# Placeholder macro written by tools/chip_assembly/macros.py
# kind: link; UCIe-A shoreline (die assembly 1.043 x 6.61 mm) at 1/4, one 512-bit flit port each way
VERSION 5.7 ;
BUSBITCHARS "[]" ;
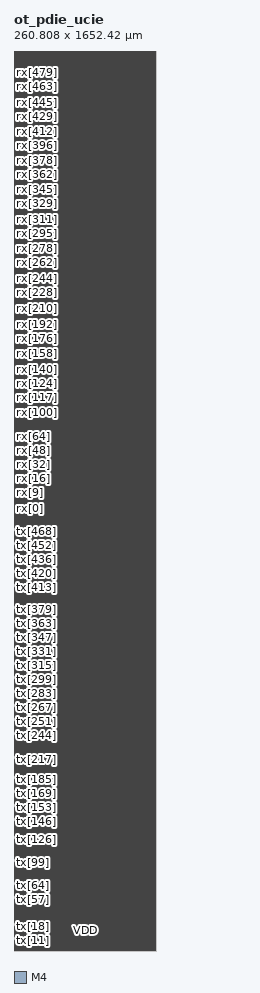
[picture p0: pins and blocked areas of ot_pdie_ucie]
MACRO ot_pdie_ucie
  FOREIGN ot_pdie_ucie 0 0 ;
  SYMMETRY X Y ;
  SIZE 260.808 BY 1652.424 ;
  CLASS BLOCK ;
  PIN clk
    DIRECTION INPUT ;
    USE SIGNAL ;
    SHAPE ABUTMENT ;
    PORT
      LAYER M4 ;
      RECT 0.000 0.528 0.192 0.552 ;
    END
  END clk
  PIN tx[0]
    DIRECTION INPUT ;
    USE SIGNAL ;
    SHAPE ABUTMENT ;
    PORT
      LAYER M4 ;
      RECT 0.000 2.112 0.192 2.136 ;
    END
  END tx[0]
  PIN tx[1]
    DIRECTION INPUT ;
    USE SIGNAL ;
    SHAPE ABUTMENT ;
    PORT
      LAYER M4 ;
      RECT 0.000 3.744 0.192 3.768 ;
    END
  END tx[1]
  PIN tx[2]
    DIRECTION INPUT ;
    USE SIGNAL ;
    SHAPE ABUTMENT ;
    PORT
      LAYER M4 ;
      RECT 0.000 5.328 0.192 5.352 ;
    END
  END tx[2]
  PIN tx[3]
    DIRECTION INPUT ;
    USE SIGNAL ;
    SHAPE ABUTMENT ;
    PORT
      LAYER M4 ;
      RECT 0.000 6.960 0.192 6.984 ;
    END
  END tx[3]
  PIN tx[4]
    DIRECTION INPUT ;
    USE SIGNAL ;
    SHAPE ABUTMENT ;
    PORT
      LAYER M4 ;
      RECT 0.000 8.544 0.192 8.568 ;
    END
  END tx[4]
  PIN tx[5]
    DIRECTION INPUT ;
    USE SIGNAL ;
    SHAPE ABUTMENT ;
    PORT
      LAYER M4 ;
      RECT 0.000 10.176 0.192 10.200 ;
    END
  END tx[5]
  PIN tx[6]
    DIRECTION INPUT ;
    USE SIGNAL ;
    SHAPE ABUTMENT ;
    PORT
      LAYER M4 ;
      RECT 0.000 11.760 0.192 11.784 ;
    END
  END tx[6]
  PIN tx[7]
    DIRECTION INPUT ;
    USE SIGNAL ;
    SHAPE ABUTMENT ;
    PORT
      LAYER M4 ;
      RECT 0.000 13.392 0.192 13.416 ;
    END
  END tx[7]
  PIN tx[8]
    DIRECTION INPUT ;
    USE SIGNAL ;
    SHAPE ABUTMENT ;
    PORT
      LAYER M4 ;
      RECT 0.000 15.024 0.192 15.048 ;
    END
  END tx[8]
  PIN tx[9]
    DIRECTION INPUT ;
    USE SIGNAL ;
    SHAPE ABUTMENT ;
    PORT
      LAYER M4 ;
      RECT 0.000 16.608 0.192 16.632 ;
    END
  END tx[9]
  PIN tx[10]
    DIRECTION INPUT ;
    USE SIGNAL ;
    SHAPE ABUTMENT ;
    PORT
      LAYER M4 ;
      RECT 0.000 18.240 0.192 18.264 ;
    END
  END tx[10]
  PIN tx[11]
    DIRECTION INPUT ;
    USE SIGNAL ;
    SHAPE ABUTMENT ;
    PORT
      LAYER M4 ;
      RECT 0.000 19.824 0.192 19.848 ;
    END
  END tx[11]
  PIN tx[12]
    DIRECTION INPUT ;
    USE SIGNAL ;
    SHAPE ABUTMENT ;
    PORT
      LAYER M4 ;
      RECT 0.000 21.456 0.192 21.480 ;
    END
  END tx[12]
  PIN tx[13]
    DIRECTION INPUT ;
    USE SIGNAL ;
    SHAPE ABUTMENT ;
    PORT
      LAYER M4 ;
      RECT 0.000 23.040 0.192 23.064 ;
    END
  END tx[13]
  PIN tx[14]
    DIRECTION INPUT ;
    USE SIGNAL ;
    SHAPE ABUTMENT ;
    PORT
      LAYER M4 ;
      RECT 0.000 24.672 0.192 24.696 ;
    END
  END tx[14]
  PIN tx[15]
    DIRECTION INPUT ;
    USE SIGNAL ;
    SHAPE ABUTMENT ;
    PORT
      LAYER M4 ;
      RECT 0.000 26.304 0.192 26.328 ;
    END
  END tx[15]
  PIN tx[16]
    DIRECTION INPUT ;
    USE SIGNAL ;
    SHAPE ABUTMENT ;
    PORT
      LAYER M4 ;
      RECT 0.000 27.888 0.192 27.912 ;
    END
  END tx[16]
  PIN tx[17]
    DIRECTION INPUT ;
    USE SIGNAL ;
    SHAPE ABUTMENT ;
    PORT
      LAYER M4 ;
      RECT 0.000 29.520 0.192 29.544 ;
    END
  END tx[17]
  PIN tx[18]
    DIRECTION INPUT ;
    USE SIGNAL ;
    SHAPE ABUTMENT ;
    PORT
      LAYER M4 ;
      RECT 0.000 31.104 0.192 31.128 ;
    END
  END tx[18]
  PIN tx[19]
    DIRECTION INPUT ;
    USE SIGNAL ;
    SHAPE ABUTMENT ;
    PORT
      LAYER M4 ;
      RECT 0.000 32.736 0.192 32.760 ;
    END
  END tx[19]
  PIN tx[20]
    DIRECTION INPUT ;
    USE SIGNAL ;
    SHAPE ABUTMENT ;
    PORT
      LAYER M4 ;
      RECT 0.000 34.320 0.192 34.344 ;
    END
  END tx[20]
  PIN tx[21]
    DIRECTION INPUT ;
    USE SIGNAL ;
    SHAPE ABUTMENT ;
    PORT
      LAYER M4 ;
      RECT 0.000 35.952 0.192 35.976 ;
    END
  END tx[21]
  PIN tx[22]
    DIRECTION INPUT ;
    USE SIGNAL ;
    SHAPE ABUTMENT ;
    PORT
      LAYER M4 ;
      RECT 0.000 37.536 0.192 37.560 ;
    END
  END tx[22]
  PIN tx[23]
    DIRECTION INPUT ;
    USE SIGNAL ;
    SHAPE ABUTMENT ;
    PORT
      LAYER M4 ;
      RECT 0.000 39.168 0.192 39.192 ;
    END
  END tx[23]
  PIN tx[24]
    DIRECTION INPUT ;
    USE SIGNAL ;
    SHAPE ABUTMENT ;
    PORT
      LAYER M4 ;
      RECT 0.000 40.800 0.192 40.824 ;
    END
  END tx[24]
  PIN tx[25]
    DIRECTION INPUT ;
    USE SIGNAL ;
    SHAPE ABUTMENT ;
    PORT
      LAYER M4 ;
      RECT 0.000 42.384 0.192 42.408 ;
    END
  END tx[25]
  PIN tx[26]
    DIRECTION INPUT ;
    USE SIGNAL ;
    SHAPE ABUTMENT ;
    PORT
      LAYER M4 ;
      RECT 0.000 44.016 0.192 44.040 ;
    END
  END tx[26]
  PIN tx[27]
    DIRECTION INPUT ;
    USE SIGNAL ;
    SHAPE ABUTMENT ;
    PORT
      LAYER M4 ;
      RECT 0.000 45.600 0.192 45.624 ;
    END
  END tx[27]
  PIN tx[28]
    DIRECTION INPUT ;
    USE SIGNAL ;
    SHAPE ABUTMENT ;
    PORT
      LAYER M4 ;
      RECT 0.000 47.232 0.192 47.256 ;
    END
  END tx[28]
  PIN tx[29]
    DIRECTION INPUT ;
    USE SIGNAL ;
    SHAPE ABUTMENT ;
    PORT
      LAYER M4 ;
      RECT 0.000 48.816 0.192 48.840 ;
    END
  END tx[29]
  PIN tx[30]
    DIRECTION INPUT ;
    USE SIGNAL ;
    SHAPE ABUTMENT ;
    PORT
      LAYER M4 ;
      RECT 0.000 50.448 0.192 50.472 ;
    END
  END tx[30]
  PIN tx[31]
    DIRECTION INPUT ;
    USE SIGNAL ;
    SHAPE ABUTMENT ;
    PORT
      LAYER M4 ;
      RECT 0.000 52.080 0.192 52.104 ;
    END
  END tx[31]
  PIN tx[32]
    DIRECTION INPUT ;
    USE SIGNAL ;
    SHAPE ABUTMENT ;
    PORT
      LAYER M4 ;
      RECT 0.000 53.664 0.192 53.688 ;
    END
  END tx[32]
  PIN tx[33]
    DIRECTION INPUT ;
    USE SIGNAL ;
    SHAPE ABUTMENT ;
    PORT
      LAYER M4 ;
      RECT 0.000 55.296 0.192 55.320 ;
    END
  END tx[33]
  PIN tx[34]
    DIRECTION INPUT ;
    USE SIGNAL ;
    SHAPE ABUTMENT ;
    PORT
      LAYER M4 ;
      RECT 0.000 56.880 0.192 56.904 ;
    END
  END tx[34]
  PIN tx[35]
    DIRECTION INPUT ;
    USE SIGNAL ;
    SHAPE ABUTMENT ;
    PORT
      LAYER M4 ;
      RECT 0.000 58.512 0.192 58.536 ;
    END
  END tx[35]
  PIN tx[36]
    DIRECTION INPUT ;
    USE SIGNAL ;
    SHAPE ABUTMENT ;
    PORT
      LAYER M4 ;
      RECT 0.000 60.096 0.192 60.120 ;
    END
  END tx[36]
  PIN tx[37]
    DIRECTION INPUT ;
    USE SIGNAL ;
    SHAPE ABUTMENT ;
    PORT
      LAYER M4 ;
      RECT 0.000 61.728 0.192 61.752 ;
    END
  END tx[37]
  PIN tx[38]
    DIRECTION INPUT ;
    USE SIGNAL ;
    SHAPE ABUTMENT ;
    PORT
      LAYER M4 ;
      RECT 0.000 63.360 0.192 63.384 ;
    END
  END tx[38]
  PIN tx[39]
    DIRECTION INPUT ;
    USE SIGNAL ;
    SHAPE ABUTMENT ;
    PORT
      LAYER M4 ;
      RECT 0.000 64.944 0.192 64.968 ;
    END
  END tx[39]
  PIN tx[40]
    DIRECTION INPUT ;
    USE SIGNAL ;
    SHAPE ABUTMENT ;
    PORT
      LAYER M4 ;
      RECT 0.000 66.576 0.192 66.600 ;
    END
  END tx[40]
  PIN tx[41]
    DIRECTION INPUT ;
    USE SIGNAL ;
    SHAPE ABUTMENT ;
    PORT
      LAYER M4 ;
      RECT 0.000 68.160 0.192 68.184 ;
    END
  END tx[41]
  PIN tx[42]
    DIRECTION INPUT ;
    USE SIGNAL ;
    SHAPE ABUTMENT ;
    PORT
      LAYER M4 ;
      RECT 0.000 69.792 0.192 69.816 ;
    END
  END tx[42]
  PIN tx[43]
    DIRECTION INPUT ;
    USE SIGNAL ;
    SHAPE ABUTMENT ;
    PORT
      LAYER M4 ;
      RECT 0.000 71.376 0.192 71.400 ;
    END
  END tx[43]
  PIN tx[44]
    DIRECTION INPUT ;
    USE SIGNAL ;
    SHAPE ABUTMENT ;
    PORT
      LAYER M4 ;
      RECT 0.000 73.008 0.192 73.032 ;
    END
  END tx[44]
  PIN tx[45]
    DIRECTION INPUT ;
    USE SIGNAL ;
    SHAPE ABUTMENT ;
    PORT
      LAYER M4 ;
      RECT 0.000 74.592 0.192 74.616 ;
    END
  END tx[45]
  PIN tx[46]
    DIRECTION INPUT ;
    USE SIGNAL ;
    SHAPE ABUTMENT ;
    PORT
      LAYER M4 ;
      RECT 0.000 76.224 0.192 76.248 ;
    END
  END tx[46]
  PIN tx[47]
    DIRECTION INPUT ;
    USE SIGNAL ;
    SHAPE ABUTMENT ;
    PORT
      LAYER M4 ;
      RECT 0.000 77.856 0.192 77.880 ;
    END
  END tx[47]
  PIN tx[48]
    DIRECTION INPUT ;
    USE SIGNAL ;
    SHAPE ABUTMENT ;
    PORT
      LAYER M4 ;
      RECT 0.000 79.440 0.192 79.464 ;
    END
  END tx[48]
  PIN tx[49]
    DIRECTION INPUT ;
    USE SIGNAL ;
    SHAPE ABUTMENT ;
    PORT
      LAYER M4 ;
      RECT 0.000 81.072 0.192 81.096 ;
    END
  END tx[49]
  PIN tx[50]
    DIRECTION INPUT ;
    USE SIGNAL ;
    SHAPE ABUTMENT ;
    PORT
      LAYER M4 ;
      RECT 0.000 82.656 0.192 82.680 ;
    END
  END tx[50]
  PIN tx[51]
    DIRECTION INPUT ;
    USE SIGNAL ;
    SHAPE ABUTMENT ;
    PORT
      LAYER M4 ;
      RECT 0.000 84.288 0.192 84.312 ;
    END
  END tx[51]
  PIN tx[52]
    DIRECTION INPUT ;
    USE SIGNAL ;
    SHAPE ABUTMENT ;
    PORT
      LAYER M4 ;
      RECT 0.000 85.872 0.192 85.896 ;
    END
  END tx[52]
  PIN tx[53]
    DIRECTION INPUT ;
    USE SIGNAL ;
    SHAPE ABUTMENT ;
    PORT
      LAYER M4 ;
      RECT 0.000 87.504 0.192 87.528 ;
    END
  END tx[53]
  PIN tx[54]
    DIRECTION INPUT ;
    USE SIGNAL ;
    SHAPE ABUTMENT ;
    PORT
      LAYER M4 ;
      RECT 0.000 89.136 0.192 89.160 ;
    END
  END tx[54]
  PIN tx[55]
    DIRECTION INPUT ;
    USE SIGNAL ;
    SHAPE ABUTMENT ;
    PORT
      LAYER M4 ;
      RECT 0.000 90.720 0.192 90.744 ;
    END
  END tx[55]
  PIN tx[56]
    DIRECTION INPUT ;
    USE SIGNAL ;
    SHAPE ABUTMENT ;
    PORT
      LAYER M4 ;
      RECT 0.000 92.352 0.192 92.376 ;
    END
  END tx[56]
  PIN tx[57]
    DIRECTION INPUT ;
    USE SIGNAL ;
    SHAPE ABUTMENT ;
    PORT
      LAYER M4 ;
      RECT 0.000 93.936 0.192 93.960 ;
    END
  END tx[57]
  PIN tx[58]
    DIRECTION INPUT ;
    USE SIGNAL ;
    SHAPE ABUTMENT ;
    PORT
      LAYER M4 ;
      RECT 0.000 95.568 0.192 95.592 ;
    END
  END tx[58]
  PIN tx[59]
    DIRECTION INPUT ;
    USE SIGNAL ;
    SHAPE ABUTMENT ;
    PORT
      LAYER M4 ;
      RECT 0.000 97.152 0.192 97.176 ;
    END
  END tx[59]
  PIN tx[60]
    DIRECTION INPUT ;
    USE SIGNAL ;
    SHAPE ABUTMENT ;
    PORT
      LAYER M4 ;
      RECT 0.000 98.784 0.192 98.808 ;
    END
  END tx[60]
  PIN tx[61]
    DIRECTION INPUT ;
    USE SIGNAL ;
    SHAPE ABUTMENT ;
    PORT
      LAYER M4 ;
      RECT 0.000 100.416 0.192 100.440 ;
    END
  END tx[61]
  PIN tx[62]
    DIRECTION INPUT ;
    USE SIGNAL ;
    SHAPE ABUTMENT ;
    PORT
      LAYER M4 ;
      RECT 0.000 102.000 0.192 102.024 ;
    END
  END tx[62]
  PIN tx[63]
    DIRECTION INPUT ;
    USE SIGNAL ;
    SHAPE ABUTMENT ;
    PORT
      LAYER M4 ;
      RECT 0.000 103.632 0.192 103.656 ;
    END
  END tx[63]
  PIN tx[64]
    DIRECTION INPUT ;
    USE SIGNAL ;
    SHAPE ABUTMENT ;
    PORT
      LAYER M4 ;
      RECT 0.000 105.216 0.192 105.240 ;
    END
  END tx[64]
  PIN tx[65]
    DIRECTION INPUT ;
    USE SIGNAL ;
    SHAPE ABUTMENT ;
    PORT
      LAYER M4 ;
      RECT 0.000 106.848 0.192 106.872 ;
    END
  END tx[65]
  PIN tx[66]
    DIRECTION INPUT ;
    USE SIGNAL ;
    SHAPE ABUTMENT ;
    PORT
      LAYER M4 ;
      RECT 0.000 108.432 0.192 108.456 ;
    END
  END tx[66]
  PIN tx[67]
    DIRECTION INPUT ;
    USE SIGNAL ;
    SHAPE ABUTMENT ;
    PORT
      LAYER M4 ;
      RECT 0.000 110.064 0.192 110.088 ;
    END
  END tx[67]
  PIN tx[68]
    DIRECTION INPUT ;
    USE SIGNAL ;
    SHAPE ABUTMENT ;
    PORT
      LAYER M4 ;
      RECT 0.000 111.648 0.192 111.672 ;
    END
  END tx[68]
  PIN tx[69]
    DIRECTION INPUT ;
    USE SIGNAL ;
    SHAPE ABUTMENT ;
    PORT
      LAYER M4 ;
      RECT 0.000 113.280 0.192 113.304 ;
    END
  END tx[69]
  PIN tx[70]
    DIRECTION INPUT ;
    USE SIGNAL ;
    SHAPE ABUTMENT ;
    PORT
      LAYER M4 ;
      RECT 0.000 114.912 0.192 114.936 ;
    END
  END tx[70]
  PIN tx[71]
    DIRECTION INPUT ;
    USE SIGNAL ;
    SHAPE ABUTMENT ;
    PORT
      LAYER M4 ;
      RECT 0.000 116.496 0.192 116.520 ;
    END
  END tx[71]
  PIN tx[72]
    DIRECTION INPUT ;
    USE SIGNAL ;
    SHAPE ABUTMENT ;
    PORT
      LAYER M4 ;
      RECT 0.000 118.128 0.192 118.152 ;
    END
  END tx[72]
  PIN tx[73]
    DIRECTION INPUT ;
    USE SIGNAL ;
    SHAPE ABUTMENT ;
    PORT
      LAYER M4 ;
      RECT 0.000 119.712 0.192 119.736 ;
    END
  END tx[73]
  PIN tx[74]
    DIRECTION INPUT ;
    USE SIGNAL ;
    SHAPE ABUTMENT ;
    PORT
      LAYER M4 ;
      RECT 0.000 121.344 0.192 121.368 ;
    END
  END tx[74]
  PIN tx[75]
    DIRECTION INPUT ;
    USE SIGNAL ;
    SHAPE ABUTMENT ;
    PORT
      LAYER M4 ;
      RECT 0.000 122.928 0.192 122.952 ;
    END
  END tx[75]
  PIN tx[76]
    DIRECTION INPUT ;
    USE SIGNAL ;
    SHAPE ABUTMENT ;
    PORT
      LAYER M4 ;
      RECT 0.000 124.560 0.192 124.584 ;
    END
  END tx[76]
  PIN tx[77]
    DIRECTION INPUT ;
    USE SIGNAL ;
    SHAPE ABUTMENT ;
    PORT
      LAYER M4 ;
      RECT 0.000 126.192 0.192 126.216 ;
    END
  END tx[77]
  PIN tx[78]
    DIRECTION INPUT ;
    USE SIGNAL ;
    SHAPE ABUTMENT ;
    PORT
      LAYER M4 ;
      RECT 0.000 127.776 0.192 127.800 ;
    END
  END tx[78]
  PIN tx[79]
    DIRECTION INPUT ;
    USE SIGNAL ;
    SHAPE ABUTMENT ;
    PORT
      LAYER M4 ;
      RECT 0.000 129.408 0.192 129.432 ;
    END
  END tx[79]
  PIN tx[80]
    DIRECTION INPUT ;
    USE SIGNAL ;
    SHAPE ABUTMENT ;
    PORT
      LAYER M4 ;
      RECT 0.000 130.992 0.192 131.016 ;
    END
  END tx[80]
  PIN tx[81]
    DIRECTION INPUT ;
    USE SIGNAL ;
    SHAPE ABUTMENT ;
    PORT
      LAYER M4 ;
      RECT 0.000 132.624 0.192 132.648 ;
    END
  END tx[81]
  PIN tx[82]
    DIRECTION INPUT ;
    USE SIGNAL ;
    SHAPE ABUTMENT ;
    PORT
      LAYER M4 ;
      RECT 0.000 134.208 0.192 134.232 ;
    END
  END tx[82]
  PIN tx[83]
    DIRECTION INPUT ;
    USE SIGNAL ;
    SHAPE ABUTMENT ;
    PORT
      LAYER M4 ;
      RECT 0.000 135.840 0.192 135.864 ;
    END
  END tx[83]
  PIN tx[84]
    DIRECTION INPUT ;
    USE SIGNAL ;
    SHAPE ABUTMENT ;
    PORT
      LAYER M4 ;
      RECT 0.000 137.472 0.192 137.496 ;
    END
  END tx[84]
  PIN tx[85]
    DIRECTION INPUT ;
    USE SIGNAL ;
    SHAPE ABUTMENT ;
    PORT
      LAYER M4 ;
      RECT 0.000 139.056 0.192 139.080 ;
    END
  END tx[85]
  PIN tx[86]
    DIRECTION INPUT ;
    USE SIGNAL ;
    SHAPE ABUTMENT ;
    PORT
      LAYER M4 ;
      RECT 0.000 140.688 0.192 140.712 ;
    END
  END tx[86]
  PIN tx[87]
    DIRECTION INPUT ;
    USE SIGNAL ;
    SHAPE ABUTMENT ;
    PORT
      LAYER M4 ;
      RECT 0.000 142.272 0.192 142.296 ;
    END
  END tx[87]
  PIN tx[88]
    DIRECTION INPUT ;
    USE SIGNAL ;
    SHAPE ABUTMENT ;
    PORT
      LAYER M4 ;
      RECT 0.000 143.904 0.192 143.928 ;
    END
  END tx[88]
  PIN tx[89]
    DIRECTION INPUT ;
    USE SIGNAL ;
    SHAPE ABUTMENT ;
    PORT
      LAYER M4 ;
      RECT 0.000 145.488 0.192 145.512 ;
    END
  END tx[89]
  PIN tx[90]
    DIRECTION INPUT ;
    USE SIGNAL ;
    SHAPE ABUTMENT ;
    PORT
      LAYER M4 ;
      RECT 0.000 147.120 0.192 147.144 ;
    END
  END tx[90]
  PIN tx[91]
    DIRECTION INPUT ;
    USE SIGNAL ;
    SHAPE ABUTMENT ;
    PORT
      LAYER M4 ;
      RECT 0.000 148.704 0.192 148.728 ;
    END
  END tx[91]
  PIN tx[92]
    DIRECTION INPUT ;
    USE SIGNAL ;
    SHAPE ABUTMENT ;
    PORT
      LAYER M4 ;
      RECT 0.000 150.336 0.192 150.360 ;
    END
  END tx[92]
  PIN tx[93]
    DIRECTION INPUT ;
    USE SIGNAL ;
    SHAPE ABUTMENT ;
    PORT
      LAYER M4 ;
      RECT 0.000 151.968 0.192 151.992 ;
    END
  END tx[93]
  PIN tx[94]
    DIRECTION INPUT ;
    USE SIGNAL ;
    SHAPE ABUTMENT ;
    PORT
      LAYER M4 ;
      RECT 0.000 153.552 0.192 153.576 ;
    END
  END tx[94]
  PIN tx[95]
    DIRECTION INPUT ;
    USE SIGNAL ;
    SHAPE ABUTMENT ;
    PORT
      LAYER M4 ;
      RECT 0.000 155.184 0.192 155.208 ;
    END
  END tx[95]
  PIN tx[96]
    DIRECTION INPUT ;
    USE SIGNAL ;
    SHAPE ABUTMENT ;
    PORT
      LAYER M4 ;
      RECT 0.000 156.768 0.192 156.792 ;
    END
  END tx[96]
  PIN tx[97]
    DIRECTION INPUT ;
    USE SIGNAL ;
    SHAPE ABUTMENT ;
    PORT
      LAYER M4 ;
      RECT 0.000 158.400 0.192 158.424 ;
    END
  END tx[97]
  PIN tx[98]
    DIRECTION INPUT ;
    USE SIGNAL ;
    SHAPE ABUTMENT ;
    PORT
      LAYER M4 ;
      RECT 0.000 159.984 0.192 160.008 ;
    END
  END tx[98]
  PIN tx[99]
    DIRECTION INPUT ;
    USE SIGNAL ;
    SHAPE ABUTMENT ;
    PORT
      LAYER M4 ;
      RECT 0.000 161.616 0.192 161.640 ;
    END
  END tx[99]
  PIN tx[100]
    DIRECTION INPUT ;
    USE SIGNAL ;
    SHAPE ABUTMENT ;
    PORT
      LAYER M4 ;
      RECT 0.000 163.248 0.192 163.272 ;
    END
  END tx[100]
  PIN tx[101]
    DIRECTION INPUT ;
    USE SIGNAL ;
    SHAPE ABUTMENT ;
    PORT
      LAYER M4 ;
      RECT 0.000 164.832 0.192 164.856 ;
    END
  END tx[101]
  PIN tx[102]
    DIRECTION INPUT ;
    USE SIGNAL ;
    SHAPE ABUTMENT ;
    PORT
      LAYER M4 ;
      RECT 0.000 166.464 0.192 166.488 ;
    END
  END tx[102]
  PIN tx[103]
    DIRECTION INPUT ;
    USE SIGNAL ;
    SHAPE ABUTMENT ;
    PORT
      LAYER M4 ;
      RECT 0.000 168.048 0.192 168.072 ;
    END
  END tx[103]
  PIN tx[104]
    DIRECTION INPUT ;
    USE SIGNAL ;
    SHAPE ABUTMENT ;
    PORT
      LAYER M4 ;
      RECT 0.000 169.680 0.192 169.704 ;
    END
  END tx[104]
  PIN tx[105]
    DIRECTION INPUT ;
    USE SIGNAL ;
    SHAPE ABUTMENT ;
    PORT
      LAYER M4 ;
      RECT 0.000 171.264 0.192 171.288 ;
    END
  END tx[105]
  PIN tx[106]
    DIRECTION INPUT ;
    USE SIGNAL ;
    SHAPE ABUTMENT ;
    PORT
      LAYER M4 ;
      RECT 0.000 172.896 0.192 172.920 ;
    END
  END tx[106]
  PIN tx[107]
    DIRECTION INPUT ;
    USE SIGNAL ;
    SHAPE ABUTMENT ;
    PORT
      LAYER M4 ;
      RECT 0.000 174.528 0.192 174.552 ;
    END
  END tx[107]
  PIN tx[108]
    DIRECTION INPUT ;
    USE SIGNAL ;
    SHAPE ABUTMENT ;
    PORT
      LAYER M4 ;
      RECT 0.000 176.112 0.192 176.136 ;
    END
  END tx[108]
  PIN tx[109]
    DIRECTION INPUT ;
    USE SIGNAL ;
    SHAPE ABUTMENT ;
    PORT
      LAYER M4 ;
      RECT 0.000 177.744 0.192 177.768 ;
    END
  END tx[109]
  PIN tx[110]
    DIRECTION INPUT ;
    USE SIGNAL ;
    SHAPE ABUTMENT ;
    PORT
      LAYER M4 ;
      RECT 0.000 179.328 0.192 179.352 ;
    END
  END tx[110]
  PIN tx[111]
    DIRECTION INPUT ;
    USE SIGNAL ;
    SHAPE ABUTMENT ;
    PORT
      LAYER M4 ;
      RECT 0.000 180.960 0.192 180.984 ;
    END
  END tx[111]
  PIN tx[112]
    DIRECTION INPUT ;
    USE SIGNAL ;
    SHAPE ABUTMENT ;
    PORT
      LAYER M4 ;
      RECT 0.000 182.544 0.192 182.568 ;
    END
  END tx[112]
  PIN tx[113]
    DIRECTION INPUT ;
    USE SIGNAL ;
    SHAPE ABUTMENT ;
    PORT
      LAYER M4 ;
      RECT 0.000 184.176 0.192 184.200 ;
    END
  END tx[113]
  PIN tx[114]
    DIRECTION INPUT ;
    USE SIGNAL ;
    SHAPE ABUTMENT ;
    PORT
      LAYER M4 ;
      RECT 0.000 185.760 0.192 185.784 ;
    END
  END tx[114]
  PIN tx[115]
    DIRECTION INPUT ;
    USE SIGNAL ;
    SHAPE ABUTMENT ;
    PORT
      LAYER M4 ;
      RECT 0.000 187.392 0.192 187.416 ;
    END
  END tx[115]
  PIN tx[116]
    DIRECTION INPUT ;
    USE SIGNAL ;
    SHAPE ABUTMENT ;
    PORT
      LAYER M4 ;
      RECT 0.000 189.024 0.192 189.048 ;
    END
  END tx[116]
  PIN tx[117]
    DIRECTION INPUT ;
    USE SIGNAL ;
    SHAPE ABUTMENT ;
    PORT
      LAYER M4 ;
      RECT 0.000 190.608 0.192 190.632 ;
    END
  END tx[117]
  PIN tx[118]
    DIRECTION INPUT ;
    USE SIGNAL ;
    SHAPE ABUTMENT ;
    PORT
      LAYER M4 ;
      RECT 0.000 192.240 0.192 192.264 ;
    END
  END tx[118]
  PIN tx[119]
    DIRECTION INPUT ;
    USE SIGNAL ;
    SHAPE ABUTMENT ;
    PORT
      LAYER M4 ;
      RECT 0.000 193.824 0.192 193.848 ;
    END
  END tx[119]
  PIN tx[120]
    DIRECTION INPUT ;
    USE SIGNAL ;
    SHAPE ABUTMENT ;
    PORT
      LAYER M4 ;
      RECT 0.000 195.456 0.192 195.480 ;
    END
  END tx[120]
  PIN tx[121]
    DIRECTION INPUT ;
    USE SIGNAL ;
    SHAPE ABUTMENT ;
    PORT
      LAYER M4 ;
      RECT 0.000 197.040 0.192 197.064 ;
    END
  END tx[121]
  PIN tx[122]
    DIRECTION INPUT ;
    USE SIGNAL ;
    SHAPE ABUTMENT ;
    PORT
      LAYER M4 ;
      RECT 0.000 198.672 0.192 198.696 ;
    END
  END tx[122]
  PIN tx[123]
    DIRECTION INPUT ;
    USE SIGNAL ;
    SHAPE ABUTMENT ;
    PORT
      LAYER M4 ;
      RECT 0.000 200.304 0.192 200.328 ;
    END
  END tx[123]
  PIN tx[124]
    DIRECTION INPUT ;
    USE SIGNAL ;
    SHAPE ABUTMENT ;
    PORT
      LAYER M4 ;
      RECT 0.000 201.888 0.192 201.912 ;
    END
  END tx[124]
  PIN tx[125]
    DIRECTION INPUT ;
    USE SIGNAL ;
    SHAPE ABUTMENT ;
    PORT
      LAYER M4 ;
      RECT 0.000 203.520 0.192 203.544 ;
    END
  END tx[125]
  PIN tx[126]
    DIRECTION INPUT ;
    USE SIGNAL ;
    SHAPE ABUTMENT ;
    PORT
      LAYER M4 ;
      RECT 0.000 205.104 0.192 205.128 ;
    END
  END tx[126]
  PIN tx[127]
    DIRECTION INPUT ;
    USE SIGNAL ;
    SHAPE ABUTMENT ;
    PORT
      LAYER M4 ;
      RECT 0.000 206.736 0.192 206.760 ;
    END
  END tx[127]
  PIN tx[128]
    DIRECTION INPUT ;
    USE SIGNAL ;
    SHAPE ABUTMENT ;
    PORT
      LAYER M4 ;
      RECT 0.000 208.320 0.192 208.344 ;
    END
  END tx[128]
  PIN tx[129]
    DIRECTION INPUT ;
    USE SIGNAL ;
    SHAPE ABUTMENT ;
    PORT
      LAYER M4 ;
      RECT 0.000 209.952 0.192 209.976 ;
    END
  END tx[129]
  PIN tx[130]
    DIRECTION INPUT ;
    USE SIGNAL ;
    SHAPE ABUTMENT ;
    PORT
      LAYER M4 ;
      RECT 0.000 211.536 0.192 211.560 ;
    END
  END tx[130]
  PIN tx[131]
    DIRECTION INPUT ;
    USE SIGNAL ;
    SHAPE ABUTMENT ;
    PORT
      LAYER M4 ;
      RECT 0.000 213.168 0.192 213.192 ;
    END
  END tx[131]
  PIN tx[132]
    DIRECTION INPUT ;
    USE SIGNAL ;
    SHAPE ABUTMENT ;
    PORT
      LAYER M4 ;
      RECT 0.000 214.800 0.192 214.824 ;
    END
  END tx[132]
  PIN tx[133]
    DIRECTION INPUT ;
    USE SIGNAL ;
    SHAPE ABUTMENT ;
    PORT
      LAYER M4 ;
      RECT 0.000 216.384 0.192 216.408 ;
    END
  END tx[133]
  PIN tx[134]
    DIRECTION INPUT ;
    USE SIGNAL ;
    SHAPE ABUTMENT ;
    PORT
      LAYER M4 ;
      RECT 0.000 218.016 0.192 218.040 ;
    END
  END tx[134]
  PIN tx[135]
    DIRECTION INPUT ;
    USE SIGNAL ;
    SHAPE ABUTMENT ;
    PORT
      LAYER M4 ;
      RECT 0.000 219.600 0.192 219.624 ;
    END
  END tx[135]
  PIN tx[136]
    DIRECTION INPUT ;
    USE SIGNAL ;
    SHAPE ABUTMENT ;
    PORT
      LAYER M4 ;
      RECT 0.000 221.232 0.192 221.256 ;
    END
  END tx[136]
  PIN tx[137]
    DIRECTION INPUT ;
    USE SIGNAL ;
    SHAPE ABUTMENT ;
    PORT
      LAYER M4 ;
      RECT 0.000 222.816 0.192 222.840 ;
    END
  END tx[137]
  PIN tx[138]
    DIRECTION INPUT ;
    USE SIGNAL ;
    SHAPE ABUTMENT ;
    PORT
      LAYER M4 ;
      RECT 0.000 224.448 0.192 224.472 ;
    END
  END tx[138]
  PIN tx[139]
    DIRECTION INPUT ;
    USE SIGNAL ;
    SHAPE ABUTMENT ;
    PORT
      LAYER M4 ;
      RECT 0.000 226.080 0.192 226.104 ;
    END
  END tx[139]
  PIN tx[140]
    DIRECTION INPUT ;
    USE SIGNAL ;
    SHAPE ABUTMENT ;
    PORT
      LAYER M4 ;
      RECT 0.000 227.664 0.192 227.688 ;
    END
  END tx[140]
  PIN tx[141]
    DIRECTION INPUT ;
    USE SIGNAL ;
    SHAPE ABUTMENT ;
    PORT
      LAYER M4 ;
      RECT 0.000 229.296 0.192 229.320 ;
    END
  END tx[141]
  PIN tx[142]
    DIRECTION INPUT ;
    USE SIGNAL ;
    SHAPE ABUTMENT ;
    PORT
      LAYER M4 ;
      RECT 0.000 230.880 0.192 230.904 ;
    END
  END tx[142]
  PIN tx[143]
    DIRECTION INPUT ;
    USE SIGNAL ;
    SHAPE ABUTMENT ;
    PORT
      LAYER M4 ;
      RECT 0.000 232.512 0.192 232.536 ;
    END
  END tx[143]
  PIN tx[144]
    DIRECTION INPUT ;
    USE SIGNAL ;
    SHAPE ABUTMENT ;
    PORT
      LAYER M4 ;
      RECT 0.000 234.096 0.192 234.120 ;
    END
  END tx[144]
  PIN tx[145]
    DIRECTION INPUT ;
    USE SIGNAL ;
    SHAPE ABUTMENT ;
    PORT
      LAYER M4 ;
      RECT 0.000 235.728 0.192 235.752 ;
    END
  END tx[145]
  PIN tx[146]
    DIRECTION INPUT ;
    USE SIGNAL ;
    SHAPE ABUTMENT ;
    PORT
      LAYER M4 ;
      RECT 0.000 237.360 0.192 237.384 ;
    END
  END tx[146]
  PIN tx[147]
    DIRECTION INPUT ;
    USE SIGNAL ;
    SHAPE ABUTMENT ;
    PORT
      LAYER M4 ;
      RECT 0.000 238.944 0.192 238.968 ;
    END
  END tx[147]
  PIN tx[148]
    DIRECTION INPUT ;
    USE SIGNAL ;
    SHAPE ABUTMENT ;
    PORT
      LAYER M4 ;
      RECT 0.000 240.576 0.192 240.600 ;
    END
  END tx[148]
  PIN tx[149]
    DIRECTION INPUT ;
    USE SIGNAL ;
    SHAPE ABUTMENT ;
    PORT
      LAYER M4 ;
      RECT 0.000 242.160 0.192 242.184 ;
    END
  END tx[149]
  PIN tx[150]
    DIRECTION INPUT ;
    USE SIGNAL ;
    SHAPE ABUTMENT ;
    PORT
      LAYER M4 ;
      RECT 0.000 243.792 0.192 243.816 ;
    END
  END tx[150]
  PIN tx[151]
    DIRECTION INPUT ;
    USE SIGNAL ;
    SHAPE ABUTMENT ;
    PORT
      LAYER M4 ;
      RECT 0.000 245.376 0.192 245.400 ;
    END
  END tx[151]
  PIN tx[152]
    DIRECTION INPUT ;
    USE SIGNAL ;
    SHAPE ABUTMENT ;
    PORT
      LAYER M4 ;
      RECT 0.000 247.008 0.192 247.032 ;
    END
  END tx[152]
  PIN tx[153]
    DIRECTION INPUT ;
    USE SIGNAL ;
    SHAPE ABUTMENT ;
    PORT
      LAYER M4 ;
      RECT 0.000 248.592 0.192 248.616 ;
    END
  END tx[153]
  PIN tx[154]
    DIRECTION INPUT ;
    USE SIGNAL ;
    SHAPE ABUTMENT ;
    PORT
      LAYER M4 ;
      RECT 0.000 250.224 0.192 250.248 ;
    END
  END tx[154]
  PIN tx[155]
    DIRECTION INPUT ;
    USE SIGNAL ;
    SHAPE ABUTMENT ;
    PORT
      LAYER M4 ;
      RECT 0.000 251.856 0.192 251.880 ;
    END
  END tx[155]
  PIN tx[156]
    DIRECTION INPUT ;
    USE SIGNAL ;
    SHAPE ABUTMENT ;
    PORT
      LAYER M4 ;
      RECT 0.000 253.440 0.192 253.464 ;
    END
  END tx[156]
  PIN tx[157]
    DIRECTION INPUT ;
    USE SIGNAL ;
    SHAPE ABUTMENT ;
    PORT
      LAYER M4 ;
      RECT 0.000 255.072 0.192 255.096 ;
    END
  END tx[157]
  PIN tx[158]
    DIRECTION INPUT ;
    USE SIGNAL ;
    SHAPE ABUTMENT ;
    PORT
      LAYER M4 ;
      RECT 0.000 256.656 0.192 256.680 ;
    END
  END tx[158]
  PIN tx[159]
    DIRECTION INPUT ;
    USE SIGNAL ;
    SHAPE ABUTMENT ;
    PORT
      LAYER M4 ;
      RECT 0.000 258.288 0.192 258.312 ;
    END
  END tx[159]
  PIN tx[160]
    DIRECTION INPUT ;
    USE SIGNAL ;
    SHAPE ABUTMENT ;
    PORT
      LAYER M4 ;
      RECT 0.000 259.872 0.192 259.896 ;
    END
  END tx[160]
  PIN tx[161]
    DIRECTION INPUT ;
    USE SIGNAL ;
    SHAPE ABUTMENT ;
    PORT
      LAYER M4 ;
      RECT 0.000 261.504 0.192 261.528 ;
    END
  END tx[161]
  PIN tx[162]
    DIRECTION INPUT ;
    USE SIGNAL ;
    SHAPE ABUTMENT ;
    PORT
      LAYER M4 ;
      RECT 0.000 263.136 0.192 263.160 ;
    END
  END tx[162]
  PIN tx[163]
    DIRECTION INPUT ;
    USE SIGNAL ;
    SHAPE ABUTMENT ;
    PORT
      LAYER M4 ;
      RECT 0.000 264.720 0.192 264.744 ;
    END
  END tx[163]
  PIN tx[164]
    DIRECTION INPUT ;
    USE SIGNAL ;
    SHAPE ABUTMENT ;
    PORT
      LAYER M4 ;
      RECT 0.000 266.352 0.192 266.376 ;
    END
  END tx[164]
  PIN tx[165]
    DIRECTION INPUT ;
    USE SIGNAL ;
    SHAPE ABUTMENT ;
    PORT
      LAYER M4 ;
      RECT 0.000 267.936 0.192 267.960 ;
    END
  END tx[165]
  PIN tx[166]
    DIRECTION INPUT ;
    USE SIGNAL ;
    SHAPE ABUTMENT ;
    PORT
      LAYER M4 ;
      RECT 0.000 269.568 0.192 269.592 ;
    END
  END tx[166]
  PIN tx[167]
    DIRECTION INPUT ;
    USE SIGNAL ;
    SHAPE ABUTMENT ;
    PORT
      LAYER M4 ;
      RECT 0.000 271.152 0.192 271.176 ;
    END
  END tx[167]
  PIN tx[168]
    DIRECTION INPUT ;
    USE SIGNAL ;
    SHAPE ABUTMENT ;
    PORT
      LAYER M4 ;
      RECT 0.000 272.784 0.192 272.808 ;
    END
  END tx[168]
  PIN tx[169]
    DIRECTION INPUT ;
    USE SIGNAL ;
    SHAPE ABUTMENT ;
    PORT
      LAYER M4 ;
      RECT 0.000 274.416 0.192 274.440 ;
    END
  END tx[169]
  PIN tx[170]
    DIRECTION INPUT ;
    USE SIGNAL ;
    SHAPE ABUTMENT ;
    PORT
      LAYER M4 ;
      RECT 0.000 276.000 0.192 276.024 ;
    END
  END tx[170]
  PIN tx[171]
    DIRECTION INPUT ;
    USE SIGNAL ;
    SHAPE ABUTMENT ;
    PORT
      LAYER M4 ;
      RECT 0.000 277.632 0.192 277.656 ;
    END
  END tx[171]
  PIN tx[172]
    DIRECTION INPUT ;
    USE SIGNAL ;
    SHAPE ABUTMENT ;
    PORT
      LAYER M4 ;
      RECT 0.000 279.216 0.192 279.240 ;
    END
  END tx[172]
  PIN tx[173]
    DIRECTION INPUT ;
    USE SIGNAL ;
    SHAPE ABUTMENT ;
    PORT
      LAYER M4 ;
      RECT 0.000 280.848 0.192 280.872 ;
    END
  END tx[173]
  PIN tx[174]
    DIRECTION INPUT ;
    USE SIGNAL ;
    SHAPE ABUTMENT ;
    PORT
      LAYER M4 ;
      RECT 0.000 282.432 0.192 282.456 ;
    END
  END tx[174]
  PIN tx[175]
    DIRECTION INPUT ;
    USE SIGNAL ;
    SHAPE ABUTMENT ;
    PORT
      LAYER M4 ;
      RECT 0.000 284.064 0.192 284.088 ;
    END
  END tx[175]
  PIN tx[176]
    DIRECTION INPUT ;
    USE SIGNAL ;
    SHAPE ABUTMENT ;
    PORT
      LAYER M4 ;
      RECT 0.000 285.648 0.192 285.672 ;
    END
  END tx[176]
  PIN tx[177]
    DIRECTION INPUT ;
    USE SIGNAL ;
    SHAPE ABUTMENT ;
    PORT
      LAYER M4 ;
      RECT 0.000 287.280 0.192 287.304 ;
    END
  END tx[177]
  PIN tx[178]
    DIRECTION INPUT ;
    USE SIGNAL ;
    SHAPE ABUTMENT ;
    PORT
      LAYER M4 ;
      RECT 0.000 288.912 0.192 288.936 ;
    END
  END tx[178]
  PIN tx[179]
    DIRECTION INPUT ;
    USE SIGNAL ;
    SHAPE ABUTMENT ;
    PORT
      LAYER M4 ;
      RECT 0.000 290.496 0.192 290.520 ;
    END
  END tx[179]
  PIN tx[180]
    DIRECTION INPUT ;
    USE SIGNAL ;
    SHAPE ABUTMENT ;
    PORT
      LAYER M4 ;
      RECT 0.000 292.128 0.192 292.152 ;
    END
  END tx[180]
  PIN tx[181]
    DIRECTION INPUT ;
    USE SIGNAL ;
    SHAPE ABUTMENT ;
    PORT
      LAYER M4 ;
      RECT 0.000 293.712 0.192 293.736 ;
    END
  END tx[181]
  PIN tx[182]
    DIRECTION INPUT ;
    USE SIGNAL ;
    SHAPE ABUTMENT ;
    PORT
      LAYER M4 ;
      RECT 0.000 295.344 0.192 295.368 ;
    END
  END tx[182]
  PIN tx[183]
    DIRECTION INPUT ;
    USE SIGNAL ;
    SHAPE ABUTMENT ;
    PORT
      LAYER M4 ;
      RECT 0.000 296.928 0.192 296.952 ;
    END
  END tx[183]
  PIN tx[184]
    DIRECTION INPUT ;
    USE SIGNAL ;
    SHAPE ABUTMENT ;
    PORT
      LAYER M4 ;
      RECT 0.000 298.560 0.192 298.584 ;
    END
  END tx[184]
  PIN tx[185]
    DIRECTION INPUT ;
    USE SIGNAL ;
    SHAPE ABUTMENT ;
    PORT
      LAYER M4 ;
      RECT 0.000 300.192 0.192 300.216 ;
    END
  END tx[185]
  PIN tx[186]
    DIRECTION INPUT ;
    USE SIGNAL ;
    SHAPE ABUTMENT ;
    PORT
      LAYER M4 ;
      RECT 0.000 301.776 0.192 301.800 ;
    END
  END tx[186]
  PIN tx[187]
    DIRECTION INPUT ;
    USE SIGNAL ;
    SHAPE ABUTMENT ;
    PORT
      LAYER M4 ;
      RECT 0.000 303.408 0.192 303.432 ;
    END
  END tx[187]
  PIN tx[188]
    DIRECTION INPUT ;
    USE SIGNAL ;
    SHAPE ABUTMENT ;
    PORT
      LAYER M4 ;
      RECT 0.000 304.992 0.192 305.016 ;
    END
  END tx[188]
  PIN tx[189]
    DIRECTION INPUT ;
    USE SIGNAL ;
    SHAPE ABUTMENT ;
    PORT
      LAYER M4 ;
      RECT 0.000 306.624 0.192 306.648 ;
    END
  END tx[189]
  PIN tx[190]
    DIRECTION INPUT ;
    USE SIGNAL ;
    SHAPE ABUTMENT ;
    PORT
      LAYER M4 ;
      RECT 0.000 308.208 0.192 308.232 ;
    END
  END tx[190]
  PIN tx[191]
    DIRECTION INPUT ;
    USE SIGNAL ;
    SHAPE ABUTMENT ;
    PORT
      LAYER M4 ;
      RECT 0.000 309.840 0.192 309.864 ;
    END
  END tx[191]
  PIN tx[192]
    DIRECTION INPUT ;
    USE SIGNAL ;
    SHAPE ABUTMENT ;
    PORT
      LAYER M4 ;
      RECT 0.000 311.472 0.192 311.496 ;
    END
  END tx[192]
  PIN tx[193]
    DIRECTION INPUT ;
    USE SIGNAL ;
    SHAPE ABUTMENT ;
    PORT
      LAYER M4 ;
      RECT 0.000 313.056 0.192 313.080 ;
    END
  END tx[193]
  PIN tx[194]
    DIRECTION INPUT ;
    USE SIGNAL ;
    SHAPE ABUTMENT ;
    PORT
      LAYER M4 ;
      RECT 0.000 314.688 0.192 314.712 ;
    END
  END tx[194]
  PIN tx[195]
    DIRECTION INPUT ;
    USE SIGNAL ;
    SHAPE ABUTMENT ;
    PORT
      LAYER M4 ;
      RECT 0.000 316.272 0.192 316.296 ;
    END
  END tx[195]
  PIN tx[196]
    DIRECTION INPUT ;
    USE SIGNAL ;
    SHAPE ABUTMENT ;
    PORT
      LAYER M4 ;
      RECT 0.000 317.904 0.192 317.928 ;
    END
  END tx[196]
  PIN tx[197]
    DIRECTION INPUT ;
    USE SIGNAL ;
    SHAPE ABUTMENT ;
    PORT
      LAYER M4 ;
      RECT 0.000 319.488 0.192 319.512 ;
    END
  END tx[197]
  PIN tx[198]
    DIRECTION INPUT ;
    USE SIGNAL ;
    SHAPE ABUTMENT ;
    PORT
      LAYER M4 ;
      RECT 0.000 321.120 0.192 321.144 ;
    END
  END tx[198]
  PIN tx[199]
    DIRECTION INPUT ;
    USE SIGNAL ;
    SHAPE ABUTMENT ;
    PORT
      LAYER M4 ;
      RECT 0.000 322.704 0.192 322.728 ;
    END
  END tx[199]
  PIN tx[200]
    DIRECTION INPUT ;
    USE SIGNAL ;
    SHAPE ABUTMENT ;
    PORT
      LAYER M4 ;
      RECT 0.000 324.336 0.192 324.360 ;
    END
  END tx[200]
  PIN tx[201]
    DIRECTION INPUT ;
    USE SIGNAL ;
    SHAPE ABUTMENT ;
    PORT
      LAYER M4 ;
      RECT 0.000 325.968 0.192 325.992 ;
    END
  END tx[201]
  PIN tx[202]
    DIRECTION INPUT ;
    USE SIGNAL ;
    SHAPE ABUTMENT ;
    PORT
      LAYER M4 ;
      RECT 0.000 327.552 0.192 327.576 ;
    END
  END tx[202]
  PIN tx[203]
    DIRECTION INPUT ;
    USE SIGNAL ;
    SHAPE ABUTMENT ;
    PORT
      LAYER M4 ;
      RECT 0.000 329.184 0.192 329.208 ;
    END
  END tx[203]
  PIN tx[204]
    DIRECTION INPUT ;
    USE SIGNAL ;
    SHAPE ABUTMENT ;
    PORT
      LAYER M4 ;
      RECT 0.000 330.768 0.192 330.792 ;
    END
  END tx[204]
  PIN tx[205]
    DIRECTION INPUT ;
    USE SIGNAL ;
    SHAPE ABUTMENT ;
    PORT
      LAYER M4 ;
      RECT 0.000 332.400 0.192 332.424 ;
    END
  END tx[205]
  PIN tx[206]
    DIRECTION INPUT ;
    USE SIGNAL ;
    SHAPE ABUTMENT ;
    PORT
      LAYER M4 ;
      RECT 0.000 333.984 0.192 334.008 ;
    END
  END tx[206]
  PIN tx[207]
    DIRECTION INPUT ;
    USE SIGNAL ;
    SHAPE ABUTMENT ;
    PORT
      LAYER M4 ;
      RECT 0.000 335.616 0.192 335.640 ;
    END
  END tx[207]
  PIN tx[208]
    DIRECTION INPUT ;
    USE SIGNAL ;
    SHAPE ABUTMENT ;
    PORT
      LAYER M4 ;
      RECT 0.000 337.248 0.192 337.272 ;
    END
  END tx[208]
  PIN tx[209]
    DIRECTION INPUT ;
    USE SIGNAL ;
    SHAPE ABUTMENT ;
    PORT
      LAYER M4 ;
      RECT 0.000 338.832 0.192 338.856 ;
    END
  END tx[209]
  PIN tx[210]
    DIRECTION INPUT ;
    USE SIGNAL ;
    SHAPE ABUTMENT ;
    PORT
      LAYER M4 ;
      RECT 0.000 340.464 0.192 340.488 ;
    END
  END tx[210]
  PIN tx[211]
    DIRECTION INPUT ;
    USE SIGNAL ;
    SHAPE ABUTMENT ;
    PORT
      LAYER M4 ;
      RECT 0.000 342.048 0.192 342.072 ;
    END
  END tx[211]
  PIN tx[212]
    DIRECTION INPUT ;
    USE SIGNAL ;
    SHAPE ABUTMENT ;
    PORT
      LAYER M4 ;
      RECT 0.000 343.680 0.192 343.704 ;
    END
  END tx[212]
  PIN tx[213]
    DIRECTION INPUT ;
    USE SIGNAL ;
    SHAPE ABUTMENT ;
    PORT
      LAYER M4 ;
      RECT 0.000 345.264 0.192 345.288 ;
    END
  END tx[213]
  PIN tx[214]
    DIRECTION INPUT ;
    USE SIGNAL ;
    SHAPE ABUTMENT ;
    PORT
      LAYER M4 ;
      RECT 0.000 346.896 0.192 346.920 ;
    END
  END tx[214]
  PIN tx[215]
    DIRECTION INPUT ;
    USE SIGNAL ;
    SHAPE ABUTMENT ;
    PORT
      LAYER M4 ;
      RECT 0.000 348.528 0.192 348.552 ;
    END
  END tx[215]
  PIN tx[216]
    DIRECTION INPUT ;
    USE SIGNAL ;
    SHAPE ABUTMENT ;
    PORT
      LAYER M4 ;
      RECT 0.000 350.112 0.192 350.136 ;
    END
  END tx[216]
  PIN tx[217]
    DIRECTION INPUT ;
    USE SIGNAL ;
    SHAPE ABUTMENT ;
    PORT
      LAYER M4 ;
      RECT 0.000 351.744 0.192 351.768 ;
    END
  END tx[217]
  PIN tx[218]
    DIRECTION INPUT ;
    USE SIGNAL ;
    SHAPE ABUTMENT ;
    PORT
      LAYER M4 ;
      RECT 0.000 353.328 0.192 353.352 ;
    END
  END tx[218]
  PIN tx[219]
    DIRECTION INPUT ;
    USE SIGNAL ;
    SHAPE ABUTMENT ;
    PORT
      LAYER M4 ;
      RECT 0.000 354.960 0.192 354.984 ;
    END
  END tx[219]
  PIN tx[220]
    DIRECTION INPUT ;
    USE SIGNAL ;
    SHAPE ABUTMENT ;
    PORT
      LAYER M4 ;
      RECT 0.000 356.544 0.192 356.568 ;
    END
  END tx[220]
  PIN tx[221]
    DIRECTION INPUT ;
    USE SIGNAL ;
    SHAPE ABUTMENT ;
    PORT
      LAYER M4 ;
      RECT 0.000 358.176 0.192 358.200 ;
    END
  END tx[221]
  PIN tx[222]
    DIRECTION INPUT ;
    USE SIGNAL ;
    SHAPE ABUTMENT ;
    PORT
      LAYER M4 ;
      RECT 0.000 359.760 0.192 359.784 ;
    END
  END tx[222]
  PIN tx[223]
    DIRECTION INPUT ;
    USE SIGNAL ;
    SHAPE ABUTMENT ;
    PORT
      LAYER M4 ;
      RECT 0.000 361.392 0.192 361.416 ;
    END
  END tx[223]
  PIN tx[224]
    DIRECTION INPUT ;
    USE SIGNAL ;
    SHAPE ABUTMENT ;
    PORT
      LAYER M4 ;
      RECT 0.000 363.024 0.192 363.048 ;
    END
  END tx[224]
  PIN tx[225]
    DIRECTION INPUT ;
    USE SIGNAL ;
    SHAPE ABUTMENT ;
    PORT
      LAYER M4 ;
      RECT 0.000 364.608 0.192 364.632 ;
    END
  END tx[225]
  PIN tx[226]
    DIRECTION INPUT ;
    USE SIGNAL ;
    SHAPE ABUTMENT ;
    PORT
      LAYER M4 ;
      RECT 0.000 366.240 0.192 366.264 ;
    END
  END tx[226]
  PIN tx[227]
    DIRECTION INPUT ;
    USE SIGNAL ;
    SHAPE ABUTMENT ;
    PORT
      LAYER M4 ;
      RECT 0.000 367.824 0.192 367.848 ;
    END
  END tx[227]
  PIN tx[228]
    DIRECTION INPUT ;
    USE SIGNAL ;
    SHAPE ABUTMENT ;
    PORT
      LAYER M4 ;
      RECT 0.000 369.456 0.192 369.480 ;
    END
  END tx[228]
  PIN tx[229]
    DIRECTION INPUT ;
    USE SIGNAL ;
    SHAPE ABUTMENT ;
    PORT
      LAYER M4 ;
      RECT 0.000 371.040 0.192 371.064 ;
    END
  END tx[229]
  PIN tx[230]
    DIRECTION INPUT ;
    USE SIGNAL ;
    SHAPE ABUTMENT ;
    PORT
      LAYER M4 ;
      RECT 0.000 372.672 0.192 372.696 ;
    END
  END tx[230]
  PIN tx[231]
    DIRECTION INPUT ;
    USE SIGNAL ;
    SHAPE ABUTMENT ;
    PORT
      LAYER M4 ;
      RECT 0.000 374.304 0.192 374.328 ;
    END
  END tx[231]
  PIN tx[232]
    DIRECTION INPUT ;
    USE SIGNAL ;
    SHAPE ABUTMENT ;
    PORT
      LAYER M4 ;
      RECT 0.000 375.888 0.192 375.912 ;
    END
  END tx[232]
  PIN tx[233]
    DIRECTION INPUT ;
    USE SIGNAL ;
    SHAPE ABUTMENT ;
    PORT
      LAYER M4 ;
      RECT 0.000 377.520 0.192 377.544 ;
    END
  END tx[233]
  PIN tx[234]
    DIRECTION INPUT ;
    USE SIGNAL ;
    SHAPE ABUTMENT ;
    PORT
      LAYER M4 ;
      RECT 0.000 379.104 0.192 379.128 ;
    END
  END tx[234]
  PIN tx[235]
    DIRECTION INPUT ;
    USE SIGNAL ;
    SHAPE ABUTMENT ;
    PORT
      LAYER M4 ;
      RECT 0.000 380.736 0.192 380.760 ;
    END
  END tx[235]
  PIN tx[236]
    DIRECTION INPUT ;
    USE SIGNAL ;
    SHAPE ABUTMENT ;
    PORT
      LAYER M4 ;
      RECT 0.000 382.320 0.192 382.344 ;
    END
  END tx[236]
  PIN tx[237]
    DIRECTION INPUT ;
    USE SIGNAL ;
    SHAPE ABUTMENT ;
    PORT
      LAYER M4 ;
      RECT 0.000 383.952 0.192 383.976 ;
    END
  END tx[237]
  PIN tx[238]
    DIRECTION INPUT ;
    USE SIGNAL ;
    SHAPE ABUTMENT ;
    PORT
      LAYER M4 ;
      RECT 0.000 385.584 0.192 385.608 ;
    END
  END tx[238]
  PIN tx[239]
    DIRECTION INPUT ;
    USE SIGNAL ;
    SHAPE ABUTMENT ;
    PORT
      LAYER M4 ;
      RECT 0.000 387.168 0.192 387.192 ;
    END
  END tx[239]
  PIN tx[240]
    DIRECTION INPUT ;
    USE SIGNAL ;
    SHAPE ABUTMENT ;
    PORT
      LAYER M4 ;
      RECT 0.000 388.800 0.192 388.824 ;
    END
  END tx[240]
  PIN tx[241]
    DIRECTION INPUT ;
    USE SIGNAL ;
    SHAPE ABUTMENT ;
    PORT
      LAYER M4 ;
      RECT 0.000 390.384 0.192 390.408 ;
    END
  END tx[241]
  PIN tx[242]
    DIRECTION INPUT ;
    USE SIGNAL ;
    SHAPE ABUTMENT ;
    PORT
      LAYER M4 ;
      RECT 0.000 392.016 0.192 392.040 ;
    END
  END tx[242]
  PIN tx[243]
    DIRECTION INPUT ;
    USE SIGNAL ;
    SHAPE ABUTMENT ;
    PORT
      LAYER M4 ;
      RECT 0.000 393.600 0.192 393.624 ;
    END
  END tx[243]
  PIN tx[244]
    DIRECTION INPUT ;
    USE SIGNAL ;
    SHAPE ABUTMENT ;
    PORT
      LAYER M4 ;
      RECT 0.000 395.232 0.192 395.256 ;
    END
  END tx[244]
  PIN tx[245]
    DIRECTION INPUT ;
    USE SIGNAL ;
    SHAPE ABUTMENT ;
    PORT
      LAYER M4 ;
      RECT 0.000 396.816 0.192 396.840 ;
    END
  END tx[245]
  PIN tx[246]
    DIRECTION INPUT ;
    USE SIGNAL ;
    SHAPE ABUTMENT ;
    PORT
      LAYER M4 ;
      RECT 0.000 398.448 0.192 398.472 ;
    END
  END tx[246]
  PIN tx[247]
    DIRECTION INPUT ;
    USE SIGNAL ;
    SHAPE ABUTMENT ;
    PORT
      LAYER M4 ;
      RECT 0.000 400.080 0.192 400.104 ;
    END
  END tx[247]
  PIN tx[248]
    DIRECTION INPUT ;
    USE SIGNAL ;
    SHAPE ABUTMENT ;
    PORT
      LAYER M4 ;
      RECT 0.000 401.664 0.192 401.688 ;
    END
  END tx[248]
  PIN tx[249]
    DIRECTION INPUT ;
    USE SIGNAL ;
    SHAPE ABUTMENT ;
    PORT
      LAYER M4 ;
      RECT 0.000 403.296 0.192 403.320 ;
    END
  END tx[249]
  PIN tx[250]
    DIRECTION INPUT ;
    USE SIGNAL ;
    SHAPE ABUTMENT ;
    PORT
      LAYER M4 ;
      RECT 0.000 404.880 0.192 404.904 ;
    END
  END tx[250]
  PIN tx[251]
    DIRECTION INPUT ;
    USE SIGNAL ;
    SHAPE ABUTMENT ;
    PORT
      LAYER M4 ;
      RECT 0.000 406.512 0.192 406.536 ;
    END
  END tx[251]
  PIN tx[252]
    DIRECTION INPUT ;
    USE SIGNAL ;
    SHAPE ABUTMENT ;
    PORT
      LAYER M4 ;
      RECT 0.000 408.096 0.192 408.120 ;
    END
  END tx[252]
  PIN tx[253]
    DIRECTION INPUT ;
    USE SIGNAL ;
    SHAPE ABUTMENT ;
    PORT
      LAYER M4 ;
      RECT 0.000 409.728 0.192 409.752 ;
    END
  END tx[253]
  PIN tx[254]
    DIRECTION INPUT ;
    USE SIGNAL ;
    SHAPE ABUTMENT ;
    PORT
      LAYER M4 ;
      RECT 0.000 411.360 0.192 411.384 ;
    END
  END tx[254]
  PIN tx[255]
    DIRECTION INPUT ;
    USE SIGNAL ;
    SHAPE ABUTMENT ;
    PORT
      LAYER M4 ;
      RECT 0.000 412.944 0.192 412.968 ;
    END
  END tx[255]
  PIN tx[256]
    DIRECTION INPUT ;
    USE SIGNAL ;
    SHAPE ABUTMENT ;
    PORT
      LAYER M4 ;
      RECT 0.000 414.576 0.192 414.600 ;
    END
  END tx[256]
  PIN tx[257]
    DIRECTION INPUT ;
    USE SIGNAL ;
    SHAPE ABUTMENT ;
    PORT
      LAYER M4 ;
      RECT 0.000 416.160 0.192 416.184 ;
    END
  END tx[257]
  PIN tx[258]
    DIRECTION INPUT ;
    USE SIGNAL ;
    SHAPE ABUTMENT ;
    PORT
      LAYER M4 ;
      RECT 0.000 417.792 0.192 417.816 ;
    END
  END tx[258]
  PIN tx[259]
    DIRECTION INPUT ;
    USE SIGNAL ;
    SHAPE ABUTMENT ;
    PORT
      LAYER M4 ;
      RECT 0.000 419.376 0.192 419.400 ;
    END
  END tx[259]
  PIN tx[260]
    DIRECTION INPUT ;
    USE SIGNAL ;
    SHAPE ABUTMENT ;
    PORT
      LAYER M4 ;
      RECT 0.000 421.008 0.192 421.032 ;
    END
  END tx[260]
  PIN tx[261]
    DIRECTION INPUT ;
    USE SIGNAL ;
    SHAPE ABUTMENT ;
    PORT
      LAYER M4 ;
      RECT 0.000 422.592 0.192 422.616 ;
    END
  END tx[261]
  PIN tx[262]
    DIRECTION INPUT ;
    USE SIGNAL ;
    SHAPE ABUTMENT ;
    PORT
      LAYER M4 ;
      RECT 0.000 424.224 0.192 424.248 ;
    END
  END tx[262]
  PIN tx[263]
    DIRECTION INPUT ;
    USE SIGNAL ;
    SHAPE ABUTMENT ;
    PORT
      LAYER M4 ;
      RECT 0.000 425.856 0.192 425.880 ;
    END
  END tx[263]
  PIN tx[264]
    DIRECTION INPUT ;
    USE SIGNAL ;
    SHAPE ABUTMENT ;
    PORT
      LAYER M4 ;
      RECT 0.000 427.440 0.192 427.464 ;
    END
  END tx[264]
  PIN tx[265]
    DIRECTION INPUT ;
    USE SIGNAL ;
    SHAPE ABUTMENT ;
    PORT
      LAYER M4 ;
      RECT 0.000 429.072 0.192 429.096 ;
    END
  END tx[265]
  PIN tx[266]
    DIRECTION INPUT ;
    USE SIGNAL ;
    SHAPE ABUTMENT ;
    PORT
      LAYER M4 ;
      RECT 0.000 430.656 0.192 430.680 ;
    END
  END tx[266]
  PIN tx[267]
    DIRECTION INPUT ;
    USE SIGNAL ;
    SHAPE ABUTMENT ;
    PORT
      LAYER M4 ;
      RECT 0.000 432.288 0.192 432.312 ;
    END
  END tx[267]
  PIN tx[268]
    DIRECTION INPUT ;
    USE SIGNAL ;
    SHAPE ABUTMENT ;
    PORT
      LAYER M4 ;
      RECT 0.000 433.872 0.192 433.896 ;
    END
  END tx[268]
  PIN tx[269]
    DIRECTION INPUT ;
    USE SIGNAL ;
    SHAPE ABUTMENT ;
    PORT
      LAYER M4 ;
      RECT 0.000 435.504 0.192 435.528 ;
    END
  END tx[269]
  PIN tx[270]
    DIRECTION INPUT ;
    USE SIGNAL ;
    SHAPE ABUTMENT ;
    PORT
      LAYER M4 ;
      RECT 0.000 437.136 0.192 437.160 ;
    END
  END tx[270]
  PIN tx[271]
    DIRECTION INPUT ;
    USE SIGNAL ;
    SHAPE ABUTMENT ;
    PORT
      LAYER M4 ;
      RECT 0.000 438.720 0.192 438.744 ;
    END
  END tx[271]
  PIN tx[272]
    DIRECTION INPUT ;
    USE SIGNAL ;
    SHAPE ABUTMENT ;
    PORT
      LAYER M4 ;
      RECT 0.000 440.352 0.192 440.376 ;
    END
  END tx[272]
  PIN tx[273]
    DIRECTION INPUT ;
    USE SIGNAL ;
    SHAPE ABUTMENT ;
    PORT
      LAYER M4 ;
      RECT 0.000 441.936 0.192 441.960 ;
    END
  END tx[273]
  PIN tx[274]
    DIRECTION INPUT ;
    USE SIGNAL ;
    SHAPE ABUTMENT ;
    PORT
      LAYER M4 ;
      RECT 0.000 443.568 0.192 443.592 ;
    END
  END tx[274]
  PIN tx[275]
    DIRECTION INPUT ;
    USE SIGNAL ;
    SHAPE ABUTMENT ;
    PORT
      LAYER M4 ;
      RECT 0.000 445.152 0.192 445.176 ;
    END
  END tx[275]
  PIN tx[276]
    DIRECTION INPUT ;
    USE SIGNAL ;
    SHAPE ABUTMENT ;
    PORT
      LAYER M4 ;
      RECT 0.000 446.784 0.192 446.808 ;
    END
  END tx[276]
  PIN tx[277]
    DIRECTION INPUT ;
    USE SIGNAL ;
    SHAPE ABUTMENT ;
    PORT
      LAYER M4 ;
      RECT 0.000 448.416 0.192 448.440 ;
    END
  END tx[277]
  PIN tx[278]
    DIRECTION INPUT ;
    USE SIGNAL ;
    SHAPE ABUTMENT ;
    PORT
      LAYER M4 ;
      RECT 0.000 450.000 0.192 450.024 ;
    END
  END tx[278]
  PIN tx[279]
    DIRECTION INPUT ;
    USE SIGNAL ;
    SHAPE ABUTMENT ;
    PORT
      LAYER M4 ;
      RECT 0.000 451.632 0.192 451.656 ;
    END
  END tx[279]
  PIN tx[280]
    DIRECTION INPUT ;
    USE SIGNAL ;
    SHAPE ABUTMENT ;
    PORT
      LAYER M4 ;
      RECT 0.000 453.216 0.192 453.240 ;
    END
  END tx[280]
  PIN tx[281]
    DIRECTION INPUT ;
    USE SIGNAL ;
    SHAPE ABUTMENT ;
    PORT
      LAYER M4 ;
      RECT 0.000 454.848 0.192 454.872 ;
    END
  END tx[281]
  PIN tx[282]
    DIRECTION INPUT ;
    USE SIGNAL ;
    SHAPE ABUTMENT ;
    PORT
      LAYER M4 ;
      RECT 0.000 456.432 0.192 456.456 ;
    END
  END tx[282]
  PIN tx[283]
    DIRECTION INPUT ;
    USE SIGNAL ;
    SHAPE ABUTMENT ;
    PORT
      LAYER M4 ;
      RECT 0.000 458.064 0.192 458.088 ;
    END
  END tx[283]
  PIN tx[284]
    DIRECTION INPUT ;
    USE SIGNAL ;
    SHAPE ABUTMENT ;
    PORT
      LAYER M4 ;
      RECT 0.000 459.648 0.192 459.672 ;
    END
  END tx[284]
  PIN tx[285]
    DIRECTION INPUT ;
    USE SIGNAL ;
    SHAPE ABUTMENT ;
    PORT
      LAYER M4 ;
      RECT 0.000 461.280 0.192 461.304 ;
    END
  END tx[285]
  PIN tx[286]
    DIRECTION INPUT ;
    USE SIGNAL ;
    SHAPE ABUTMENT ;
    PORT
      LAYER M4 ;
      RECT 0.000 462.912 0.192 462.936 ;
    END
  END tx[286]
  PIN tx[287]
    DIRECTION INPUT ;
    USE SIGNAL ;
    SHAPE ABUTMENT ;
    PORT
      LAYER M4 ;
      RECT 0.000 464.496 0.192 464.520 ;
    END
  END tx[287]
  PIN tx[288]
    DIRECTION INPUT ;
    USE SIGNAL ;
    SHAPE ABUTMENT ;
    PORT
      LAYER M4 ;
      RECT 0.000 466.128 0.192 466.152 ;
    END
  END tx[288]
  PIN tx[289]
    DIRECTION INPUT ;
    USE SIGNAL ;
    SHAPE ABUTMENT ;
    PORT
      LAYER M4 ;
      RECT 0.000 467.712 0.192 467.736 ;
    END
  END tx[289]
  PIN tx[290]
    DIRECTION INPUT ;
    USE SIGNAL ;
    SHAPE ABUTMENT ;
    PORT
      LAYER M4 ;
      RECT 0.000 469.344 0.192 469.368 ;
    END
  END tx[290]
  PIN tx[291]
    DIRECTION INPUT ;
    USE SIGNAL ;
    SHAPE ABUTMENT ;
    PORT
      LAYER M4 ;
      RECT 0.000 470.928 0.192 470.952 ;
    END
  END tx[291]
  PIN tx[292]
    DIRECTION INPUT ;
    USE SIGNAL ;
    SHAPE ABUTMENT ;
    PORT
      LAYER M4 ;
      RECT 0.000 472.560 0.192 472.584 ;
    END
  END tx[292]
  PIN tx[293]
    DIRECTION INPUT ;
    USE SIGNAL ;
    SHAPE ABUTMENT ;
    PORT
      LAYER M4 ;
      RECT 0.000 474.192 0.192 474.216 ;
    END
  END tx[293]
  PIN tx[294]
    DIRECTION INPUT ;
    USE SIGNAL ;
    SHAPE ABUTMENT ;
    PORT
      LAYER M4 ;
      RECT 0.000 475.776 0.192 475.800 ;
    END
  END tx[294]
  PIN tx[295]
    DIRECTION INPUT ;
    USE SIGNAL ;
    SHAPE ABUTMENT ;
    PORT
      LAYER M4 ;
      RECT 0.000 477.408 0.192 477.432 ;
    END
  END tx[295]
  PIN tx[296]
    DIRECTION INPUT ;
    USE SIGNAL ;
    SHAPE ABUTMENT ;
    PORT
      LAYER M4 ;
      RECT 0.000 478.992 0.192 479.016 ;
    END
  END tx[296]
  PIN tx[297]
    DIRECTION INPUT ;
    USE SIGNAL ;
    SHAPE ABUTMENT ;
    PORT
      LAYER M4 ;
      RECT 0.000 480.624 0.192 480.648 ;
    END
  END tx[297]
  PIN tx[298]
    DIRECTION INPUT ;
    USE SIGNAL ;
    SHAPE ABUTMENT ;
    PORT
      LAYER M4 ;
      RECT 0.000 482.208 0.192 482.232 ;
    END
  END tx[298]
  PIN tx[299]
    DIRECTION INPUT ;
    USE SIGNAL ;
    SHAPE ABUTMENT ;
    PORT
      LAYER M4 ;
      RECT 0.000 483.840 0.192 483.864 ;
    END
  END tx[299]
  PIN tx[300]
    DIRECTION INPUT ;
    USE SIGNAL ;
    SHAPE ABUTMENT ;
    PORT
      LAYER M4 ;
      RECT 0.000 485.472 0.192 485.496 ;
    END
  END tx[300]
  PIN tx[301]
    DIRECTION INPUT ;
    USE SIGNAL ;
    SHAPE ABUTMENT ;
    PORT
      LAYER M4 ;
      RECT 0.000 487.056 0.192 487.080 ;
    END
  END tx[301]
  PIN tx[302]
    DIRECTION INPUT ;
    USE SIGNAL ;
    SHAPE ABUTMENT ;
    PORT
      LAYER M4 ;
      RECT 0.000 488.688 0.192 488.712 ;
    END
  END tx[302]
  PIN tx[303]
    DIRECTION INPUT ;
    USE SIGNAL ;
    SHAPE ABUTMENT ;
    PORT
      LAYER M4 ;
      RECT 0.000 490.272 0.192 490.296 ;
    END
  END tx[303]
  PIN tx[304]
    DIRECTION INPUT ;
    USE SIGNAL ;
    SHAPE ABUTMENT ;
    PORT
      LAYER M4 ;
      RECT 0.000 491.904 0.192 491.928 ;
    END
  END tx[304]
  PIN tx[305]
    DIRECTION INPUT ;
    USE SIGNAL ;
    SHAPE ABUTMENT ;
    PORT
      LAYER M4 ;
      RECT 0.000 493.488 0.192 493.512 ;
    END
  END tx[305]
  PIN tx[306]
    DIRECTION INPUT ;
    USE SIGNAL ;
    SHAPE ABUTMENT ;
    PORT
      LAYER M4 ;
      RECT 0.000 495.120 0.192 495.144 ;
    END
  END tx[306]
  PIN tx[307]
    DIRECTION INPUT ;
    USE SIGNAL ;
    SHAPE ABUTMENT ;
    PORT
      LAYER M4 ;
      RECT 0.000 496.704 0.192 496.728 ;
    END
  END tx[307]
  PIN tx[308]
    DIRECTION INPUT ;
    USE SIGNAL ;
    SHAPE ABUTMENT ;
    PORT
      LAYER M4 ;
      RECT 0.000 498.336 0.192 498.360 ;
    END
  END tx[308]
  PIN tx[309]
    DIRECTION INPUT ;
    USE SIGNAL ;
    SHAPE ABUTMENT ;
    PORT
      LAYER M4 ;
      RECT 0.000 499.968 0.192 499.992 ;
    END
  END tx[309]
  PIN tx[310]
    DIRECTION INPUT ;
    USE SIGNAL ;
    SHAPE ABUTMENT ;
    PORT
      LAYER M4 ;
      RECT 0.000 501.552 0.192 501.576 ;
    END
  END tx[310]
  PIN tx[311]
    DIRECTION INPUT ;
    USE SIGNAL ;
    SHAPE ABUTMENT ;
    PORT
      LAYER M4 ;
      RECT 0.000 503.184 0.192 503.208 ;
    END
  END tx[311]
  PIN tx[312]
    DIRECTION INPUT ;
    USE SIGNAL ;
    SHAPE ABUTMENT ;
    PORT
      LAYER M4 ;
      RECT 0.000 504.768 0.192 504.792 ;
    END
  END tx[312]
  PIN tx[313]
    DIRECTION INPUT ;
    USE SIGNAL ;
    SHAPE ABUTMENT ;
    PORT
      LAYER M4 ;
      RECT 0.000 506.400 0.192 506.424 ;
    END
  END tx[313]
  PIN tx[314]
    DIRECTION INPUT ;
    USE SIGNAL ;
    SHAPE ABUTMENT ;
    PORT
      LAYER M4 ;
      RECT 0.000 507.984 0.192 508.008 ;
    END
  END tx[314]
  PIN tx[315]
    DIRECTION INPUT ;
    USE SIGNAL ;
    SHAPE ABUTMENT ;
    PORT
      LAYER M4 ;
      RECT 0.000 509.616 0.192 509.640 ;
    END
  END tx[315]
  PIN tx[316]
    DIRECTION INPUT ;
    USE SIGNAL ;
    SHAPE ABUTMENT ;
    PORT
      LAYER M4 ;
      RECT 0.000 511.248 0.192 511.272 ;
    END
  END tx[316]
  PIN tx[317]
    DIRECTION INPUT ;
    USE SIGNAL ;
    SHAPE ABUTMENT ;
    PORT
      LAYER M4 ;
      RECT 0.000 512.832 0.192 512.856 ;
    END
  END tx[317]
  PIN tx[318]
    DIRECTION INPUT ;
    USE SIGNAL ;
    SHAPE ABUTMENT ;
    PORT
      LAYER M4 ;
      RECT 0.000 514.464 0.192 514.488 ;
    END
  END tx[318]
  PIN tx[319]
    DIRECTION INPUT ;
    USE SIGNAL ;
    SHAPE ABUTMENT ;
    PORT
      LAYER M4 ;
      RECT 0.000 516.048 0.192 516.072 ;
    END
  END tx[319]
  PIN tx[320]
    DIRECTION INPUT ;
    USE SIGNAL ;
    SHAPE ABUTMENT ;
    PORT
      LAYER M4 ;
      RECT 0.000 517.680 0.192 517.704 ;
    END
  END tx[320]
  PIN tx[321]
    DIRECTION INPUT ;
    USE SIGNAL ;
    SHAPE ABUTMENT ;
    PORT
      LAYER M4 ;
      RECT 0.000 519.264 0.192 519.288 ;
    END
  END tx[321]
  PIN tx[322]
    DIRECTION INPUT ;
    USE SIGNAL ;
    SHAPE ABUTMENT ;
    PORT
      LAYER M4 ;
      RECT 0.000 520.896 0.192 520.920 ;
    END
  END tx[322]
  PIN tx[323]
    DIRECTION INPUT ;
    USE SIGNAL ;
    SHAPE ABUTMENT ;
    PORT
      LAYER M4 ;
      RECT 0.000 522.528 0.192 522.552 ;
    END
  END tx[323]
  PIN tx[324]
    DIRECTION INPUT ;
    USE SIGNAL ;
    SHAPE ABUTMENT ;
    PORT
      LAYER M4 ;
      RECT 0.000 524.112 0.192 524.136 ;
    END
  END tx[324]
  PIN tx[325]
    DIRECTION INPUT ;
    USE SIGNAL ;
    SHAPE ABUTMENT ;
    PORT
      LAYER M4 ;
      RECT 0.000 525.744 0.192 525.768 ;
    END
  END tx[325]
  PIN tx[326]
    DIRECTION INPUT ;
    USE SIGNAL ;
    SHAPE ABUTMENT ;
    PORT
      LAYER M4 ;
      RECT 0.000 527.328 0.192 527.352 ;
    END
  END tx[326]
  PIN tx[327]
    DIRECTION INPUT ;
    USE SIGNAL ;
    SHAPE ABUTMENT ;
    PORT
      LAYER M4 ;
      RECT 0.000 528.960 0.192 528.984 ;
    END
  END tx[327]
  PIN tx[328]
    DIRECTION INPUT ;
    USE SIGNAL ;
    SHAPE ABUTMENT ;
    PORT
      LAYER M4 ;
      RECT 0.000 530.544 0.192 530.568 ;
    END
  END tx[328]
  PIN tx[329]
    DIRECTION INPUT ;
    USE SIGNAL ;
    SHAPE ABUTMENT ;
    PORT
      LAYER M4 ;
      RECT 0.000 532.176 0.192 532.200 ;
    END
  END tx[329]
  PIN tx[330]
    DIRECTION INPUT ;
    USE SIGNAL ;
    SHAPE ABUTMENT ;
    PORT
      LAYER M4 ;
      RECT 0.000 533.760 0.192 533.784 ;
    END
  END tx[330]
  PIN tx[331]
    DIRECTION INPUT ;
    USE SIGNAL ;
    SHAPE ABUTMENT ;
    PORT
      LAYER M4 ;
      RECT 0.000 535.392 0.192 535.416 ;
    END
  END tx[331]
  PIN tx[332]
    DIRECTION INPUT ;
    USE SIGNAL ;
    SHAPE ABUTMENT ;
    PORT
      LAYER M4 ;
      RECT 0.000 537.024 0.192 537.048 ;
    END
  END tx[332]
  PIN tx[333]
    DIRECTION INPUT ;
    USE SIGNAL ;
    SHAPE ABUTMENT ;
    PORT
      LAYER M4 ;
      RECT 0.000 538.608 0.192 538.632 ;
    END
  END tx[333]
  PIN tx[334]
    DIRECTION INPUT ;
    USE SIGNAL ;
    SHAPE ABUTMENT ;
    PORT
      LAYER M4 ;
      RECT 0.000 540.240 0.192 540.264 ;
    END
  END tx[334]
  PIN tx[335]
    DIRECTION INPUT ;
    USE SIGNAL ;
    SHAPE ABUTMENT ;
    PORT
      LAYER M4 ;
      RECT 0.000 541.824 0.192 541.848 ;
    END
  END tx[335]
  PIN tx[336]
    DIRECTION INPUT ;
    USE SIGNAL ;
    SHAPE ABUTMENT ;
    PORT
      LAYER M4 ;
      RECT 0.000 543.456 0.192 543.480 ;
    END
  END tx[336]
  PIN tx[337]
    DIRECTION INPUT ;
    USE SIGNAL ;
    SHAPE ABUTMENT ;
    PORT
      LAYER M4 ;
      RECT 0.000 545.040 0.192 545.064 ;
    END
  END tx[337]
  PIN tx[338]
    DIRECTION INPUT ;
    USE SIGNAL ;
    SHAPE ABUTMENT ;
    PORT
      LAYER M4 ;
      RECT 0.000 546.672 0.192 546.696 ;
    END
  END tx[338]
  PIN tx[339]
    DIRECTION INPUT ;
    USE SIGNAL ;
    SHAPE ABUTMENT ;
    PORT
      LAYER M4 ;
      RECT 0.000 548.304 0.192 548.328 ;
    END
  END tx[339]
  PIN tx[340]
    DIRECTION INPUT ;
    USE SIGNAL ;
    SHAPE ABUTMENT ;
    PORT
      LAYER M4 ;
      RECT 0.000 549.888 0.192 549.912 ;
    END
  END tx[340]
  PIN tx[341]
    DIRECTION INPUT ;
    USE SIGNAL ;
    SHAPE ABUTMENT ;
    PORT
      LAYER M4 ;
      RECT 0.000 551.520 0.192 551.544 ;
    END
  END tx[341]
  PIN tx[342]
    DIRECTION INPUT ;
    USE SIGNAL ;
    SHAPE ABUTMENT ;
    PORT
      LAYER M4 ;
      RECT 0.000 553.104 0.192 553.128 ;
    END
  END tx[342]
  PIN tx[343]
    DIRECTION INPUT ;
    USE SIGNAL ;
    SHAPE ABUTMENT ;
    PORT
      LAYER M4 ;
      RECT 0.000 554.736 0.192 554.760 ;
    END
  END tx[343]
  PIN tx[344]
    DIRECTION INPUT ;
    USE SIGNAL ;
    SHAPE ABUTMENT ;
    PORT
      LAYER M4 ;
      RECT 0.000 556.320 0.192 556.344 ;
    END
  END tx[344]
  PIN tx[345]
    DIRECTION INPUT ;
    USE SIGNAL ;
    SHAPE ABUTMENT ;
    PORT
      LAYER M4 ;
      RECT 0.000 557.952 0.192 557.976 ;
    END
  END tx[345]
  PIN tx[346]
    DIRECTION INPUT ;
    USE SIGNAL ;
    SHAPE ABUTMENT ;
    PORT
      LAYER M4 ;
      RECT 0.000 559.584 0.192 559.608 ;
    END
  END tx[346]
  PIN tx[347]
    DIRECTION INPUT ;
    USE SIGNAL ;
    SHAPE ABUTMENT ;
    PORT
      LAYER M4 ;
      RECT 0.000 561.168 0.192 561.192 ;
    END
  END tx[347]
  PIN tx[348]
    DIRECTION INPUT ;
    USE SIGNAL ;
    SHAPE ABUTMENT ;
    PORT
      LAYER M4 ;
      RECT 0.000 562.800 0.192 562.824 ;
    END
  END tx[348]
  PIN tx[349]
    DIRECTION INPUT ;
    USE SIGNAL ;
    SHAPE ABUTMENT ;
    PORT
      LAYER M4 ;
      RECT 0.000 564.384 0.192 564.408 ;
    END
  END tx[349]
  PIN tx[350]
    DIRECTION INPUT ;
    USE SIGNAL ;
    SHAPE ABUTMENT ;
    PORT
      LAYER M4 ;
      RECT 0.000 566.016 0.192 566.040 ;
    END
  END tx[350]
  PIN tx[351]
    DIRECTION INPUT ;
    USE SIGNAL ;
    SHAPE ABUTMENT ;
    PORT
      LAYER M4 ;
      RECT 0.000 567.600 0.192 567.624 ;
    END
  END tx[351]
  PIN tx[352]
    DIRECTION INPUT ;
    USE SIGNAL ;
    SHAPE ABUTMENT ;
    PORT
      LAYER M4 ;
      RECT 0.000 569.232 0.192 569.256 ;
    END
  END tx[352]
  PIN tx[353]
    DIRECTION INPUT ;
    USE SIGNAL ;
    SHAPE ABUTMENT ;
    PORT
      LAYER M4 ;
      RECT 0.000 570.816 0.192 570.840 ;
    END
  END tx[353]
  PIN tx[354]
    DIRECTION INPUT ;
    USE SIGNAL ;
    SHAPE ABUTMENT ;
    PORT
      LAYER M4 ;
      RECT 0.000 572.448 0.192 572.472 ;
    END
  END tx[354]
  PIN tx[355]
    DIRECTION INPUT ;
    USE SIGNAL ;
    SHAPE ABUTMENT ;
    PORT
      LAYER M4 ;
      RECT 0.000 574.080 0.192 574.104 ;
    END
  END tx[355]
  PIN tx[356]
    DIRECTION INPUT ;
    USE SIGNAL ;
    SHAPE ABUTMENT ;
    PORT
      LAYER M4 ;
      RECT 0.000 575.664 0.192 575.688 ;
    END
  END tx[356]
  PIN tx[357]
    DIRECTION INPUT ;
    USE SIGNAL ;
    SHAPE ABUTMENT ;
    PORT
      LAYER M4 ;
      RECT 0.000 577.296 0.192 577.320 ;
    END
  END tx[357]
  PIN tx[358]
    DIRECTION INPUT ;
    USE SIGNAL ;
    SHAPE ABUTMENT ;
    PORT
      LAYER M4 ;
      RECT 0.000 578.880 0.192 578.904 ;
    END
  END tx[358]
  PIN tx[359]
    DIRECTION INPUT ;
    USE SIGNAL ;
    SHAPE ABUTMENT ;
    PORT
      LAYER M4 ;
      RECT 0.000 580.512 0.192 580.536 ;
    END
  END tx[359]
  PIN tx[360]
    DIRECTION INPUT ;
    USE SIGNAL ;
    SHAPE ABUTMENT ;
    PORT
      LAYER M4 ;
      RECT 0.000 582.096 0.192 582.120 ;
    END
  END tx[360]
  PIN tx[361]
    DIRECTION INPUT ;
    USE SIGNAL ;
    SHAPE ABUTMENT ;
    PORT
      LAYER M4 ;
      RECT 0.000 583.728 0.192 583.752 ;
    END
  END tx[361]
  PIN tx[362]
    DIRECTION INPUT ;
    USE SIGNAL ;
    SHAPE ABUTMENT ;
    PORT
      LAYER M4 ;
      RECT 0.000 585.360 0.192 585.384 ;
    END
  END tx[362]
  PIN tx[363]
    DIRECTION INPUT ;
    USE SIGNAL ;
    SHAPE ABUTMENT ;
    PORT
      LAYER M4 ;
      RECT 0.000 586.944 0.192 586.968 ;
    END
  END tx[363]
  PIN tx[364]
    DIRECTION INPUT ;
    USE SIGNAL ;
    SHAPE ABUTMENT ;
    PORT
      LAYER M4 ;
      RECT 0.000 588.576 0.192 588.600 ;
    END
  END tx[364]
  PIN tx[365]
    DIRECTION INPUT ;
    USE SIGNAL ;
    SHAPE ABUTMENT ;
    PORT
      LAYER M4 ;
      RECT 0.000 590.160 0.192 590.184 ;
    END
  END tx[365]
  PIN tx[366]
    DIRECTION INPUT ;
    USE SIGNAL ;
    SHAPE ABUTMENT ;
    PORT
      LAYER M4 ;
      RECT 0.000 591.792 0.192 591.816 ;
    END
  END tx[366]
  PIN tx[367]
    DIRECTION INPUT ;
    USE SIGNAL ;
    SHAPE ABUTMENT ;
    PORT
      LAYER M4 ;
      RECT 0.000 593.376 0.192 593.400 ;
    END
  END tx[367]
  PIN tx[368]
    DIRECTION INPUT ;
    USE SIGNAL ;
    SHAPE ABUTMENT ;
    PORT
      LAYER M4 ;
      RECT 0.000 595.008 0.192 595.032 ;
    END
  END tx[368]
  PIN tx[369]
    DIRECTION INPUT ;
    USE SIGNAL ;
    SHAPE ABUTMENT ;
    PORT
      LAYER M4 ;
      RECT 0.000 596.640 0.192 596.664 ;
    END
  END tx[369]
  PIN tx[370]
    DIRECTION INPUT ;
    USE SIGNAL ;
    SHAPE ABUTMENT ;
    PORT
      LAYER M4 ;
      RECT 0.000 598.224 0.192 598.248 ;
    END
  END tx[370]
  PIN tx[371]
    DIRECTION INPUT ;
    USE SIGNAL ;
    SHAPE ABUTMENT ;
    PORT
      LAYER M4 ;
      RECT 0.000 599.856 0.192 599.880 ;
    END
  END tx[371]
  PIN tx[372]
    DIRECTION INPUT ;
    USE SIGNAL ;
    SHAPE ABUTMENT ;
    PORT
      LAYER M4 ;
      RECT 0.000 601.440 0.192 601.464 ;
    END
  END tx[372]
  PIN tx[373]
    DIRECTION INPUT ;
    USE SIGNAL ;
    SHAPE ABUTMENT ;
    PORT
      LAYER M4 ;
      RECT 0.000 603.072 0.192 603.096 ;
    END
  END tx[373]
  PIN tx[374]
    DIRECTION INPUT ;
    USE SIGNAL ;
    SHAPE ABUTMENT ;
    PORT
      LAYER M4 ;
      RECT 0.000 604.656 0.192 604.680 ;
    END
  END tx[374]
  PIN tx[375]
    DIRECTION INPUT ;
    USE SIGNAL ;
    SHAPE ABUTMENT ;
    PORT
      LAYER M4 ;
      RECT 0.000 606.288 0.192 606.312 ;
    END
  END tx[375]
  PIN tx[376]
    DIRECTION INPUT ;
    USE SIGNAL ;
    SHAPE ABUTMENT ;
    PORT
      LAYER M4 ;
      RECT 0.000 607.872 0.192 607.896 ;
    END
  END tx[376]
  PIN tx[377]
    DIRECTION INPUT ;
    USE SIGNAL ;
    SHAPE ABUTMENT ;
    PORT
      LAYER M4 ;
      RECT 0.000 609.504 0.192 609.528 ;
    END
  END tx[377]
  PIN tx[378]
    DIRECTION INPUT ;
    USE SIGNAL ;
    SHAPE ABUTMENT ;
    PORT
      LAYER M4 ;
      RECT 0.000 611.136 0.192 611.160 ;
    END
  END tx[378]
  PIN tx[379]
    DIRECTION INPUT ;
    USE SIGNAL ;
    SHAPE ABUTMENT ;
    PORT
      LAYER M4 ;
      RECT 0.000 612.720 0.192 612.744 ;
    END
  END tx[379]
  PIN tx[380]
    DIRECTION INPUT ;
    USE SIGNAL ;
    SHAPE ABUTMENT ;
    PORT
      LAYER M4 ;
      RECT 0.000 614.352 0.192 614.376 ;
    END
  END tx[380]
  PIN tx[381]
    DIRECTION INPUT ;
    USE SIGNAL ;
    SHAPE ABUTMENT ;
    PORT
      LAYER M4 ;
      RECT 0.000 615.936 0.192 615.960 ;
    END
  END tx[381]
  PIN tx[382]
    DIRECTION INPUT ;
    USE SIGNAL ;
    SHAPE ABUTMENT ;
    PORT
      LAYER M4 ;
      RECT 0.000 617.568 0.192 617.592 ;
    END
  END tx[382]
  PIN tx[383]
    DIRECTION INPUT ;
    USE SIGNAL ;
    SHAPE ABUTMENT ;
    PORT
      LAYER M4 ;
      RECT 0.000 619.152 0.192 619.176 ;
    END
  END tx[383]
  PIN tx[384]
    DIRECTION INPUT ;
    USE SIGNAL ;
    SHAPE ABUTMENT ;
    PORT
      LAYER M4 ;
      RECT 0.000 620.784 0.192 620.808 ;
    END
  END tx[384]
  PIN tx[385]
    DIRECTION INPUT ;
    USE SIGNAL ;
    SHAPE ABUTMENT ;
    PORT
      LAYER M4 ;
      RECT 0.000 622.416 0.192 622.440 ;
    END
  END tx[385]
  PIN tx[386]
    DIRECTION INPUT ;
    USE SIGNAL ;
    SHAPE ABUTMENT ;
    PORT
      LAYER M4 ;
      RECT 0.000 624.000 0.192 624.024 ;
    END
  END tx[386]
  PIN tx[387]
    DIRECTION INPUT ;
    USE SIGNAL ;
    SHAPE ABUTMENT ;
    PORT
      LAYER M4 ;
      RECT 0.000 625.632 0.192 625.656 ;
    END
  END tx[387]
  PIN tx[388]
    DIRECTION INPUT ;
    USE SIGNAL ;
    SHAPE ABUTMENT ;
    PORT
      LAYER M4 ;
      RECT 0.000 627.216 0.192 627.240 ;
    END
  END tx[388]
  PIN tx[389]
    DIRECTION INPUT ;
    USE SIGNAL ;
    SHAPE ABUTMENT ;
    PORT
      LAYER M4 ;
      RECT 0.000 628.848 0.192 628.872 ;
    END
  END tx[389]
  PIN tx[390]
    DIRECTION INPUT ;
    USE SIGNAL ;
    SHAPE ABUTMENT ;
    PORT
      LAYER M4 ;
      RECT 0.000 630.432 0.192 630.456 ;
    END
  END tx[390]
  PIN tx[391]
    DIRECTION INPUT ;
    USE SIGNAL ;
    SHAPE ABUTMENT ;
    PORT
      LAYER M4 ;
      RECT 0.000 632.064 0.192 632.088 ;
    END
  END tx[391]
  PIN tx[392]
    DIRECTION INPUT ;
    USE SIGNAL ;
    SHAPE ABUTMENT ;
    PORT
      LAYER M4 ;
      RECT 0.000 633.648 0.192 633.672 ;
    END
  END tx[392]
  PIN tx[393]
    DIRECTION INPUT ;
    USE SIGNAL ;
    SHAPE ABUTMENT ;
    PORT
      LAYER M4 ;
      RECT 0.000 635.280 0.192 635.304 ;
    END
  END tx[393]
  PIN tx[394]
    DIRECTION INPUT ;
    USE SIGNAL ;
    SHAPE ABUTMENT ;
    PORT
      LAYER M4 ;
      RECT 0.000 636.912 0.192 636.936 ;
    END
  END tx[394]
  PIN tx[395]
    DIRECTION INPUT ;
    USE SIGNAL ;
    SHAPE ABUTMENT ;
    PORT
      LAYER M4 ;
      RECT 0.000 638.496 0.192 638.520 ;
    END
  END tx[395]
  PIN tx[396]
    DIRECTION INPUT ;
    USE SIGNAL ;
    SHAPE ABUTMENT ;
    PORT
      LAYER M4 ;
      RECT 0.000 640.128 0.192 640.152 ;
    END
  END tx[396]
  PIN tx[397]
    DIRECTION INPUT ;
    USE SIGNAL ;
    SHAPE ABUTMENT ;
    PORT
      LAYER M4 ;
      RECT 0.000 641.712 0.192 641.736 ;
    END
  END tx[397]
  PIN tx[398]
    DIRECTION INPUT ;
    USE SIGNAL ;
    SHAPE ABUTMENT ;
    PORT
      LAYER M4 ;
      RECT 0.000 643.344 0.192 643.368 ;
    END
  END tx[398]
  PIN tx[399]
    DIRECTION INPUT ;
    USE SIGNAL ;
    SHAPE ABUTMENT ;
    PORT
      LAYER M4 ;
      RECT 0.000 644.928 0.192 644.952 ;
    END
  END tx[399]
  PIN tx[400]
    DIRECTION INPUT ;
    USE SIGNAL ;
    SHAPE ABUTMENT ;
    PORT
      LAYER M4 ;
      RECT 0.000 646.560 0.192 646.584 ;
    END
  END tx[400]
  PIN tx[401]
    DIRECTION INPUT ;
    USE SIGNAL ;
    SHAPE ABUTMENT ;
    PORT
      LAYER M4 ;
      RECT 0.000 648.192 0.192 648.216 ;
    END
  END tx[401]
  PIN tx[402]
    DIRECTION INPUT ;
    USE SIGNAL ;
    SHAPE ABUTMENT ;
    PORT
      LAYER M4 ;
      RECT 0.000 649.776 0.192 649.800 ;
    END
  END tx[402]
  PIN tx[403]
    DIRECTION INPUT ;
    USE SIGNAL ;
    SHAPE ABUTMENT ;
    PORT
      LAYER M4 ;
      RECT 0.000 651.408 0.192 651.432 ;
    END
  END tx[403]
  PIN tx[404]
    DIRECTION INPUT ;
    USE SIGNAL ;
    SHAPE ABUTMENT ;
    PORT
      LAYER M4 ;
      RECT 0.000 652.992 0.192 653.016 ;
    END
  END tx[404]
  PIN tx[405]
    DIRECTION INPUT ;
    USE SIGNAL ;
    SHAPE ABUTMENT ;
    PORT
      LAYER M4 ;
      RECT 0.000 654.624 0.192 654.648 ;
    END
  END tx[405]
  PIN tx[406]
    DIRECTION INPUT ;
    USE SIGNAL ;
    SHAPE ABUTMENT ;
    PORT
      LAYER M4 ;
      RECT 0.000 656.208 0.192 656.232 ;
    END
  END tx[406]
  PIN tx[407]
    DIRECTION INPUT ;
    USE SIGNAL ;
    SHAPE ABUTMENT ;
    PORT
      LAYER M4 ;
      RECT 0.000 657.840 0.192 657.864 ;
    END
  END tx[407]
  PIN tx[408]
    DIRECTION INPUT ;
    USE SIGNAL ;
    SHAPE ABUTMENT ;
    PORT
      LAYER M4 ;
      RECT 0.000 659.472 0.192 659.496 ;
    END
  END tx[408]
  PIN tx[409]
    DIRECTION INPUT ;
    USE SIGNAL ;
    SHAPE ABUTMENT ;
    PORT
      LAYER M4 ;
      RECT 0.000 661.056 0.192 661.080 ;
    END
  END tx[409]
  PIN tx[410]
    DIRECTION INPUT ;
    USE SIGNAL ;
    SHAPE ABUTMENT ;
    PORT
      LAYER M4 ;
      RECT 0.000 662.688 0.192 662.712 ;
    END
  END tx[410]
  PIN tx[411]
    DIRECTION INPUT ;
    USE SIGNAL ;
    SHAPE ABUTMENT ;
    PORT
      LAYER M4 ;
      RECT 0.000 664.272 0.192 664.296 ;
    END
  END tx[411]
  PIN tx[412]
    DIRECTION INPUT ;
    USE SIGNAL ;
    SHAPE ABUTMENT ;
    PORT
      LAYER M4 ;
      RECT 0.000 665.904 0.192 665.928 ;
    END
  END tx[412]
  PIN tx[413]
    DIRECTION INPUT ;
    USE SIGNAL ;
    SHAPE ABUTMENT ;
    PORT
      LAYER M4 ;
      RECT 0.000 667.488 0.192 667.512 ;
    END
  END tx[413]
  PIN tx[414]
    DIRECTION INPUT ;
    USE SIGNAL ;
    SHAPE ABUTMENT ;
    PORT
      LAYER M4 ;
      RECT 0.000 669.120 0.192 669.144 ;
    END
  END tx[414]
  PIN tx[415]
    DIRECTION INPUT ;
    USE SIGNAL ;
    SHAPE ABUTMENT ;
    PORT
      LAYER M4 ;
      RECT 0.000 670.704 0.192 670.728 ;
    END
  END tx[415]
  PIN tx[416]
    DIRECTION INPUT ;
    USE SIGNAL ;
    SHAPE ABUTMENT ;
    PORT
      LAYER M4 ;
      RECT 0.000 672.336 0.192 672.360 ;
    END
  END tx[416]
  PIN tx[417]
    DIRECTION INPUT ;
    USE SIGNAL ;
    SHAPE ABUTMENT ;
    PORT
      LAYER M4 ;
      RECT 0.000 673.968 0.192 673.992 ;
    END
  END tx[417]
  PIN tx[418]
    DIRECTION INPUT ;
    USE SIGNAL ;
    SHAPE ABUTMENT ;
    PORT
      LAYER M4 ;
      RECT 0.000 675.552 0.192 675.576 ;
    END
  END tx[418]
  PIN tx[419]
    DIRECTION INPUT ;
    USE SIGNAL ;
    SHAPE ABUTMENT ;
    PORT
      LAYER M4 ;
      RECT 0.000 677.184 0.192 677.208 ;
    END
  END tx[419]
  PIN tx[420]
    DIRECTION INPUT ;
    USE SIGNAL ;
    SHAPE ABUTMENT ;
    PORT
      LAYER M4 ;
      RECT 0.000 678.768 0.192 678.792 ;
    END
  END tx[420]
  PIN tx[421]
    DIRECTION INPUT ;
    USE SIGNAL ;
    SHAPE ABUTMENT ;
    PORT
      LAYER M4 ;
      RECT 0.000 680.400 0.192 680.424 ;
    END
  END tx[421]
  PIN tx[422]
    DIRECTION INPUT ;
    USE SIGNAL ;
    SHAPE ABUTMENT ;
    PORT
      LAYER M4 ;
      RECT 0.000 681.984 0.192 682.008 ;
    END
  END tx[422]
  PIN tx[423]
    DIRECTION INPUT ;
    USE SIGNAL ;
    SHAPE ABUTMENT ;
    PORT
      LAYER M4 ;
      RECT 0.000 683.616 0.192 683.640 ;
    END
  END tx[423]
  PIN tx[424]
    DIRECTION INPUT ;
    USE SIGNAL ;
    SHAPE ABUTMENT ;
    PORT
      LAYER M4 ;
      RECT 0.000 685.248 0.192 685.272 ;
    END
  END tx[424]
  PIN tx[425]
    DIRECTION INPUT ;
    USE SIGNAL ;
    SHAPE ABUTMENT ;
    PORT
      LAYER M4 ;
      RECT 0.000 686.832 0.192 686.856 ;
    END
  END tx[425]
  PIN tx[426]
    DIRECTION INPUT ;
    USE SIGNAL ;
    SHAPE ABUTMENT ;
    PORT
      LAYER M4 ;
      RECT 0.000 688.464 0.192 688.488 ;
    END
  END tx[426]
  PIN tx[427]
    DIRECTION INPUT ;
    USE SIGNAL ;
    SHAPE ABUTMENT ;
    PORT
      LAYER M4 ;
      RECT 0.000 690.048 0.192 690.072 ;
    END
  END tx[427]
  PIN tx[428]
    DIRECTION INPUT ;
    USE SIGNAL ;
    SHAPE ABUTMENT ;
    PORT
      LAYER M4 ;
      RECT 0.000 691.680 0.192 691.704 ;
    END
  END tx[428]
  PIN tx[429]
    DIRECTION INPUT ;
    USE SIGNAL ;
    SHAPE ABUTMENT ;
    PORT
      LAYER M4 ;
      RECT 0.000 693.264 0.192 693.288 ;
    END
  END tx[429]
  PIN tx[430]
    DIRECTION INPUT ;
    USE SIGNAL ;
    SHAPE ABUTMENT ;
    PORT
      LAYER M4 ;
      RECT 0.000 694.896 0.192 694.920 ;
    END
  END tx[430]
  PIN tx[431]
    DIRECTION INPUT ;
    USE SIGNAL ;
    SHAPE ABUTMENT ;
    PORT
      LAYER M4 ;
      RECT 0.000 696.528 0.192 696.552 ;
    END
  END tx[431]
  PIN tx[432]
    DIRECTION INPUT ;
    USE SIGNAL ;
    SHAPE ABUTMENT ;
    PORT
      LAYER M4 ;
      RECT 0.000 698.112 0.192 698.136 ;
    END
  END tx[432]
  PIN tx[433]
    DIRECTION INPUT ;
    USE SIGNAL ;
    SHAPE ABUTMENT ;
    PORT
      LAYER M4 ;
      RECT 0.000 699.744 0.192 699.768 ;
    END
  END tx[433]
  PIN tx[434]
    DIRECTION INPUT ;
    USE SIGNAL ;
    SHAPE ABUTMENT ;
    PORT
      LAYER M4 ;
      RECT 0.000 701.328 0.192 701.352 ;
    END
  END tx[434]
  PIN tx[435]
    DIRECTION INPUT ;
    USE SIGNAL ;
    SHAPE ABUTMENT ;
    PORT
      LAYER M4 ;
      RECT 0.000 702.960 0.192 702.984 ;
    END
  END tx[435]
  PIN tx[436]
    DIRECTION INPUT ;
    USE SIGNAL ;
    SHAPE ABUTMENT ;
    PORT
      LAYER M4 ;
      RECT 0.000 704.544 0.192 704.568 ;
    END
  END tx[436]
  PIN tx[437]
    DIRECTION INPUT ;
    USE SIGNAL ;
    SHAPE ABUTMENT ;
    PORT
      LAYER M4 ;
      RECT 0.000 706.176 0.192 706.200 ;
    END
  END tx[437]
  PIN tx[438]
    DIRECTION INPUT ;
    USE SIGNAL ;
    SHAPE ABUTMENT ;
    PORT
      LAYER M4 ;
      RECT 0.000 707.760 0.192 707.784 ;
    END
  END tx[438]
  PIN tx[439]
    DIRECTION INPUT ;
    USE SIGNAL ;
    SHAPE ABUTMENT ;
    PORT
      LAYER M4 ;
      RECT 0.000 709.392 0.192 709.416 ;
    END
  END tx[439]
  PIN tx[440]
    DIRECTION INPUT ;
    USE SIGNAL ;
    SHAPE ABUTMENT ;
    PORT
      LAYER M4 ;
      RECT 0.000 711.024 0.192 711.048 ;
    END
  END tx[440]
  PIN tx[441]
    DIRECTION INPUT ;
    USE SIGNAL ;
    SHAPE ABUTMENT ;
    PORT
      LAYER M4 ;
      RECT 0.000 712.608 0.192 712.632 ;
    END
  END tx[441]
  PIN tx[442]
    DIRECTION INPUT ;
    USE SIGNAL ;
    SHAPE ABUTMENT ;
    PORT
      LAYER M4 ;
      RECT 0.000 714.240 0.192 714.264 ;
    END
  END tx[442]
  PIN tx[443]
    DIRECTION INPUT ;
    USE SIGNAL ;
    SHAPE ABUTMENT ;
    PORT
      LAYER M4 ;
      RECT 0.000 715.824 0.192 715.848 ;
    END
  END tx[443]
  PIN tx[444]
    DIRECTION INPUT ;
    USE SIGNAL ;
    SHAPE ABUTMENT ;
    PORT
      LAYER M4 ;
      RECT 0.000 717.456 0.192 717.480 ;
    END
  END tx[444]
  PIN tx[445]
    DIRECTION INPUT ;
    USE SIGNAL ;
    SHAPE ABUTMENT ;
    PORT
      LAYER M4 ;
      RECT 0.000 719.040 0.192 719.064 ;
    END
  END tx[445]
  PIN tx[446]
    DIRECTION INPUT ;
    USE SIGNAL ;
    SHAPE ABUTMENT ;
    PORT
      LAYER M4 ;
      RECT 0.000 720.672 0.192 720.696 ;
    END
  END tx[446]
  PIN tx[447]
    DIRECTION INPUT ;
    USE SIGNAL ;
    SHAPE ABUTMENT ;
    PORT
      LAYER M4 ;
      RECT 0.000 722.304 0.192 722.328 ;
    END
  END tx[447]
  PIN tx[448]
    DIRECTION INPUT ;
    USE SIGNAL ;
    SHAPE ABUTMENT ;
    PORT
      LAYER M4 ;
      RECT 0.000 723.888 0.192 723.912 ;
    END
  END tx[448]
  PIN tx[449]
    DIRECTION INPUT ;
    USE SIGNAL ;
    SHAPE ABUTMENT ;
    PORT
      LAYER M4 ;
      RECT 0.000 725.520 0.192 725.544 ;
    END
  END tx[449]
  PIN tx[450]
    DIRECTION INPUT ;
    USE SIGNAL ;
    SHAPE ABUTMENT ;
    PORT
      LAYER M4 ;
      RECT 0.000 727.104 0.192 727.128 ;
    END
  END tx[450]
  PIN tx[451]
    DIRECTION INPUT ;
    USE SIGNAL ;
    SHAPE ABUTMENT ;
    PORT
      LAYER M4 ;
      RECT 0.000 728.736 0.192 728.760 ;
    END
  END tx[451]
  PIN tx[452]
    DIRECTION INPUT ;
    USE SIGNAL ;
    SHAPE ABUTMENT ;
    PORT
      LAYER M4 ;
      RECT 0.000 730.320 0.192 730.344 ;
    END
  END tx[452]
  PIN tx[453]
    DIRECTION INPUT ;
    USE SIGNAL ;
    SHAPE ABUTMENT ;
    PORT
      LAYER M4 ;
      RECT 0.000 731.952 0.192 731.976 ;
    END
  END tx[453]
  PIN tx[454]
    DIRECTION INPUT ;
    USE SIGNAL ;
    SHAPE ABUTMENT ;
    PORT
      LAYER M4 ;
      RECT 0.000 733.584 0.192 733.608 ;
    END
  END tx[454]
  PIN tx[455]
    DIRECTION INPUT ;
    USE SIGNAL ;
    SHAPE ABUTMENT ;
    PORT
      LAYER M4 ;
      RECT 0.000 735.168 0.192 735.192 ;
    END
  END tx[455]
  PIN tx[456]
    DIRECTION INPUT ;
    USE SIGNAL ;
    SHAPE ABUTMENT ;
    PORT
      LAYER M4 ;
      RECT 0.000 736.800 0.192 736.824 ;
    END
  END tx[456]
  PIN tx[457]
    DIRECTION INPUT ;
    USE SIGNAL ;
    SHAPE ABUTMENT ;
    PORT
      LAYER M4 ;
      RECT 0.000 738.384 0.192 738.408 ;
    END
  END tx[457]
  PIN tx[458]
    DIRECTION INPUT ;
    USE SIGNAL ;
    SHAPE ABUTMENT ;
    PORT
      LAYER M4 ;
      RECT 0.000 740.016 0.192 740.040 ;
    END
  END tx[458]
  PIN tx[459]
    DIRECTION INPUT ;
    USE SIGNAL ;
    SHAPE ABUTMENT ;
    PORT
      LAYER M4 ;
      RECT 0.000 741.600 0.192 741.624 ;
    END
  END tx[459]
  PIN tx[460]
    DIRECTION INPUT ;
    USE SIGNAL ;
    SHAPE ABUTMENT ;
    PORT
      LAYER M4 ;
      RECT 0.000 743.232 0.192 743.256 ;
    END
  END tx[460]
  PIN tx[461]
    DIRECTION INPUT ;
    USE SIGNAL ;
    SHAPE ABUTMENT ;
    PORT
      LAYER M4 ;
      RECT 0.000 744.816 0.192 744.840 ;
    END
  END tx[461]
  PIN tx[462]
    DIRECTION INPUT ;
    USE SIGNAL ;
    SHAPE ABUTMENT ;
    PORT
      LAYER M4 ;
      RECT 0.000 746.448 0.192 746.472 ;
    END
  END tx[462]
  PIN tx[463]
    DIRECTION INPUT ;
    USE SIGNAL ;
    SHAPE ABUTMENT ;
    PORT
      LAYER M4 ;
      RECT 0.000 748.080 0.192 748.104 ;
    END
  END tx[463]
  PIN tx[464]
    DIRECTION INPUT ;
    USE SIGNAL ;
    SHAPE ABUTMENT ;
    PORT
      LAYER M4 ;
      RECT 0.000 749.664 0.192 749.688 ;
    END
  END tx[464]
  PIN tx[465]
    DIRECTION INPUT ;
    USE SIGNAL ;
    SHAPE ABUTMENT ;
    PORT
      LAYER M4 ;
      RECT 0.000 751.296 0.192 751.320 ;
    END
  END tx[465]
  PIN tx[466]
    DIRECTION INPUT ;
    USE SIGNAL ;
    SHAPE ABUTMENT ;
    PORT
      LAYER M4 ;
      RECT 0.000 752.880 0.192 752.904 ;
    END
  END tx[466]
  PIN tx[467]
    DIRECTION INPUT ;
    USE SIGNAL ;
    SHAPE ABUTMENT ;
    PORT
      LAYER M4 ;
      RECT 0.000 754.512 0.192 754.536 ;
    END
  END tx[467]
  PIN tx[468]
    DIRECTION INPUT ;
    USE SIGNAL ;
    SHAPE ABUTMENT ;
    PORT
      LAYER M4 ;
      RECT 0.000 756.096 0.192 756.120 ;
    END
  END tx[468]
  PIN tx[469]
    DIRECTION INPUT ;
    USE SIGNAL ;
    SHAPE ABUTMENT ;
    PORT
      LAYER M4 ;
      RECT 0.000 757.728 0.192 757.752 ;
    END
  END tx[469]
  PIN tx[470]
    DIRECTION INPUT ;
    USE SIGNAL ;
    SHAPE ABUTMENT ;
    PORT
      LAYER M4 ;
      RECT 0.000 759.360 0.192 759.384 ;
    END
  END tx[470]
  PIN tx[471]
    DIRECTION INPUT ;
    USE SIGNAL ;
    SHAPE ABUTMENT ;
    PORT
      LAYER M4 ;
      RECT 0.000 760.944 0.192 760.968 ;
    END
  END tx[471]
  PIN tx[472]
    DIRECTION INPUT ;
    USE SIGNAL ;
    SHAPE ABUTMENT ;
    PORT
      LAYER M4 ;
      RECT 0.000 762.576 0.192 762.600 ;
    END
  END tx[472]
  PIN tx[473]
    DIRECTION INPUT ;
    USE SIGNAL ;
    SHAPE ABUTMENT ;
    PORT
      LAYER M4 ;
      RECT 0.000 764.160 0.192 764.184 ;
    END
  END tx[473]
  PIN tx[474]
    DIRECTION INPUT ;
    USE SIGNAL ;
    SHAPE ABUTMENT ;
    PORT
      LAYER M4 ;
      RECT 0.000 765.792 0.192 765.816 ;
    END
  END tx[474]
  PIN tx[475]
    DIRECTION INPUT ;
    USE SIGNAL ;
    SHAPE ABUTMENT ;
    PORT
      LAYER M4 ;
      RECT 0.000 767.376 0.192 767.400 ;
    END
  END tx[475]
  PIN tx[476]
    DIRECTION INPUT ;
    USE SIGNAL ;
    SHAPE ABUTMENT ;
    PORT
      LAYER M4 ;
      RECT 0.000 769.008 0.192 769.032 ;
    END
  END tx[476]
  PIN tx[477]
    DIRECTION INPUT ;
    USE SIGNAL ;
    SHAPE ABUTMENT ;
    PORT
      LAYER M4 ;
      RECT 0.000 770.640 0.192 770.664 ;
    END
  END tx[477]
  PIN tx[478]
    DIRECTION INPUT ;
    USE SIGNAL ;
    SHAPE ABUTMENT ;
    PORT
      LAYER M4 ;
      RECT 0.000 772.224 0.192 772.248 ;
    END
  END tx[478]
  PIN tx[479]
    DIRECTION INPUT ;
    USE SIGNAL ;
    SHAPE ABUTMENT ;
    PORT
      LAYER M4 ;
      RECT 0.000 773.856 0.192 773.880 ;
    END
  END tx[479]
  PIN tx[480]
    DIRECTION INPUT ;
    USE SIGNAL ;
    SHAPE ABUTMENT ;
    PORT
      LAYER M4 ;
      RECT 0.000 775.440 0.192 775.464 ;
    END
  END tx[480]
  PIN tx[481]
    DIRECTION INPUT ;
    USE SIGNAL ;
    SHAPE ABUTMENT ;
    PORT
      LAYER M4 ;
      RECT 0.000 777.072 0.192 777.096 ;
    END
  END tx[481]
  PIN tx[482]
    DIRECTION INPUT ;
    USE SIGNAL ;
    SHAPE ABUTMENT ;
    PORT
      LAYER M4 ;
      RECT 0.000 778.656 0.192 778.680 ;
    END
  END tx[482]
  PIN tx[483]
    DIRECTION INPUT ;
    USE SIGNAL ;
    SHAPE ABUTMENT ;
    PORT
      LAYER M4 ;
      RECT 0.000 780.288 0.192 780.312 ;
    END
  END tx[483]
  PIN tx[484]
    DIRECTION INPUT ;
    USE SIGNAL ;
    SHAPE ABUTMENT ;
    PORT
      LAYER M4 ;
      RECT 0.000 781.872 0.192 781.896 ;
    END
  END tx[484]
  PIN tx[485]
    DIRECTION INPUT ;
    USE SIGNAL ;
    SHAPE ABUTMENT ;
    PORT
      LAYER M4 ;
      RECT 0.000 783.504 0.192 783.528 ;
    END
  END tx[485]
  PIN tx[486]
    DIRECTION INPUT ;
    USE SIGNAL ;
    SHAPE ABUTMENT ;
    PORT
      LAYER M4 ;
      RECT 0.000 785.136 0.192 785.160 ;
    END
  END tx[486]
  PIN tx[487]
    DIRECTION INPUT ;
    USE SIGNAL ;
    SHAPE ABUTMENT ;
    PORT
      LAYER M4 ;
      RECT 0.000 786.720 0.192 786.744 ;
    END
  END tx[487]
  PIN tx[488]
    DIRECTION INPUT ;
    USE SIGNAL ;
    SHAPE ABUTMENT ;
    PORT
      LAYER M4 ;
      RECT 0.000 788.352 0.192 788.376 ;
    END
  END tx[488]
  PIN tx[489]
    DIRECTION INPUT ;
    USE SIGNAL ;
    SHAPE ABUTMENT ;
    PORT
      LAYER M4 ;
      RECT 0.000 789.936 0.192 789.960 ;
    END
  END tx[489]
  PIN tx[490]
    DIRECTION INPUT ;
    USE SIGNAL ;
    SHAPE ABUTMENT ;
    PORT
      LAYER M4 ;
      RECT 0.000 791.568 0.192 791.592 ;
    END
  END tx[490]
  PIN tx[491]
    DIRECTION INPUT ;
    USE SIGNAL ;
    SHAPE ABUTMENT ;
    PORT
      LAYER M4 ;
      RECT 0.000 793.152 0.192 793.176 ;
    END
  END tx[491]
  PIN tx[492]
    DIRECTION INPUT ;
    USE SIGNAL ;
    SHAPE ABUTMENT ;
    PORT
      LAYER M4 ;
      RECT 0.000 794.784 0.192 794.808 ;
    END
  END tx[492]
  PIN tx[493]
    DIRECTION INPUT ;
    USE SIGNAL ;
    SHAPE ABUTMENT ;
    PORT
      LAYER M4 ;
      RECT 0.000 796.416 0.192 796.440 ;
    END
  END tx[493]
  PIN tx[494]
    DIRECTION INPUT ;
    USE SIGNAL ;
    SHAPE ABUTMENT ;
    PORT
      LAYER M4 ;
      RECT 0.000 798.000 0.192 798.024 ;
    END
  END tx[494]
  PIN tx[495]
    DIRECTION INPUT ;
    USE SIGNAL ;
    SHAPE ABUTMENT ;
    PORT
      LAYER M4 ;
      RECT 0.000 799.632 0.192 799.656 ;
    END
  END tx[495]
  PIN tx[496]
    DIRECTION INPUT ;
    USE SIGNAL ;
    SHAPE ABUTMENT ;
    PORT
      LAYER M4 ;
      RECT 0.000 801.216 0.192 801.240 ;
    END
  END tx[496]
  PIN tx[497]
    DIRECTION INPUT ;
    USE SIGNAL ;
    SHAPE ABUTMENT ;
    PORT
      LAYER M4 ;
      RECT 0.000 802.848 0.192 802.872 ;
    END
  END tx[497]
  PIN tx[498]
    DIRECTION INPUT ;
    USE SIGNAL ;
    SHAPE ABUTMENT ;
    PORT
      LAYER M4 ;
      RECT 0.000 804.432 0.192 804.456 ;
    END
  END tx[498]
  PIN tx[499]
    DIRECTION INPUT ;
    USE SIGNAL ;
    SHAPE ABUTMENT ;
    PORT
      LAYER M4 ;
      RECT 0.000 806.064 0.192 806.088 ;
    END
  END tx[499]
  PIN tx[500]
    DIRECTION INPUT ;
    USE SIGNAL ;
    SHAPE ABUTMENT ;
    PORT
      LAYER M4 ;
      RECT 0.000 807.696 0.192 807.720 ;
    END
  END tx[500]
  PIN tx[501]
    DIRECTION INPUT ;
    USE SIGNAL ;
    SHAPE ABUTMENT ;
    PORT
      LAYER M4 ;
      RECT 0.000 809.280 0.192 809.304 ;
    END
  END tx[501]
  PIN tx[502]
    DIRECTION INPUT ;
    USE SIGNAL ;
    SHAPE ABUTMENT ;
    PORT
      LAYER M4 ;
      RECT 0.000 810.912 0.192 810.936 ;
    END
  END tx[502]
  PIN tx[503]
    DIRECTION INPUT ;
    USE SIGNAL ;
    SHAPE ABUTMENT ;
    PORT
      LAYER M4 ;
      RECT 0.000 812.496 0.192 812.520 ;
    END
  END tx[503]
  PIN tx[504]
    DIRECTION INPUT ;
    USE SIGNAL ;
    SHAPE ABUTMENT ;
    PORT
      LAYER M4 ;
      RECT 0.000 814.128 0.192 814.152 ;
    END
  END tx[504]
  PIN tx[505]
    DIRECTION INPUT ;
    USE SIGNAL ;
    SHAPE ABUTMENT ;
    PORT
      LAYER M4 ;
      RECT 0.000 815.712 0.192 815.736 ;
    END
  END tx[505]
  PIN tx[506]
    DIRECTION INPUT ;
    USE SIGNAL ;
    SHAPE ABUTMENT ;
    PORT
      LAYER M4 ;
      RECT 0.000 817.344 0.192 817.368 ;
    END
  END tx[506]
  PIN tx[507]
    DIRECTION INPUT ;
    USE SIGNAL ;
    SHAPE ABUTMENT ;
    PORT
      LAYER M4 ;
      RECT 0.000 818.928 0.192 818.952 ;
    END
  END tx[507]
  PIN tx[508]
    DIRECTION INPUT ;
    USE SIGNAL ;
    SHAPE ABUTMENT ;
    PORT
      LAYER M4 ;
      RECT 0.000 820.560 0.192 820.584 ;
    END
  END tx[508]
  PIN tx[509]
    DIRECTION INPUT ;
    USE SIGNAL ;
    SHAPE ABUTMENT ;
    PORT
      LAYER M4 ;
      RECT 0.000 822.192 0.192 822.216 ;
    END
  END tx[509]
  PIN tx[510]
    DIRECTION INPUT ;
    USE SIGNAL ;
    SHAPE ABUTMENT ;
    PORT
      LAYER M4 ;
      RECT 0.000 823.776 0.192 823.800 ;
    END
  END tx[510]
  PIN tx[511]
    DIRECTION INPUT ;
    USE SIGNAL ;
    SHAPE ABUTMENT ;
    PORT
      LAYER M4 ;
      RECT 0.000 825.408 0.192 825.432 ;
    END
  END tx[511]
  PIN rx[0]
    DIRECTION OUTPUT ;
    USE SIGNAL ;
    SHAPE ABUTMENT ;
    PORT
      LAYER M4 ;
      RECT 0.000 826.992 0.192 827.016 ;
    END
  END rx[0]
  PIN rx[1]
    DIRECTION OUTPUT ;
    USE SIGNAL ;
    SHAPE ABUTMENT ;
    PORT
      LAYER M4 ;
      RECT 0.000 828.624 0.192 828.648 ;
    END
  END rx[1]
  PIN rx[2]
    DIRECTION OUTPUT ;
    USE SIGNAL ;
    SHAPE ABUTMENT ;
    PORT
      LAYER M4 ;
      RECT 0.000 830.208 0.192 830.232 ;
    END
  END rx[2]
  PIN rx[3]
    DIRECTION OUTPUT ;
    USE SIGNAL ;
    SHAPE ABUTMENT ;
    PORT
      LAYER M4 ;
      RECT 0.000 831.840 0.192 831.864 ;
    END
  END rx[3]
  PIN rx[4]
    DIRECTION OUTPUT ;
    USE SIGNAL ;
    SHAPE ABUTMENT ;
    PORT
      LAYER M4 ;
      RECT 0.000 833.472 0.192 833.496 ;
    END
  END rx[4]
  PIN rx[5]
    DIRECTION OUTPUT ;
    USE SIGNAL ;
    SHAPE ABUTMENT ;
    PORT
      LAYER M4 ;
      RECT 0.000 835.056 0.192 835.080 ;
    END
  END rx[5]
  PIN rx[6]
    DIRECTION OUTPUT ;
    USE SIGNAL ;
    SHAPE ABUTMENT ;
    PORT
      LAYER M4 ;
      RECT 0.000 836.688 0.192 836.712 ;
    END
  END rx[6]
  PIN rx[7]
    DIRECTION OUTPUT ;
    USE SIGNAL ;
    SHAPE ABUTMENT ;
    PORT
      LAYER M4 ;
      RECT 0.000 838.272 0.192 838.296 ;
    END
  END rx[7]
  PIN rx[8]
    DIRECTION OUTPUT ;
    USE SIGNAL ;
    SHAPE ABUTMENT ;
    PORT
      LAYER M4 ;
      RECT 0.000 839.904 0.192 839.928 ;
    END
  END rx[8]
  PIN rx[9]
    DIRECTION OUTPUT ;
    USE SIGNAL ;
    SHAPE ABUTMENT ;
    PORT
      LAYER M4 ;
      RECT 0.000 841.488 0.192 841.512 ;
    END
  END rx[9]
  PIN rx[10]
    DIRECTION OUTPUT ;
    USE SIGNAL ;
    SHAPE ABUTMENT ;
    PORT
      LAYER M4 ;
      RECT 0.000 843.120 0.192 843.144 ;
    END
  END rx[10]
  PIN rx[11]
    DIRECTION OUTPUT ;
    USE SIGNAL ;
    SHAPE ABUTMENT ;
    PORT
      LAYER M4 ;
      RECT 0.000 844.704 0.192 844.728 ;
    END
  END rx[11]
  PIN rx[12]
    DIRECTION OUTPUT ;
    USE SIGNAL ;
    SHAPE ABUTMENT ;
    PORT
      LAYER M4 ;
      RECT 0.000 846.336 0.192 846.360 ;
    END
  END rx[12]
  PIN rx[13]
    DIRECTION OUTPUT ;
    USE SIGNAL ;
    SHAPE ABUTMENT ;
    PORT
      LAYER M4 ;
      RECT 0.000 847.968 0.192 847.992 ;
    END
  END rx[13]
  PIN rx[14]
    DIRECTION OUTPUT ;
    USE SIGNAL ;
    SHAPE ABUTMENT ;
    PORT
      LAYER M4 ;
      RECT 0.000 849.552 0.192 849.576 ;
    END
  END rx[14]
  PIN rx[15]
    DIRECTION OUTPUT ;
    USE SIGNAL ;
    SHAPE ABUTMENT ;
    PORT
      LAYER M4 ;
      RECT 0.000 851.184 0.192 851.208 ;
    END
  END rx[15]
  PIN rx[16]
    DIRECTION OUTPUT ;
    USE SIGNAL ;
    SHAPE ABUTMENT ;
    PORT
      LAYER M4 ;
      RECT 0.000 852.768 0.192 852.792 ;
    END
  END rx[16]
  PIN rx[17]
    DIRECTION OUTPUT ;
    USE SIGNAL ;
    SHAPE ABUTMENT ;
    PORT
      LAYER M4 ;
      RECT 0.000 854.400 0.192 854.424 ;
    END
  END rx[17]
  PIN rx[18]
    DIRECTION OUTPUT ;
    USE SIGNAL ;
    SHAPE ABUTMENT ;
    PORT
      LAYER M4 ;
      RECT 0.000 855.984 0.192 856.008 ;
    END
  END rx[18]
  PIN rx[19]
    DIRECTION OUTPUT ;
    USE SIGNAL ;
    SHAPE ABUTMENT ;
    PORT
      LAYER M4 ;
      RECT 0.000 857.616 0.192 857.640 ;
    END
  END rx[19]
  PIN rx[20]
    DIRECTION OUTPUT ;
    USE SIGNAL ;
    SHAPE ABUTMENT ;
    PORT
      LAYER M4 ;
      RECT 0.000 859.248 0.192 859.272 ;
    END
  END rx[20]
  PIN rx[21]
    DIRECTION OUTPUT ;
    USE SIGNAL ;
    SHAPE ABUTMENT ;
    PORT
      LAYER M4 ;
      RECT 0.000 860.832 0.192 860.856 ;
    END
  END rx[21]
  PIN rx[22]
    DIRECTION OUTPUT ;
    USE SIGNAL ;
    SHAPE ABUTMENT ;
    PORT
      LAYER M4 ;
      RECT 0.000 862.464 0.192 862.488 ;
    END
  END rx[22]
  PIN rx[23]
    DIRECTION OUTPUT ;
    USE SIGNAL ;
    SHAPE ABUTMENT ;
    PORT
      LAYER M4 ;
      RECT 0.000 864.048 0.192 864.072 ;
    END
  END rx[23]
  PIN rx[24]
    DIRECTION OUTPUT ;
    USE SIGNAL ;
    SHAPE ABUTMENT ;
    PORT
      LAYER M4 ;
      RECT 0.000 865.680 0.192 865.704 ;
    END
  END rx[24]
  PIN rx[25]
    DIRECTION OUTPUT ;
    USE SIGNAL ;
    SHAPE ABUTMENT ;
    PORT
      LAYER M4 ;
      RECT 0.000 867.264 0.192 867.288 ;
    END
  END rx[25]
  PIN rx[26]
    DIRECTION OUTPUT ;
    USE SIGNAL ;
    SHAPE ABUTMENT ;
    PORT
      LAYER M4 ;
      RECT 0.000 868.896 0.192 868.920 ;
    END
  END rx[26]
  PIN rx[27]
    DIRECTION OUTPUT ;
    USE SIGNAL ;
    SHAPE ABUTMENT ;
    PORT
      LAYER M4 ;
      RECT 0.000 870.528 0.192 870.552 ;
    END
  END rx[27]
  PIN rx[28]
    DIRECTION OUTPUT ;
    USE SIGNAL ;
    SHAPE ABUTMENT ;
    PORT
      LAYER M4 ;
      RECT 0.000 872.112 0.192 872.136 ;
    END
  END rx[28]
  PIN rx[29]
    DIRECTION OUTPUT ;
    USE SIGNAL ;
    SHAPE ABUTMENT ;
    PORT
      LAYER M4 ;
      RECT 0.000 873.744 0.192 873.768 ;
    END
  END rx[29]
  PIN rx[30]
    DIRECTION OUTPUT ;
    USE SIGNAL ;
    SHAPE ABUTMENT ;
    PORT
      LAYER M4 ;
      RECT 0.000 875.328 0.192 875.352 ;
    END
  END rx[30]
  PIN rx[31]
    DIRECTION OUTPUT ;
    USE SIGNAL ;
    SHAPE ABUTMENT ;
    PORT
      LAYER M4 ;
      RECT 0.000 876.960 0.192 876.984 ;
    END
  END rx[31]
  PIN rx[32]
    DIRECTION OUTPUT ;
    USE SIGNAL ;
    SHAPE ABUTMENT ;
    PORT
      LAYER M4 ;
      RECT 0.000 878.544 0.192 878.568 ;
    END
  END rx[32]
  PIN rx[33]
    DIRECTION OUTPUT ;
    USE SIGNAL ;
    SHAPE ABUTMENT ;
    PORT
      LAYER M4 ;
      RECT 0.000 880.176 0.192 880.200 ;
    END
  END rx[33]
  PIN rx[34]
    DIRECTION OUTPUT ;
    USE SIGNAL ;
    SHAPE ABUTMENT ;
    PORT
      LAYER M4 ;
      RECT 0.000 881.760 0.192 881.784 ;
    END
  END rx[34]
  PIN rx[35]
    DIRECTION OUTPUT ;
    USE SIGNAL ;
    SHAPE ABUTMENT ;
    PORT
      LAYER M4 ;
      RECT 0.000 883.392 0.192 883.416 ;
    END
  END rx[35]
  PIN rx[36]
    DIRECTION OUTPUT ;
    USE SIGNAL ;
    SHAPE ABUTMENT ;
    PORT
      LAYER M4 ;
      RECT 0.000 885.024 0.192 885.048 ;
    END
  END rx[36]
  PIN rx[37]
    DIRECTION OUTPUT ;
    USE SIGNAL ;
    SHAPE ABUTMENT ;
    PORT
      LAYER M4 ;
      RECT 0.000 886.608 0.192 886.632 ;
    END
  END rx[37]
  PIN rx[38]
    DIRECTION OUTPUT ;
    USE SIGNAL ;
    SHAPE ABUTMENT ;
    PORT
      LAYER M4 ;
      RECT 0.000 888.240 0.192 888.264 ;
    END
  END rx[38]
  PIN rx[39]
    DIRECTION OUTPUT ;
    USE SIGNAL ;
    SHAPE ABUTMENT ;
    PORT
      LAYER M4 ;
      RECT 0.000 889.824 0.192 889.848 ;
    END
  END rx[39]
  PIN rx[40]
    DIRECTION OUTPUT ;
    USE SIGNAL ;
    SHAPE ABUTMENT ;
    PORT
      LAYER M4 ;
      RECT 0.000 891.456 0.192 891.480 ;
    END
  END rx[40]
  PIN rx[41]
    DIRECTION OUTPUT ;
    USE SIGNAL ;
    SHAPE ABUTMENT ;
    PORT
      LAYER M4 ;
      RECT 0.000 893.040 0.192 893.064 ;
    END
  END rx[41]
  PIN rx[42]
    DIRECTION OUTPUT ;
    USE SIGNAL ;
    SHAPE ABUTMENT ;
    PORT
      LAYER M4 ;
      RECT 0.000 894.672 0.192 894.696 ;
    END
  END rx[42]
  PIN rx[43]
    DIRECTION OUTPUT ;
    USE SIGNAL ;
    SHAPE ABUTMENT ;
    PORT
      LAYER M4 ;
      RECT 0.000 896.304 0.192 896.328 ;
    END
  END rx[43]
  PIN rx[44]
    DIRECTION OUTPUT ;
    USE SIGNAL ;
    SHAPE ABUTMENT ;
    PORT
      LAYER M4 ;
      RECT 0.000 897.888 0.192 897.912 ;
    END
  END rx[44]
  PIN rx[45]
    DIRECTION OUTPUT ;
    USE SIGNAL ;
    SHAPE ABUTMENT ;
    PORT
      LAYER M4 ;
      RECT 0.000 899.520 0.192 899.544 ;
    END
  END rx[45]
  PIN rx[46]
    DIRECTION OUTPUT ;
    USE SIGNAL ;
    SHAPE ABUTMENT ;
    PORT
      LAYER M4 ;
      RECT 0.000 901.104 0.192 901.128 ;
    END
  END rx[46]
  PIN rx[47]
    DIRECTION OUTPUT ;
    USE SIGNAL ;
    SHAPE ABUTMENT ;
    PORT
      LAYER M4 ;
      RECT 0.000 902.736 0.192 902.760 ;
    END
  END rx[47]
  PIN rx[48]
    DIRECTION OUTPUT ;
    USE SIGNAL ;
    SHAPE ABUTMENT ;
    PORT
      LAYER M4 ;
      RECT 0.000 904.320 0.192 904.344 ;
    END
  END rx[48]
  PIN rx[49]
    DIRECTION OUTPUT ;
    USE SIGNAL ;
    SHAPE ABUTMENT ;
    PORT
      LAYER M4 ;
      RECT 0.000 905.952 0.192 905.976 ;
    END
  END rx[49]
  PIN rx[50]
    DIRECTION OUTPUT ;
    USE SIGNAL ;
    SHAPE ABUTMENT ;
    PORT
      LAYER M4 ;
      RECT 0.000 907.584 0.192 907.608 ;
    END
  END rx[50]
  PIN rx[51]
    DIRECTION OUTPUT ;
    USE SIGNAL ;
    SHAPE ABUTMENT ;
    PORT
      LAYER M4 ;
      RECT 0.000 909.168 0.192 909.192 ;
    END
  END rx[51]
  PIN rx[52]
    DIRECTION OUTPUT ;
    USE SIGNAL ;
    SHAPE ABUTMENT ;
    PORT
      LAYER M4 ;
      RECT 0.000 910.800 0.192 910.824 ;
    END
  END rx[52]
  PIN rx[53]
    DIRECTION OUTPUT ;
    USE SIGNAL ;
    SHAPE ABUTMENT ;
    PORT
      LAYER M4 ;
      RECT 0.000 912.384 0.192 912.408 ;
    END
  END rx[53]
  PIN rx[54]
    DIRECTION OUTPUT ;
    USE SIGNAL ;
    SHAPE ABUTMENT ;
    PORT
      LAYER M4 ;
      RECT 0.000 914.016 0.192 914.040 ;
    END
  END rx[54]
  PIN rx[55]
    DIRECTION OUTPUT ;
    USE SIGNAL ;
    SHAPE ABUTMENT ;
    PORT
      LAYER M4 ;
      RECT 0.000 915.600 0.192 915.624 ;
    END
  END rx[55]
  PIN rx[56]
    DIRECTION OUTPUT ;
    USE SIGNAL ;
    SHAPE ABUTMENT ;
    PORT
      LAYER M4 ;
      RECT 0.000 917.232 0.192 917.256 ;
    END
  END rx[56]
  PIN rx[57]
    DIRECTION OUTPUT ;
    USE SIGNAL ;
    SHAPE ABUTMENT ;
    PORT
      LAYER M4 ;
      RECT 0.000 918.816 0.192 918.840 ;
    END
  END rx[57]
  PIN rx[58]
    DIRECTION OUTPUT ;
    USE SIGNAL ;
    SHAPE ABUTMENT ;
    PORT
      LAYER M4 ;
      RECT 0.000 920.448 0.192 920.472 ;
    END
  END rx[58]
  PIN rx[59]
    DIRECTION OUTPUT ;
    USE SIGNAL ;
    SHAPE ABUTMENT ;
    PORT
      LAYER M4 ;
      RECT 0.000 922.080 0.192 922.104 ;
    END
  END rx[59]
  PIN rx[60]
    DIRECTION OUTPUT ;
    USE SIGNAL ;
    SHAPE ABUTMENT ;
    PORT
      LAYER M4 ;
      RECT 0.000 923.664 0.192 923.688 ;
    END
  END rx[60]
  PIN rx[61]
    DIRECTION OUTPUT ;
    USE SIGNAL ;
    SHAPE ABUTMENT ;
    PORT
      LAYER M4 ;
      RECT 0.000 925.296 0.192 925.320 ;
    END
  END rx[61]
  PIN rx[62]
    DIRECTION OUTPUT ;
    USE SIGNAL ;
    SHAPE ABUTMENT ;
    PORT
      LAYER M4 ;
      RECT 0.000 926.880 0.192 926.904 ;
    END
  END rx[62]
  PIN rx[63]
    DIRECTION OUTPUT ;
    USE SIGNAL ;
    SHAPE ABUTMENT ;
    PORT
      LAYER M4 ;
      RECT 0.000 928.512 0.192 928.536 ;
    END
  END rx[63]
  PIN rx[64]
    DIRECTION OUTPUT ;
    USE SIGNAL ;
    SHAPE ABUTMENT ;
    PORT
      LAYER M4 ;
      RECT 0.000 930.096 0.192 930.120 ;
    END
  END rx[64]
  PIN rx[65]
    DIRECTION OUTPUT ;
    USE SIGNAL ;
    SHAPE ABUTMENT ;
    PORT
      LAYER M4 ;
      RECT 0.000 931.728 0.192 931.752 ;
    END
  END rx[65]
  PIN rx[66]
    DIRECTION OUTPUT ;
    USE SIGNAL ;
    SHAPE ABUTMENT ;
    PORT
      LAYER M4 ;
      RECT 0.000 933.360 0.192 933.384 ;
    END
  END rx[66]
  PIN rx[67]
    DIRECTION OUTPUT ;
    USE SIGNAL ;
    SHAPE ABUTMENT ;
    PORT
      LAYER M4 ;
      RECT 0.000 934.944 0.192 934.968 ;
    END
  END rx[67]
  PIN rx[68]
    DIRECTION OUTPUT ;
    USE SIGNAL ;
    SHAPE ABUTMENT ;
    PORT
      LAYER M4 ;
      RECT 0.000 936.576 0.192 936.600 ;
    END
  END rx[68]
  PIN rx[69]
    DIRECTION OUTPUT ;
    USE SIGNAL ;
    SHAPE ABUTMENT ;
    PORT
      LAYER M4 ;
      RECT 0.000 938.160 0.192 938.184 ;
    END
  END rx[69]
  PIN rx[70]
    DIRECTION OUTPUT ;
    USE SIGNAL ;
    SHAPE ABUTMENT ;
    PORT
      LAYER M4 ;
      RECT 0.000 939.792 0.192 939.816 ;
    END
  END rx[70]
  PIN rx[71]
    DIRECTION OUTPUT ;
    USE SIGNAL ;
    SHAPE ABUTMENT ;
    PORT
      LAYER M4 ;
      RECT 0.000 941.376 0.192 941.400 ;
    END
  END rx[71]
  PIN rx[72]
    DIRECTION OUTPUT ;
    USE SIGNAL ;
    SHAPE ABUTMENT ;
    PORT
      LAYER M4 ;
      RECT 0.000 943.008 0.192 943.032 ;
    END
  END rx[72]
  PIN rx[73]
    DIRECTION OUTPUT ;
    USE SIGNAL ;
    SHAPE ABUTMENT ;
    PORT
      LAYER M4 ;
      RECT 0.000 944.640 0.192 944.664 ;
    END
  END rx[73]
  PIN rx[74]
    DIRECTION OUTPUT ;
    USE SIGNAL ;
    SHAPE ABUTMENT ;
    PORT
      LAYER M4 ;
      RECT 0.000 946.224 0.192 946.248 ;
    END
  END rx[74]
  PIN rx[75]
    DIRECTION OUTPUT ;
    USE SIGNAL ;
    SHAPE ABUTMENT ;
    PORT
      LAYER M4 ;
      RECT 0.000 947.856 0.192 947.880 ;
    END
  END rx[75]
  PIN rx[76]
    DIRECTION OUTPUT ;
    USE SIGNAL ;
    SHAPE ABUTMENT ;
    PORT
      LAYER M4 ;
      RECT 0.000 949.440 0.192 949.464 ;
    END
  END rx[76]
  PIN rx[77]
    DIRECTION OUTPUT ;
    USE SIGNAL ;
    SHAPE ABUTMENT ;
    PORT
      LAYER M4 ;
      RECT 0.000 951.072 0.192 951.096 ;
    END
  END rx[77]
  PIN rx[78]
    DIRECTION OUTPUT ;
    USE SIGNAL ;
    SHAPE ABUTMENT ;
    PORT
      LAYER M4 ;
      RECT 0.000 952.656 0.192 952.680 ;
    END
  END rx[78]
  PIN rx[79]
    DIRECTION OUTPUT ;
    USE SIGNAL ;
    SHAPE ABUTMENT ;
    PORT
      LAYER M4 ;
      RECT 0.000 954.288 0.192 954.312 ;
    END
  END rx[79]
  PIN rx[80]
    DIRECTION OUTPUT ;
    USE SIGNAL ;
    SHAPE ABUTMENT ;
    PORT
      LAYER M4 ;
      RECT 0.000 955.872 0.192 955.896 ;
    END
  END rx[80]
  PIN rx[81]
    DIRECTION OUTPUT ;
    USE SIGNAL ;
    SHAPE ABUTMENT ;
    PORT
      LAYER M4 ;
      RECT 0.000 957.504 0.192 957.528 ;
    END
  END rx[81]
  PIN rx[82]
    DIRECTION OUTPUT ;
    USE SIGNAL ;
    SHAPE ABUTMENT ;
    PORT
      LAYER M4 ;
      RECT 0.000 959.136 0.192 959.160 ;
    END
  END rx[82]
  PIN rx[83]
    DIRECTION OUTPUT ;
    USE SIGNAL ;
    SHAPE ABUTMENT ;
    PORT
      LAYER M4 ;
      RECT 0.000 960.720 0.192 960.744 ;
    END
  END rx[83]
  PIN rx[84]
    DIRECTION OUTPUT ;
    USE SIGNAL ;
    SHAPE ABUTMENT ;
    PORT
      LAYER M4 ;
      RECT 0.000 962.352 0.192 962.376 ;
    END
  END rx[84]
  PIN rx[85]
    DIRECTION OUTPUT ;
    USE SIGNAL ;
    SHAPE ABUTMENT ;
    PORT
      LAYER M4 ;
      RECT 0.000 963.936 0.192 963.960 ;
    END
  END rx[85]
  PIN rx[86]
    DIRECTION OUTPUT ;
    USE SIGNAL ;
    SHAPE ABUTMENT ;
    PORT
      LAYER M4 ;
      RECT 0.000 965.568 0.192 965.592 ;
    END
  END rx[86]
  PIN rx[87]
    DIRECTION OUTPUT ;
    USE SIGNAL ;
    SHAPE ABUTMENT ;
    PORT
      LAYER M4 ;
      RECT 0.000 967.152 0.192 967.176 ;
    END
  END rx[87]
  PIN rx[88]
    DIRECTION OUTPUT ;
    USE SIGNAL ;
    SHAPE ABUTMENT ;
    PORT
      LAYER M4 ;
      RECT 0.000 968.784 0.192 968.808 ;
    END
  END rx[88]
  PIN rx[89]
    DIRECTION OUTPUT ;
    USE SIGNAL ;
    SHAPE ABUTMENT ;
    PORT
      LAYER M4 ;
      RECT 0.000 970.416 0.192 970.440 ;
    END
  END rx[89]
  PIN rx[90]
    DIRECTION OUTPUT ;
    USE SIGNAL ;
    SHAPE ABUTMENT ;
    PORT
      LAYER M4 ;
      RECT 0.000 972.000 0.192 972.024 ;
    END
  END rx[90]
  PIN rx[91]
    DIRECTION OUTPUT ;
    USE SIGNAL ;
    SHAPE ABUTMENT ;
    PORT
      LAYER M4 ;
      RECT 0.000 973.632 0.192 973.656 ;
    END
  END rx[91]
  PIN rx[92]
    DIRECTION OUTPUT ;
    USE SIGNAL ;
    SHAPE ABUTMENT ;
    PORT
      LAYER M4 ;
      RECT 0.000 975.216 0.192 975.240 ;
    END
  END rx[92]
  PIN rx[93]
    DIRECTION OUTPUT ;
    USE SIGNAL ;
    SHAPE ABUTMENT ;
    PORT
      LAYER M4 ;
      RECT 0.000 976.848 0.192 976.872 ;
    END
  END rx[93]
  PIN rx[94]
    DIRECTION OUTPUT ;
    USE SIGNAL ;
    SHAPE ABUTMENT ;
    PORT
      LAYER M4 ;
      RECT 0.000 978.432 0.192 978.456 ;
    END
  END rx[94]
  PIN rx[95]
    DIRECTION OUTPUT ;
    USE SIGNAL ;
    SHAPE ABUTMENT ;
    PORT
      LAYER M4 ;
      RECT 0.000 980.064 0.192 980.088 ;
    END
  END rx[95]
  PIN rx[96]
    DIRECTION OUTPUT ;
    USE SIGNAL ;
    SHAPE ABUTMENT ;
    PORT
      LAYER M4 ;
      RECT 0.000 981.696 0.192 981.720 ;
    END
  END rx[96]
  PIN rx[97]
    DIRECTION OUTPUT ;
    USE SIGNAL ;
    SHAPE ABUTMENT ;
    PORT
      LAYER M4 ;
      RECT 0.000 983.280 0.192 983.304 ;
    END
  END rx[97]
  PIN rx[98]
    DIRECTION OUTPUT ;
    USE SIGNAL ;
    SHAPE ABUTMENT ;
    PORT
      LAYER M4 ;
      RECT 0.000 984.912 0.192 984.936 ;
    END
  END rx[98]
  PIN rx[99]
    DIRECTION OUTPUT ;
    USE SIGNAL ;
    SHAPE ABUTMENT ;
    PORT
      LAYER M4 ;
      RECT 0.000 986.496 0.192 986.520 ;
    END
  END rx[99]
  PIN rx[100]
    DIRECTION OUTPUT ;
    USE SIGNAL ;
    SHAPE ABUTMENT ;
    PORT
      LAYER M4 ;
      RECT 0.000 988.128 0.192 988.152 ;
    END
  END rx[100]
  PIN rx[101]
    DIRECTION OUTPUT ;
    USE SIGNAL ;
    SHAPE ABUTMENT ;
    PORT
      LAYER M4 ;
      RECT 0.000 989.712 0.192 989.736 ;
    END
  END rx[101]
  PIN rx[102]
    DIRECTION OUTPUT ;
    USE SIGNAL ;
    SHAPE ABUTMENT ;
    PORT
      LAYER M4 ;
      RECT 0.000 991.344 0.192 991.368 ;
    END
  END rx[102]
  PIN rx[103]
    DIRECTION OUTPUT ;
    USE SIGNAL ;
    SHAPE ABUTMENT ;
    PORT
      LAYER M4 ;
      RECT 0.000 992.928 0.192 992.952 ;
    END
  END rx[103]
  PIN rx[104]
    DIRECTION OUTPUT ;
    USE SIGNAL ;
    SHAPE ABUTMENT ;
    PORT
      LAYER M4 ;
      RECT 0.000 994.560 0.192 994.584 ;
    END
  END rx[104]
  PIN rx[105]
    DIRECTION OUTPUT ;
    USE SIGNAL ;
    SHAPE ABUTMENT ;
    PORT
      LAYER M4 ;
      RECT 0.000 996.192 0.192 996.216 ;
    END
  END rx[105]
  PIN rx[106]
    DIRECTION OUTPUT ;
    USE SIGNAL ;
    SHAPE ABUTMENT ;
    PORT
      LAYER M4 ;
      RECT 0.000 997.776 0.192 997.800 ;
    END
  END rx[106]
  PIN rx[107]
    DIRECTION OUTPUT ;
    USE SIGNAL ;
    SHAPE ABUTMENT ;
    PORT
      LAYER M4 ;
      RECT 0.000 999.408 0.192 999.432 ;
    END
  END rx[107]
  PIN rx[108]
    DIRECTION OUTPUT ;
    USE SIGNAL ;
    SHAPE ABUTMENT ;
    PORT
      LAYER M4 ;
      RECT 0.000 1000.992 0.192 1001.016 ;
    END
  END rx[108]
  PIN rx[109]
    DIRECTION OUTPUT ;
    USE SIGNAL ;
    SHAPE ABUTMENT ;
    PORT
      LAYER M4 ;
      RECT 0.000 1002.624 0.192 1002.648 ;
    END
  END rx[109]
  PIN rx[110]
    DIRECTION OUTPUT ;
    USE SIGNAL ;
    SHAPE ABUTMENT ;
    PORT
      LAYER M4 ;
      RECT 0.000 1004.208 0.192 1004.232 ;
    END
  END rx[110]
  PIN rx[111]
    DIRECTION OUTPUT ;
    USE SIGNAL ;
    SHAPE ABUTMENT ;
    PORT
      LAYER M4 ;
      RECT 0.000 1005.840 0.192 1005.864 ;
    END
  END rx[111]
  PIN rx[112]
    DIRECTION OUTPUT ;
    USE SIGNAL ;
    SHAPE ABUTMENT ;
    PORT
      LAYER M4 ;
      RECT 0.000 1007.472 0.192 1007.496 ;
    END
  END rx[112]
  PIN rx[113]
    DIRECTION OUTPUT ;
    USE SIGNAL ;
    SHAPE ABUTMENT ;
    PORT
      LAYER M4 ;
      RECT 0.000 1009.056 0.192 1009.080 ;
    END
  END rx[113]
  PIN rx[114]
    DIRECTION OUTPUT ;
    USE SIGNAL ;
    SHAPE ABUTMENT ;
    PORT
      LAYER M4 ;
      RECT 0.000 1010.688 0.192 1010.712 ;
    END
  END rx[114]
  PIN rx[115]
    DIRECTION OUTPUT ;
    USE SIGNAL ;
    SHAPE ABUTMENT ;
    PORT
      LAYER M4 ;
      RECT 0.000 1012.272 0.192 1012.296 ;
    END
  END rx[115]
  PIN rx[116]
    DIRECTION OUTPUT ;
    USE SIGNAL ;
    SHAPE ABUTMENT ;
    PORT
      LAYER M4 ;
      RECT 0.000 1013.904 0.192 1013.928 ;
    END
  END rx[116]
  PIN rx[117]
    DIRECTION OUTPUT ;
    USE SIGNAL ;
    SHAPE ABUTMENT ;
    PORT
      LAYER M4 ;
      RECT 0.000 1015.488 0.192 1015.512 ;
    END
  END rx[117]
  PIN rx[118]
    DIRECTION OUTPUT ;
    USE SIGNAL ;
    SHAPE ABUTMENT ;
    PORT
      LAYER M4 ;
      RECT 0.000 1017.120 0.192 1017.144 ;
    END
  END rx[118]
  PIN rx[119]
    DIRECTION OUTPUT ;
    USE SIGNAL ;
    SHAPE ABUTMENT ;
    PORT
      LAYER M4 ;
      RECT 0.000 1018.752 0.192 1018.776 ;
    END
  END rx[119]
  PIN rx[120]
    DIRECTION OUTPUT ;
    USE SIGNAL ;
    SHAPE ABUTMENT ;
    PORT
      LAYER M4 ;
      RECT 0.000 1020.336 0.192 1020.360 ;
    END
  END rx[120]
  PIN rx[121]
    DIRECTION OUTPUT ;
    USE SIGNAL ;
    SHAPE ABUTMENT ;
    PORT
      LAYER M4 ;
      RECT 0.000 1021.968 0.192 1021.992 ;
    END
  END rx[121]
  PIN rx[122]
    DIRECTION OUTPUT ;
    USE SIGNAL ;
    SHAPE ABUTMENT ;
    PORT
      LAYER M4 ;
      RECT 0.000 1023.552 0.192 1023.576 ;
    END
  END rx[122]
  PIN rx[123]
    DIRECTION OUTPUT ;
    USE SIGNAL ;
    SHAPE ABUTMENT ;
    PORT
      LAYER M4 ;
      RECT 0.000 1025.184 0.192 1025.208 ;
    END
  END rx[123]
  PIN rx[124]
    DIRECTION OUTPUT ;
    USE SIGNAL ;
    SHAPE ABUTMENT ;
    PORT
      LAYER M4 ;
      RECT 0.000 1026.768 0.192 1026.792 ;
    END
  END rx[124]
  PIN rx[125]
    DIRECTION OUTPUT ;
    USE SIGNAL ;
    SHAPE ABUTMENT ;
    PORT
      LAYER M4 ;
      RECT 0.000 1028.400 0.192 1028.424 ;
    END
  END rx[125]
  PIN rx[126]
    DIRECTION OUTPUT ;
    USE SIGNAL ;
    SHAPE ABUTMENT ;
    PORT
      LAYER M4 ;
      RECT 0.000 1029.984 0.192 1030.008 ;
    END
  END rx[126]
  PIN rx[127]
    DIRECTION OUTPUT ;
    USE SIGNAL ;
    SHAPE ABUTMENT ;
    PORT
      LAYER M4 ;
      RECT 0.000 1031.616 0.192 1031.640 ;
    END
  END rx[127]
  PIN rx[128]
    DIRECTION OUTPUT ;
    USE SIGNAL ;
    SHAPE ABUTMENT ;
    PORT
      LAYER M4 ;
      RECT 0.000 1033.248 0.192 1033.272 ;
    END
  END rx[128]
  PIN rx[129]
    DIRECTION OUTPUT ;
    USE SIGNAL ;
    SHAPE ABUTMENT ;
    PORT
      LAYER M4 ;
      RECT 0.000 1034.832 0.192 1034.856 ;
    END
  END rx[129]
  PIN rx[130]
    DIRECTION OUTPUT ;
    USE SIGNAL ;
    SHAPE ABUTMENT ;
    PORT
      LAYER M4 ;
      RECT 0.000 1036.464 0.192 1036.488 ;
    END
  END rx[130]
  PIN rx[131]
    DIRECTION OUTPUT ;
    USE SIGNAL ;
    SHAPE ABUTMENT ;
    PORT
      LAYER M4 ;
      RECT 0.000 1038.048 0.192 1038.072 ;
    END
  END rx[131]
  PIN rx[132]
    DIRECTION OUTPUT ;
    USE SIGNAL ;
    SHAPE ABUTMENT ;
    PORT
      LAYER M4 ;
      RECT 0.000 1039.680 0.192 1039.704 ;
    END
  END rx[132]
  PIN rx[133]
    DIRECTION OUTPUT ;
    USE SIGNAL ;
    SHAPE ABUTMENT ;
    PORT
      LAYER M4 ;
      RECT 0.000 1041.264 0.192 1041.288 ;
    END
  END rx[133]
  PIN rx[134]
    DIRECTION OUTPUT ;
    USE SIGNAL ;
    SHAPE ABUTMENT ;
    PORT
      LAYER M4 ;
      RECT 0.000 1042.896 0.192 1042.920 ;
    END
  END rx[134]
  PIN rx[135]
    DIRECTION OUTPUT ;
    USE SIGNAL ;
    SHAPE ABUTMENT ;
    PORT
      LAYER M4 ;
      RECT 0.000 1044.528 0.192 1044.552 ;
    END
  END rx[135]
  PIN rx[136]
    DIRECTION OUTPUT ;
    USE SIGNAL ;
    SHAPE ABUTMENT ;
    PORT
      LAYER M4 ;
      RECT 0.000 1046.112 0.192 1046.136 ;
    END
  END rx[136]
  PIN rx[137]
    DIRECTION OUTPUT ;
    USE SIGNAL ;
    SHAPE ABUTMENT ;
    PORT
      LAYER M4 ;
      RECT 0.000 1047.744 0.192 1047.768 ;
    END
  END rx[137]
  PIN rx[138]
    DIRECTION OUTPUT ;
    USE SIGNAL ;
    SHAPE ABUTMENT ;
    PORT
      LAYER M4 ;
      RECT 0.000 1049.328 0.192 1049.352 ;
    END
  END rx[138]
  PIN rx[139]
    DIRECTION OUTPUT ;
    USE SIGNAL ;
    SHAPE ABUTMENT ;
    PORT
      LAYER M4 ;
      RECT 0.000 1050.960 0.192 1050.984 ;
    END
  END rx[139]
  PIN rx[140]
    DIRECTION OUTPUT ;
    USE SIGNAL ;
    SHAPE ABUTMENT ;
    PORT
      LAYER M4 ;
      RECT 0.000 1052.544 0.192 1052.568 ;
    END
  END rx[140]
  PIN rx[141]
    DIRECTION OUTPUT ;
    USE SIGNAL ;
    SHAPE ABUTMENT ;
    PORT
      LAYER M4 ;
      RECT 0.000 1054.176 0.192 1054.200 ;
    END
  END rx[141]
  PIN rx[142]
    DIRECTION OUTPUT ;
    USE SIGNAL ;
    SHAPE ABUTMENT ;
    PORT
      LAYER M4 ;
      RECT 0.000 1055.760 0.192 1055.784 ;
    END
  END rx[142]
  PIN rx[143]
    DIRECTION OUTPUT ;
    USE SIGNAL ;
    SHAPE ABUTMENT ;
    PORT
      LAYER M4 ;
      RECT 0.000 1057.392 0.192 1057.416 ;
    END
  END rx[143]
  PIN rx[144]
    DIRECTION OUTPUT ;
    USE SIGNAL ;
    SHAPE ABUTMENT ;
    PORT
      LAYER M4 ;
      RECT 0.000 1059.024 0.192 1059.048 ;
    END
  END rx[144]
  PIN rx[145]
    DIRECTION OUTPUT ;
    USE SIGNAL ;
    SHAPE ABUTMENT ;
    PORT
      LAYER M4 ;
      RECT 0.000 1060.608 0.192 1060.632 ;
    END
  END rx[145]
  PIN rx[146]
    DIRECTION OUTPUT ;
    USE SIGNAL ;
    SHAPE ABUTMENT ;
    PORT
      LAYER M4 ;
      RECT 0.000 1062.240 0.192 1062.264 ;
    END
  END rx[146]
  PIN rx[147]
    DIRECTION OUTPUT ;
    USE SIGNAL ;
    SHAPE ABUTMENT ;
    PORT
      LAYER M4 ;
      RECT 0.000 1063.824 0.192 1063.848 ;
    END
  END rx[147]
  PIN rx[148]
    DIRECTION OUTPUT ;
    USE SIGNAL ;
    SHAPE ABUTMENT ;
    PORT
      LAYER M4 ;
      RECT 0.000 1065.456 0.192 1065.480 ;
    END
  END rx[148]
  PIN rx[149]
    DIRECTION OUTPUT ;
    USE SIGNAL ;
    SHAPE ABUTMENT ;
    PORT
      LAYER M4 ;
      RECT 0.000 1067.040 0.192 1067.064 ;
    END
  END rx[149]
  PIN rx[150]
    DIRECTION OUTPUT ;
    USE SIGNAL ;
    SHAPE ABUTMENT ;
    PORT
      LAYER M4 ;
      RECT 0.000 1068.672 0.192 1068.696 ;
    END
  END rx[150]
  PIN rx[151]
    DIRECTION OUTPUT ;
    USE SIGNAL ;
    SHAPE ABUTMENT ;
    PORT
      LAYER M4 ;
      RECT 0.000 1070.304 0.192 1070.328 ;
    END
  END rx[151]
  PIN rx[152]
    DIRECTION OUTPUT ;
    USE SIGNAL ;
    SHAPE ABUTMENT ;
    PORT
      LAYER M4 ;
      RECT 0.000 1071.888 0.192 1071.912 ;
    END
  END rx[152]
  PIN rx[153]
    DIRECTION OUTPUT ;
    USE SIGNAL ;
    SHAPE ABUTMENT ;
    PORT
      LAYER M4 ;
      RECT 0.000 1073.520 0.192 1073.544 ;
    END
  END rx[153]
  PIN rx[154]
    DIRECTION OUTPUT ;
    USE SIGNAL ;
    SHAPE ABUTMENT ;
    PORT
      LAYER M4 ;
      RECT 0.000 1075.104 0.192 1075.128 ;
    END
  END rx[154]
  PIN rx[155]
    DIRECTION OUTPUT ;
    USE SIGNAL ;
    SHAPE ABUTMENT ;
    PORT
      LAYER M4 ;
      RECT 0.000 1076.736 0.192 1076.760 ;
    END
  END rx[155]
  PIN rx[156]
    DIRECTION OUTPUT ;
    USE SIGNAL ;
    SHAPE ABUTMENT ;
    PORT
      LAYER M4 ;
      RECT 0.000 1078.320 0.192 1078.344 ;
    END
  END rx[156]
  PIN rx[157]
    DIRECTION OUTPUT ;
    USE SIGNAL ;
    SHAPE ABUTMENT ;
    PORT
      LAYER M4 ;
      RECT 0.000 1079.952 0.192 1079.976 ;
    END
  END rx[157]
  PIN rx[158]
    DIRECTION OUTPUT ;
    USE SIGNAL ;
    SHAPE ABUTMENT ;
    PORT
      LAYER M4 ;
      RECT 0.000 1081.584 0.192 1081.608 ;
    END
  END rx[158]
  PIN rx[159]
    DIRECTION OUTPUT ;
    USE SIGNAL ;
    SHAPE ABUTMENT ;
    PORT
      LAYER M4 ;
      RECT 0.000 1083.168 0.192 1083.192 ;
    END
  END rx[159]
  PIN rx[160]
    DIRECTION OUTPUT ;
    USE SIGNAL ;
    SHAPE ABUTMENT ;
    PORT
      LAYER M4 ;
      RECT 0.000 1084.800 0.192 1084.824 ;
    END
  END rx[160]
  PIN rx[161]
    DIRECTION OUTPUT ;
    USE SIGNAL ;
    SHAPE ABUTMENT ;
    PORT
      LAYER M4 ;
      RECT 0.000 1086.384 0.192 1086.408 ;
    END
  END rx[161]
  PIN rx[162]
    DIRECTION OUTPUT ;
    USE SIGNAL ;
    SHAPE ABUTMENT ;
    PORT
      LAYER M4 ;
      RECT 0.000 1088.016 0.192 1088.040 ;
    END
  END rx[162]
  PIN rx[163]
    DIRECTION OUTPUT ;
    USE SIGNAL ;
    SHAPE ABUTMENT ;
    PORT
      LAYER M4 ;
      RECT 0.000 1089.600 0.192 1089.624 ;
    END
  END rx[163]
  PIN rx[164]
    DIRECTION OUTPUT ;
    USE SIGNAL ;
    SHAPE ABUTMENT ;
    PORT
      LAYER M4 ;
      RECT 0.000 1091.232 0.192 1091.256 ;
    END
  END rx[164]
  PIN rx[165]
    DIRECTION OUTPUT ;
    USE SIGNAL ;
    SHAPE ABUTMENT ;
    PORT
      LAYER M4 ;
      RECT 0.000 1092.816 0.192 1092.840 ;
    END
  END rx[165]
  PIN rx[166]
    DIRECTION OUTPUT ;
    USE SIGNAL ;
    SHAPE ABUTMENT ;
    PORT
      LAYER M4 ;
      RECT 0.000 1094.448 0.192 1094.472 ;
    END
  END rx[166]
  PIN rx[167]
    DIRECTION OUTPUT ;
    USE SIGNAL ;
    SHAPE ABUTMENT ;
    PORT
      LAYER M4 ;
      RECT 0.000 1096.080 0.192 1096.104 ;
    END
  END rx[167]
  PIN rx[168]
    DIRECTION OUTPUT ;
    USE SIGNAL ;
    SHAPE ABUTMENT ;
    PORT
      LAYER M4 ;
      RECT 0.000 1097.664 0.192 1097.688 ;
    END
  END rx[168]
  PIN rx[169]
    DIRECTION OUTPUT ;
    USE SIGNAL ;
    SHAPE ABUTMENT ;
    PORT
      LAYER M4 ;
      RECT 0.000 1099.296 0.192 1099.320 ;
    END
  END rx[169]
  PIN rx[170]
    DIRECTION OUTPUT ;
    USE SIGNAL ;
    SHAPE ABUTMENT ;
    PORT
      LAYER M4 ;
      RECT 0.000 1100.880 0.192 1100.904 ;
    END
  END rx[170]
  PIN rx[171]
    DIRECTION OUTPUT ;
    USE SIGNAL ;
    SHAPE ABUTMENT ;
    PORT
      LAYER M4 ;
      RECT 0.000 1102.512 0.192 1102.536 ;
    END
  END rx[171]
  PIN rx[172]
    DIRECTION OUTPUT ;
    USE SIGNAL ;
    SHAPE ABUTMENT ;
    PORT
      LAYER M4 ;
      RECT 0.000 1104.096 0.192 1104.120 ;
    END
  END rx[172]
  PIN rx[173]
    DIRECTION OUTPUT ;
    USE SIGNAL ;
    SHAPE ABUTMENT ;
    PORT
      LAYER M4 ;
      RECT 0.000 1105.728 0.192 1105.752 ;
    END
  END rx[173]
  PIN rx[174]
    DIRECTION OUTPUT ;
    USE SIGNAL ;
    SHAPE ABUTMENT ;
    PORT
      LAYER M4 ;
      RECT 0.000 1107.360 0.192 1107.384 ;
    END
  END rx[174]
  PIN rx[175]
    DIRECTION OUTPUT ;
    USE SIGNAL ;
    SHAPE ABUTMENT ;
    PORT
      LAYER M4 ;
      RECT 0.000 1108.944 0.192 1108.968 ;
    END
  END rx[175]
  PIN rx[176]
    DIRECTION OUTPUT ;
    USE SIGNAL ;
    SHAPE ABUTMENT ;
    PORT
      LAYER M4 ;
      RECT 0.000 1110.576 0.192 1110.600 ;
    END
  END rx[176]
  PIN rx[177]
    DIRECTION OUTPUT ;
    USE SIGNAL ;
    SHAPE ABUTMENT ;
    PORT
      LAYER M4 ;
      RECT 0.000 1112.160 0.192 1112.184 ;
    END
  END rx[177]
  PIN rx[178]
    DIRECTION OUTPUT ;
    USE SIGNAL ;
    SHAPE ABUTMENT ;
    PORT
      LAYER M4 ;
      RECT 0.000 1113.792 0.192 1113.816 ;
    END
  END rx[178]
  PIN rx[179]
    DIRECTION OUTPUT ;
    USE SIGNAL ;
    SHAPE ABUTMENT ;
    PORT
      LAYER M4 ;
      RECT 0.000 1115.376 0.192 1115.400 ;
    END
  END rx[179]
  PIN rx[180]
    DIRECTION OUTPUT ;
    USE SIGNAL ;
    SHAPE ABUTMENT ;
    PORT
      LAYER M4 ;
      RECT 0.000 1117.008 0.192 1117.032 ;
    END
  END rx[180]
  PIN rx[181]
    DIRECTION OUTPUT ;
    USE SIGNAL ;
    SHAPE ABUTMENT ;
    PORT
      LAYER M4 ;
      RECT 0.000 1118.640 0.192 1118.664 ;
    END
  END rx[181]
  PIN rx[182]
    DIRECTION OUTPUT ;
    USE SIGNAL ;
    SHAPE ABUTMENT ;
    PORT
      LAYER M4 ;
      RECT 0.000 1120.224 0.192 1120.248 ;
    END
  END rx[182]
  PIN rx[183]
    DIRECTION OUTPUT ;
    USE SIGNAL ;
    SHAPE ABUTMENT ;
    PORT
      LAYER M4 ;
      RECT 0.000 1121.856 0.192 1121.880 ;
    END
  END rx[183]
  PIN rx[184]
    DIRECTION OUTPUT ;
    USE SIGNAL ;
    SHAPE ABUTMENT ;
    PORT
      LAYER M4 ;
      RECT 0.000 1123.440 0.192 1123.464 ;
    END
  END rx[184]
  PIN rx[185]
    DIRECTION OUTPUT ;
    USE SIGNAL ;
    SHAPE ABUTMENT ;
    PORT
      LAYER M4 ;
      RECT 0.000 1125.072 0.192 1125.096 ;
    END
  END rx[185]
  PIN rx[186]
    DIRECTION OUTPUT ;
    USE SIGNAL ;
    SHAPE ABUTMENT ;
    PORT
      LAYER M4 ;
      RECT 0.000 1126.656 0.192 1126.680 ;
    END
  END rx[186]
  PIN rx[187]
    DIRECTION OUTPUT ;
    USE SIGNAL ;
    SHAPE ABUTMENT ;
    PORT
      LAYER M4 ;
      RECT 0.000 1128.288 0.192 1128.312 ;
    END
  END rx[187]
  PIN rx[188]
    DIRECTION OUTPUT ;
    USE SIGNAL ;
    SHAPE ABUTMENT ;
    PORT
      LAYER M4 ;
      RECT 0.000 1129.872 0.192 1129.896 ;
    END
  END rx[188]
  PIN rx[189]
    DIRECTION OUTPUT ;
    USE SIGNAL ;
    SHAPE ABUTMENT ;
    PORT
      LAYER M4 ;
      RECT 0.000 1131.504 0.192 1131.528 ;
    END
  END rx[189]
  PIN rx[190]
    DIRECTION OUTPUT ;
    USE SIGNAL ;
    SHAPE ABUTMENT ;
    PORT
      LAYER M4 ;
      RECT 0.000 1133.136 0.192 1133.160 ;
    END
  END rx[190]
  PIN rx[191]
    DIRECTION OUTPUT ;
    USE SIGNAL ;
    SHAPE ABUTMENT ;
    PORT
      LAYER M4 ;
      RECT 0.000 1134.720 0.192 1134.744 ;
    END
  END rx[191]
  PIN rx[192]
    DIRECTION OUTPUT ;
    USE SIGNAL ;
    SHAPE ABUTMENT ;
    PORT
      LAYER M4 ;
      RECT 0.000 1136.352 0.192 1136.376 ;
    END
  END rx[192]
  PIN rx[193]
    DIRECTION OUTPUT ;
    USE SIGNAL ;
    SHAPE ABUTMENT ;
    PORT
      LAYER M4 ;
      RECT 0.000 1137.936 0.192 1137.960 ;
    END
  END rx[193]
  PIN rx[194]
    DIRECTION OUTPUT ;
    USE SIGNAL ;
    SHAPE ABUTMENT ;
    PORT
      LAYER M4 ;
      RECT 0.000 1139.568 0.192 1139.592 ;
    END
  END rx[194]
  PIN rx[195]
    DIRECTION OUTPUT ;
    USE SIGNAL ;
    SHAPE ABUTMENT ;
    PORT
      LAYER M4 ;
      RECT 0.000 1141.152 0.192 1141.176 ;
    END
  END rx[195]
  PIN rx[196]
    DIRECTION OUTPUT ;
    USE SIGNAL ;
    SHAPE ABUTMENT ;
    PORT
      LAYER M4 ;
      RECT 0.000 1142.784 0.192 1142.808 ;
    END
  END rx[196]
  PIN rx[197]
    DIRECTION OUTPUT ;
    USE SIGNAL ;
    SHAPE ABUTMENT ;
    PORT
      LAYER M4 ;
      RECT 0.000 1144.416 0.192 1144.440 ;
    END
  END rx[197]
  PIN rx[198]
    DIRECTION OUTPUT ;
    USE SIGNAL ;
    SHAPE ABUTMENT ;
    PORT
      LAYER M4 ;
      RECT 0.000 1146.000 0.192 1146.024 ;
    END
  END rx[198]
  PIN rx[199]
    DIRECTION OUTPUT ;
    USE SIGNAL ;
    SHAPE ABUTMENT ;
    PORT
      LAYER M4 ;
      RECT 0.000 1147.632 0.192 1147.656 ;
    END
  END rx[199]
  PIN rx[200]
    DIRECTION OUTPUT ;
    USE SIGNAL ;
    SHAPE ABUTMENT ;
    PORT
      LAYER M4 ;
      RECT 0.000 1149.216 0.192 1149.240 ;
    END
  END rx[200]
  PIN rx[201]
    DIRECTION OUTPUT ;
    USE SIGNAL ;
    SHAPE ABUTMENT ;
    PORT
      LAYER M4 ;
      RECT 0.000 1150.848 0.192 1150.872 ;
    END
  END rx[201]
  PIN rx[202]
    DIRECTION OUTPUT ;
    USE SIGNAL ;
    SHAPE ABUTMENT ;
    PORT
      LAYER M4 ;
      RECT 0.000 1152.432 0.192 1152.456 ;
    END
  END rx[202]
  PIN rx[203]
    DIRECTION OUTPUT ;
    USE SIGNAL ;
    SHAPE ABUTMENT ;
    PORT
      LAYER M4 ;
      RECT 0.000 1154.064 0.192 1154.088 ;
    END
  END rx[203]
  PIN rx[204]
    DIRECTION OUTPUT ;
    USE SIGNAL ;
    SHAPE ABUTMENT ;
    PORT
      LAYER M4 ;
      RECT 0.000 1155.696 0.192 1155.720 ;
    END
  END rx[204]
  PIN rx[205]
    DIRECTION OUTPUT ;
    USE SIGNAL ;
    SHAPE ABUTMENT ;
    PORT
      LAYER M4 ;
      RECT 0.000 1157.280 0.192 1157.304 ;
    END
  END rx[205]
  PIN rx[206]
    DIRECTION OUTPUT ;
    USE SIGNAL ;
    SHAPE ABUTMENT ;
    PORT
      LAYER M4 ;
      RECT 0.000 1158.912 0.192 1158.936 ;
    END
  END rx[206]
  PIN rx[207]
    DIRECTION OUTPUT ;
    USE SIGNAL ;
    SHAPE ABUTMENT ;
    PORT
      LAYER M4 ;
      RECT 0.000 1160.496 0.192 1160.520 ;
    END
  END rx[207]
  PIN rx[208]
    DIRECTION OUTPUT ;
    USE SIGNAL ;
    SHAPE ABUTMENT ;
    PORT
      LAYER M4 ;
      RECT 0.000 1162.128 0.192 1162.152 ;
    END
  END rx[208]
  PIN rx[209]
    DIRECTION OUTPUT ;
    USE SIGNAL ;
    SHAPE ABUTMENT ;
    PORT
      LAYER M4 ;
      RECT 0.000 1163.712 0.192 1163.736 ;
    END
  END rx[209]
  PIN rx[210]
    DIRECTION OUTPUT ;
    USE SIGNAL ;
    SHAPE ABUTMENT ;
    PORT
      LAYER M4 ;
      RECT 0.000 1165.344 0.192 1165.368 ;
    END
  END rx[210]
  PIN rx[211]
    DIRECTION OUTPUT ;
    USE SIGNAL ;
    SHAPE ABUTMENT ;
    PORT
      LAYER M4 ;
      RECT 0.000 1166.928 0.192 1166.952 ;
    END
  END rx[211]
  PIN rx[212]
    DIRECTION OUTPUT ;
    USE SIGNAL ;
    SHAPE ABUTMENT ;
    PORT
      LAYER M4 ;
      RECT 0.000 1168.560 0.192 1168.584 ;
    END
  END rx[212]
  PIN rx[213]
    DIRECTION OUTPUT ;
    USE SIGNAL ;
    SHAPE ABUTMENT ;
    PORT
      LAYER M4 ;
      RECT 0.000 1170.192 0.192 1170.216 ;
    END
  END rx[213]
  PIN rx[214]
    DIRECTION OUTPUT ;
    USE SIGNAL ;
    SHAPE ABUTMENT ;
    PORT
      LAYER M4 ;
      RECT 0.000 1171.776 0.192 1171.800 ;
    END
  END rx[214]
  PIN rx[215]
    DIRECTION OUTPUT ;
    USE SIGNAL ;
    SHAPE ABUTMENT ;
    PORT
      LAYER M4 ;
      RECT 0.000 1173.408 0.192 1173.432 ;
    END
  END rx[215]
  PIN rx[216]
    DIRECTION OUTPUT ;
    USE SIGNAL ;
    SHAPE ABUTMENT ;
    PORT
      LAYER M4 ;
      RECT 0.000 1174.992 0.192 1175.016 ;
    END
  END rx[216]
  PIN rx[217]
    DIRECTION OUTPUT ;
    USE SIGNAL ;
    SHAPE ABUTMENT ;
    PORT
      LAYER M4 ;
      RECT 0.000 1176.624 0.192 1176.648 ;
    END
  END rx[217]
  PIN rx[218]
    DIRECTION OUTPUT ;
    USE SIGNAL ;
    SHAPE ABUTMENT ;
    PORT
      LAYER M4 ;
      RECT 0.000 1178.208 0.192 1178.232 ;
    END
  END rx[218]
  PIN rx[219]
    DIRECTION OUTPUT ;
    USE SIGNAL ;
    SHAPE ABUTMENT ;
    PORT
      LAYER M4 ;
      RECT 0.000 1179.840 0.192 1179.864 ;
    END
  END rx[219]
  PIN rx[220]
    DIRECTION OUTPUT ;
    USE SIGNAL ;
    SHAPE ABUTMENT ;
    PORT
      LAYER M4 ;
      RECT 0.000 1181.472 0.192 1181.496 ;
    END
  END rx[220]
  PIN rx[221]
    DIRECTION OUTPUT ;
    USE SIGNAL ;
    SHAPE ABUTMENT ;
    PORT
      LAYER M4 ;
      RECT 0.000 1183.056 0.192 1183.080 ;
    END
  END rx[221]
  PIN rx[222]
    DIRECTION OUTPUT ;
    USE SIGNAL ;
    SHAPE ABUTMENT ;
    PORT
      LAYER M4 ;
      RECT 0.000 1184.688 0.192 1184.712 ;
    END
  END rx[222]
  PIN rx[223]
    DIRECTION OUTPUT ;
    USE SIGNAL ;
    SHAPE ABUTMENT ;
    PORT
      LAYER M4 ;
      RECT 0.000 1186.272 0.192 1186.296 ;
    END
  END rx[223]
  PIN rx[224]
    DIRECTION OUTPUT ;
    USE SIGNAL ;
    SHAPE ABUTMENT ;
    PORT
      LAYER M4 ;
      RECT 0.000 1187.904 0.192 1187.928 ;
    END
  END rx[224]
  PIN rx[225]
    DIRECTION OUTPUT ;
    USE SIGNAL ;
    SHAPE ABUTMENT ;
    PORT
      LAYER M4 ;
      RECT 0.000 1189.488 0.192 1189.512 ;
    END
  END rx[225]
  PIN rx[226]
    DIRECTION OUTPUT ;
    USE SIGNAL ;
    SHAPE ABUTMENT ;
    PORT
      LAYER M4 ;
      RECT 0.000 1191.120 0.192 1191.144 ;
    END
  END rx[226]
  PIN rx[227]
    DIRECTION OUTPUT ;
    USE SIGNAL ;
    SHAPE ABUTMENT ;
    PORT
      LAYER M4 ;
      RECT 0.000 1192.752 0.192 1192.776 ;
    END
  END rx[227]
  PIN rx[228]
    DIRECTION OUTPUT ;
    USE SIGNAL ;
    SHAPE ABUTMENT ;
    PORT
      LAYER M4 ;
      RECT 0.000 1194.336 0.192 1194.360 ;
    END
  END rx[228]
  PIN rx[229]
    DIRECTION OUTPUT ;
    USE SIGNAL ;
    SHAPE ABUTMENT ;
    PORT
      LAYER M4 ;
      RECT 0.000 1195.968 0.192 1195.992 ;
    END
  END rx[229]
  PIN rx[230]
    DIRECTION OUTPUT ;
    USE SIGNAL ;
    SHAPE ABUTMENT ;
    PORT
      LAYER M4 ;
      RECT 0.000 1197.552 0.192 1197.576 ;
    END
  END rx[230]
  PIN rx[231]
    DIRECTION OUTPUT ;
    USE SIGNAL ;
    SHAPE ABUTMENT ;
    PORT
      LAYER M4 ;
      RECT 0.000 1199.184 0.192 1199.208 ;
    END
  END rx[231]
  PIN rx[232]
    DIRECTION OUTPUT ;
    USE SIGNAL ;
    SHAPE ABUTMENT ;
    PORT
      LAYER M4 ;
      RECT 0.000 1200.768 0.192 1200.792 ;
    END
  END rx[232]
  PIN rx[233]
    DIRECTION OUTPUT ;
    USE SIGNAL ;
    SHAPE ABUTMENT ;
    PORT
      LAYER M4 ;
      RECT 0.000 1202.400 0.192 1202.424 ;
    END
  END rx[233]
  PIN rx[234]
    DIRECTION OUTPUT ;
    USE SIGNAL ;
    SHAPE ABUTMENT ;
    PORT
      LAYER M4 ;
      RECT 0.000 1203.984 0.192 1204.008 ;
    END
  END rx[234]
  PIN rx[235]
    DIRECTION OUTPUT ;
    USE SIGNAL ;
    SHAPE ABUTMENT ;
    PORT
      LAYER M4 ;
      RECT 0.000 1205.616 0.192 1205.640 ;
    END
  END rx[235]
  PIN rx[236]
    DIRECTION OUTPUT ;
    USE SIGNAL ;
    SHAPE ABUTMENT ;
    PORT
      LAYER M4 ;
      RECT 0.000 1207.248 0.192 1207.272 ;
    END
  END rx[236]
  PIN rx[237]
    DIRECTION OUTPUT ;
    USE SIGNAL ;
    SHAPE ABUTMENT ;
    PORT
      LAYER M4 ;
      RECT 0.000 1208.832 0.192 1208.856 ;
    END
  END rx[237]
  PIN rx[238]
    DIRECTION OUTPUT ;
    USE SIGNAL ;
    SHAPE ABUTMENT ;
    PORT
      LAYER M4 ;
      RECT 0.000 1210.464 0.192 1210.488 ;
    END
  END rx[238]
  PIN rx[239]
    DIRECTION OUTPUT ;
    USE SIGNAL ;
    SHAPE ABUTMENT ;
    PORT
      LAYER M4 ;
      RECT 0.000 1212.048 0.192 1212.072 ;
    END
  END rx[239]
  PIN rx[240]
    DIRECTION OUTPUT ;
    USE SIGNAL ;
    SHAPE ABUTMENT ;
    PORT
      LAYER M4 ;
      RECT 0.000 1213.680 0.192 1213.704 ;
    END
  END rx[240]
  PIN rx[241]
    DIRECTION OUTPUT ;
    USE SIGNAL ;
    SHAPE ABUTMENT ;
    PORT
      LAYER M4 ;
      RECT 0.000 1215.264 0.192 1215.288 ;
    END
  END rx[241]
  PIN rx[242]
    DIRECTION OUTPUT ;
    USE SIGNAL ;
    SHAPE ABUTMENT ;
    PORT
      LAYER M4 ;
      RECT 0.000 1216.896 0.192 1216.920 ;
    END
  END rx[242]
  PIN rx[243]
    DIRECTION OUTPUT ;
    USE SIGNAL ;
    SHAPE ABUTMENT ;
    PORT
      LAYER M4 ;
      RECT 0.000 1218.528 0.192 1218.552 ;
    END
  END rx[243]
  PIN rx[244]
    DIRECTION OUTPUT ;
    USE SIGNAL ;
    SHAPE ABUTMENT ;
    PORT
      LAYER M4 ;
      RECT 0.000 1220.112 0.192 1220.136 ;
    END
  END rx[244]
  PIN rx[245]
    DIRECTION OUTPUT ;
    USE SIGNAL ;
    SHAPE ABUTMENT ;
    PORT
      LAYER M4 ;
      RECT 0.000 1221.744 0.192 1221.768 ;
    END
  END rx[245]
  PIN rx[246]
    DIRECTION OUTPUT ;
    USE SIGNAL ;
    SHAPE ABUTMENT ;
    PORT
      LAYER M4 ;
      RECT 0.000 1223.328 0.192 1223.352 ;
    END
  END rx[246]
  PIN rx[247]
    DIRECTION OUTPUT ;
    USE SIGNAL ;
    SHAPE ABUTMENT ;
    PORT
      LAYER M4 ;
      RECT 0.000 1224.960 0.192 1224.984 ;
    END
  END rx[247]
  PIN rx[248]
    DIRECTION OUTPUT ;
    USE SIGNAL ;
    SHAPE ABUTMENT ;
    PORT
      LAYER M4 ;
      RECT 0.000 1226.544 0.192 1226.568 ;
    END
  END rx[248]
  PIN rx[249]
    DIRECTION OUTPUT ;
    USE SIGNAL ;
    SHAPE ABUTMENT ;
    PORT
      LAYER M4 ;
      RECT 0.000 1228.176 0.192 1228.200 ;
    END
  END rx[249]
  PIN rx[250]
    DIRECTION OUTPUT ;
    USE SIGNAL ;
    SHAPE ABUTMENT ;
    PORT
      LAYER M4 ;
      RECT 0.000 1229.808 0.192 1229.832 ;
    END
  END rx[250]
  PIN rx[251]
    DIRECTION OUTPUT ;
    USE SIGNAL ;
    SHAPE ABUTMENT ;
    PORT
      LAYER M4 ;
      RECT 0.000 1231.392 0.192 1231.416 ;
    END
  END rx[251]
  PIN rx[252]
    DIRECTION OUTPUT ;
    USE SIGNAL ;
    SHAPE ABUTMENT ;
    PORT
      LAYER M4 ;
      RECT 0.000 1233.024 0.192 1233.048 ;
    END
  END rx[252]
  PIN rx[253]
    DIRECTION OUTPUT ;
    USE SIGNAL ;
    SHAPE ABUTMENT ;
    PORT
      LAYER M4 ;
      RECT 0.000 1234.608 0.192 1234.632 ;
    END
  END rx[253]
  PIN rx[254]
    DIRECTION OUTPUT ;
    USE SIGNAL ;
    SHAPE ABUTMENT ;
    PORT
      LAYER M4 ;
      RECT 0.000 1236.240 0.192 1236.264 ;
    END
  END rx[254]
  PIN rx[255]
    DIRECTION OUTPUT ;
    USE SIGNAL ;
    SHAPE ABUTMENT ;
    PORT
      LAYER M4 ;
      RECT 0.000 1237.824 0.192 1237.848 ;
    END
  END rx[255]
  PIN rx[256]
    DIRECTION OUTPUT ;
    USE SIGNAL ;
    SHAPE ABUTMENT ;
    PORT
      LAYER M4 ;
      RECT 0.000 1239.456 0.192 1239.480 ;
    END
  END rx[256]
  PIN rx[257]
    DIRECTION OUTPUT ;
    USE SIGNAL ;
    SHAPE ABUTMENT ;
    PORT
      LAYER M4 ;
      RECT 0.000 1241.040 0.192 1241.064 ;
    END
  END rx[257]
  PIN rx[258]
    DIRECTION OUTPUT ;
    USE SIGNAL ;
    SHAPE ABUTMENT ;
    PORT
      LAYER M4 ;
      RECT 0.000 1242.672 0.192 1242.696 ;
    END
  END rx[258]
  PIN rx[259]
    DIRECTION OUTPUT ;
    USE SIGNAL ;
    SHAPE ABUTMENT ;
    PORT
      LAYER M4 ;
      RECT 0.000 1244.304 0.192 1244.328 ;
    END
  END rx[259]
  PIN rx[260]
    DIRECTION OUTPUT ;
    USE SIGNAL ;
    SHAPE ABUTMENT ;
    PORT
      LAYER M4 ;
      RECT 0.000 1245.888 0.192 1245.912 ;
    END
  END rx[260]
  PIN rx[261]
    DIRECTION OUTPUT ;
    USE SIGNAL ;
    SHAPE ABUTMENT ;
    PORT
      LAYER M4 ;
      RECT 0.000 1247.520 0.192 1247.544 ;
    END
  END rx[261]
  PIN rx[262]
    DIRECTION OUTPUT ;
    USE SIGNAL ;
    SHAPE ABUTMENT ;
    PORT
      LAYER M4 ;
      RECT 0.000 1249.104 0.192 1249.128 ;
    END
  END rx[262]
  PIN rx[263]
    DIRECTION OUTPUT ;
    USE SIGNAL ;
    SHAPE ABUTMENT ;
    PORT
      LAYER M4 ;
      RECT 0.000 1250.736 0.192 1250.760 ;
    END
  END rx[263]
  PIN rx[264]
    DIRECTION OUTPUT ;
    USE SIGNAL ;
    SHAPE ABUTMENT ;
    PORT
      LAYER M4 ;
      RECT 0.000 1252.320 0.192 1252.344 ;
    END
  END rx[264]
  PIN rx[265]
    DIRECTION OUTPUT ;
    USE SIGNAL ;
    SHAPE ABUTMENT ;
    PORT
      LAYER M4 ;
      RECT 0.000 1253.952 0.192 1253.976 ;
    END
  END rx[265]
  PIN rx[266]
    DIRECTION OUTPUT ;
    USE SIGNAL ;
    SHAPE ABUTMENT ;
    PORT
      LAYER M4 ;
      RECT 0.000 1255.584 0.192 1255.608 ;
    END
  END rx[266]
  PIN rx[267]
    DIRECTION OUTPUT ;
    USE SIGNAL ;
    SHAPE ABUTMENT ;
    PORT
      LAYER M4 ;
      RECT 0.000 1257.168 0.192 1257.192 ;
    END
  END rx[267]
  PIN rx[268]
    DIRECTION OUTPUT ;
    USE SIGNAL ;
    SHAPE ABUTMENT ;
    PORT
      LAYER M4 ;
      RECT 0.000 1258.800 0.192 1258.824 ;
    END
  END rx[268]
  PIN rx[269]
    DIRECTION OUTPUT ;
    USE SIGNAL ;
    SHAPE ABUTMENT ;
    PORT
      LAYER M4 ;
      RECT 0.000 1260.384 0.192 1260.408 ;
    END
  END rx[269]
  PIN rx[270]
    DIRECTION OUTPUT ;
    USE SIGNAL ;
    SHAPE ABUTMENT ;
    PORT
      LAYER M4 ;
      RECT 0.000 1262.016 0.192 1262.040 ;
    END
  END rx[270]
  PIN rx[271]
    DIRECTION OUTPUT ;
    USE SIGNAL ;
    SHAPE ABUTMENT ;
    PORT
      LAYER M4 ;
      RECT 0.000 1263.600 0.192 1263.624 ;
    END
  END rx[271]
  PIN rx[272]
    DIRECTION OUTPUT ;
    USE SIGNAL ;
    SHAPE ABUTMENT ;
    PORT
      LAYER M4 ;
      RECT 0.000 1265.232 0.192 1265.256 ;
    END
  END rx[272]
  PIN rx[273]
    DIRECTION OUTPUT ;
    USE SIGNAL ;
    SHAPE ABUTMENT ;
    PORT
      LAYER M4 ;
      RECT 0.000 1266.816 0.192 1266.840 ;
    END
  END rx[273]
  PIN rx[274]
    DIRECTION OUTPUT ;
    USE SIGNAL ;
    SHAPE ABUTMENT ;
    PORT
      LAYER M4 ;
      RECT 0.000 1268.448 0.192 1268.472 ;
    END
  END rx[274]
  PIN rx[275]
    DIRECTION OUTPUT ;
    USE SIGNAL ;
    SHAPE ABUTMENT ;
    PORT
      LAYER M4 ;
      RECT 0.000 1270.080 0.192 1270.104 ;
    END
  END rx[275]
  PIN rx[276]
    DIRECTION OUTPUT ;
    USE SIGNAL ;
    SHAPE ABUTMENT ;
    PORT
      LAYER M4 ;
      RECT 0.000 1271.664 0.192 1271.688 ;
    END
  END rx[276]
  PIN rx[277]
    DIRECTION OUTPUT ;
    USE SIGNAL ;
    SHAPE ABUTMENT ;
    PORT
      LAYER M4 ;
      RECT 0.000 1273.296 0.192 1273.320 ;
    END
  END rx[277]
  PIN rx[278]
    DIRECTION OUTPUT ;
    USE SIGNAL ;
    SHAPE ABUTMENT ;
    PORT
      LAYER M4 ;
      RECT 0.000 1274.880 0.192 1274.904 ;
    END
  END rx[278]
  PIN rx[279]
    DIRECTION OUTPUT ;
    USE SIGNAL ;
    SHAPE ABUTMENT ;
    PORT
      LAYER M4 ;
      RECT 0.000 1276.512 0.192 1276.536 ;
    END
  END rx[279]
  PIN rx[280]
    DIRECTION OUTPUT ;
    USE SIGNAL ;
    SHAPE ABUTMENT ;
    PORT
      LAYER M4 ;
      RECT 0.000 1278.096 0.192 1278.120 ;
    END
  END rx[280]
  PIN rx[281]
    DIRECTION OUTPUT ;
    USE SIGNAL ;
    SHAPE ABUTMENT ;
    PORT
      LAYER M4 ;
      RECT 0.000 1279.728 0.192 1279.752 ;
    END
  END rx[281]
  PIN rx[282]
    DIRECTION OUTPUT ;
    USE SIGNAL ;
    SHAPE ABUTMENT ;
    PORT
      LAYER M4 ;
      RECT 0.000 1281.360 0.192 1281.384 ;
    END
  END rx[282]
  PIN rx[283]
    DIRECTION OUTPUT ;
    USE SIGNAL ;
    SHAPE ABUTMENT ;
    PORT
      LAYER M4 ;
      RECT 0.000 1282.944 0.192 1282.968 ;
    END
  END rx[283]
  PIN rx[284]
    DIRECTION OUTPUT ;
    USE SIGNAL ;
    SHAPE ABUTMENT ;
    PORT
      LAYER M4 ;
      RECT 0.000 1284.576 0.192 1284.600 ;
    END
  END rx[284]
  PIN rx[285]
    DIRECTION OUTPUT ;
    USE SIGNAL ;
    SHAPE ABUTMENT ;
    PORT
      LAYER M4 ;
      RECT 0.000 1286.160 0.192 1286.184 ;
    END
  END rx[285]
  PIN rx[286]
    DIRECTION OUTPUT ;
    USE SIGNAL ;
    SHAPE ABUTMENT ;
    PORT
      LAYER M4 ;
      RECT 0.000 1287.792 0.192 1287.816 ;
    END
  END rx[286]
  PIN rx[287]
    DIRECTION OUTPUT ;
    USE SIGNAL ;
    SHAPE ABUTMENT ;
    PORT
      LAYER M4 ;
      RECT 0.000 1289.376 0.192 1289.400 ;
    END
  END rx[287]
  PIN rx[288]
    DIRECTION OUTPUT ;
    USE SIGNAL ;
    SHAPE ABUTMENT ;
    PORT
      LAYER M4 ;
      RECT 0.000 1291.008 0.192 1291.032 ;
    END
  END rx[288]
  PIN rx[289]
    DIRECTION OUTPUT ;
    USE SIGNAL ;
    SHAPE ABUTMENT ;
    PORT
      LAYER M4 ;
      RECT 0.000 1292.640 0.192 1292.664 ;
    END
  END rx[289]
  PIN rx[290]
    DIRECTION OUTPUT ;
    USE SIGNAL ;
    SHAPE ABUTMENT ;
    PORT
      LAYER M4 ;
      RECT 0.000 1294.224 0.192 1294.248 ;
    END
  END rx[290]
  PIN rx[291]
    DIRECTION OUTPUT ;
    USE SIGNAL ;
    SHAPE ABUTMENT ;
    PORT
      LAYER M4 ;
      RECT 0.000 1295.856 0.192 1295.880 ;
    END
  END rx[291]
  PIN rx[292]
    DIRECTION OUTPUT ;
    USE SIGNAL ;
    SHAPE ABUTMENT ;
    PORT
      LAYER M4 ;
      RECT 0.000 1297.440 0.192 1297.464 ;
    END
  END rx[292]
  PIN rx[293]
    DIRECTION OUTPUT ;
    USE SIGNAL ;
    SHAPE ABUTMENT ;
    PORT
      LAYER M4 ;
      RECT 0.000 1299.072 0.192 1299.096 ;
    END
  END rx[293]
  PIN rx[294]
    DIRECTION OUTPUT ;
    USE SIGNAL ;
    SHAPE ABUTMENT ;
    PORT
      LAYER M4 ;
      RECT 0.000 1300.656 0.192 1300.680 ;
    END
  END rx[294]
  PIN rx[295]
    DIRECTION OUTPUT ;
    USE SIGNAL ;
    SHAPE ABUTMENT ;
    PORT
      LAYER M4 ;
      RECT 0.000 1302.288 0.192 1302.312 ;
    END
  END rx[295]
  PIN rx[296]
    DIRECTION OUTPUT ;
    USE SIGNAL ;
    SHAPE ABUTMENT ;
    PORT
      LAYER M4 ;
      RECT 0.000 1303.872 0.192 1303.896 ;
    END
  END rx[296]
  PIN rx[297]
    DIRECTION OUTPUT ;
    USE SIGNAL ;
    SHAPE ABUTMENT ;
    PORT
      LAYER M4 ;
      RECT 0.000 1305.504 0.192 1305.528 ;
    END
  END rx[297]
  PIN rx[298]
    DIRECTION OUTPUT ;
    USE SIGNAL ;
    SHAPE ABUTMENT ;
    PORT
      LAYER M4 ;
      RECT 0.000 1307.136 0.192 1307.160 ;
    END
  END rx[298]
  PIN rx[299]
    DIRECTION OUTPUT ;
    USE SIGNAL ;
    SHAPE ABUTMENT ;
    PORT
      LAYER M4 ;
      RECT 0.000 1308.720 0.192 1308.744 ;
    END
  END rx[299]
  PIN rx[300]
    DIRECTION OUTPUT ;
    USE SIGNAL ;
    SHAPE ABUTMENT ;
    PORT
      LAYER M4 ;
      RECT 0.000 1310.352 0.192 1310.376 ;
    END
  END rx[300]
  PIN rx[301]
    DIRECTION OUTPUT ;
    USE SIGNAL ;
    SHAPE ABUTMENT ;
    PORT
      LAYER M4 ;
      RECT 0.000 1311.936 0.192 1311.960 ;
    END
  END rx[301]
  PIN rx[302]
    DIRECTION OUTPUT ;
    USE SIGNAL ;
    SHAPE ABUTMENT ;
    PORT
      LAYER M4 ;
      RECT 0.000 1313.568 0.192 1313.592 ;
    END
  END rx[302]
  PIN rx[303]
    DIRECTION OUTPUT ;
    USE SIGNAL ;
    SHAPE ABUTMENT ;
    PORT
      LAYER M4 ;
      RECT 0.000 1315.152 0.192 1315.176 ;
    END
  END rx[303]
  PIN rx[304]
    DIRECTION OUTPUT ;
    USE SIGNAL ;
    SHAPE ABUTMENT ;
    PORT
      LAYER M4 ;
      RECT 0.000 1316.784 0.192 1316.808 ;
    END
  END rx[304]
  PIN rx[305]
    DIRECTION OUTPUT ;
    USE SIGNAL ;
    SHAPE ABUTMENT ;
    PORT
      LAYER M4 ;
      RECT 0.000 1318.416 0.192 1318.440 ;
    END
  END rx[305]
  PIN rx[306]
    DIRECTION OUTPUT ;
    USE SIGNAL ;
    SHAPE ABUTMENT ;
    PORT
      LAYER M4 ;
      RECT 0.000 1320.000 0.192 1320.024 ;
    END
  END rx[306]
  PIN rx[307]
    DIRECTION OUTPUT ;
    USE SIGNAL ;
    SHAPE ABUTMENT ;
    PORT
      LAYER M4 ;
      RECT 0.000 1321.632 0.192 1321.656 ;
    END
  END rx[307]
  PIN rx[308]
    DIRECTION OUTPUT ;
    USE SIGNAL ;
    SHAPE ABUTMENT ;
    PORT
      LAYER M4 ;
      RECT 0.000 1323.216 0.192 1323.240 ;
    END
  END rx[308]
  PIN rx[309]
    DIRECTION OUTPUT ;
    USE SIGNAL ;
    SHAPE ABUTMENT ;
    PORT
      LAYER M4 ;
      RECT 0.000 1324.848 0.192 1324.872 ;
    END
  END rx[309]
  PIN rx[310]
    DIRECTION OUTPUT ;
    USE SIGNAL ;
    SHAPE ABUTMENT ;
    PORT
      LAYER M4 ;
      RECT 0.000 1326.432 0.192 1326.456 ;
    END
  END rx[310]
  PIN rx[311]
    DIRECTION OUTPUT ;
    USE SIGNAL ;
    SHAPE ABUTMENT ;
    PORT
      LAYER M4 ;
      RECT 0.000 1328.064 0.192 1328.088 ;
    END
  END rx[311]
  PIN rx[312]
    DIRECTION OUTPUT ;
    USE SIGNAL ;
    SHAPE ABUTMENT ;
    PORT
      LAYER M4 ;
      RECT 0.000 1329.696 0.192 1329.720 ;
    END
  END rx[312]
  PIN rx[313]
    DIRECTION OUTPUT ;
    USE SIGNAL ;
    SHAPE ABUTMENT ;
    PORT
      LAYER M4 ;
      RECT 0.000 1331.280 0.192 1331.304 ;
    END
  END rx[313]
  PIN rx[314]
    DIRECTION OUTPUT ;
    USE SIGNAL ;
    SHAPE ABUTMENT ;
    PORT
      LAYER M4 ;
      RECT 0.000 1332.912 0.192 1332.936 ;
    END
  END rx[314]
  PIN rx[315]
    DIRECTION OUTPUT ;
    USE SIGNAL ;
    SHAPE ABUTMENT ;
    PORT
      LAYER M4 ;
      RECT 0.000 1334.496 0.192 1334.520 ;
    END
  END rx[315]
  PIN rx[316]
    DIRECTION OUTPUT ;
    USE SIGNAL ;
    SHAPE ABUTMENT ;
    PORT
      LAYER M4 ;
      RECT 0.000 1336.128 0.192 1336.152 ;
    END
  END rx[316]
  PIN rx[317]
    DIRECTION OUTPUT ;
    USE SIGNAL ;
    SHAPE ABUTMENT ;
    PORT
      LAYER M4 ;
      RECT 0.000 1337.712 0.192 1337.736 ;
    END
  END rx[317]
  PIN rx[318]
    DIRECTION OUTPUT ;
    USE SIGNAL ;
    SHAPE ABUTMENT ;
    PORT
      LAYER M4 ;
      RECT 0.000 1339.344 0.192 1339.368 ;
    END
  END rx[318]
  PIN rx[319]
    DIRECTION OUTPUT ;
    USE SIGNAL ;
    SHAPE ABUTMENT ;
    PORT
      LAYER M4 ;
      RECT 0.000 1340.928 0.192 1340.952 ;
    END
  END rx[319]
  PIN rx[320]
    DIRECTION OUTPUT ;
    USE SIGNAL ;
    SHAPE ABUTMENT ;
    PORT
      LAYER M4 ;
      RECT 0.000 1342.560 0.192 1342.584 ;
    END
  END rx[320]
  PIN rx[321]
    DIRECTION OUTPUT ;
    USE SIGNAL ;
    SHAPE ABUTMENT ;
    PORT
      LAYER M4 ;
      RECT 0.000 1344.192 0.192 1344.216 ;
    END
  END rx[321]
  PIN rx[322]
    DIRECTION OUTPUT ;
    USE SIGNAL ;
    SHAPE ABUTMENT ;
    PORT
      LAYER M4 ;
      RECT 0.000 1345.776 0.192 1345.800 ;
    END
  END rx[322]
  PIN rx[323]
    DIRECTION OUTPUT ;
    USE SIGNAL ;
    SHAPE ABUTMENT ;
    PORT
      LAYER M4 ;
      RECT 0.000 1347.408 0.192 1347.432 ;
    END
  END rx[323]
  PIN rx[324]
    DIRECTION OUTPUT ;
    USE SIGNAL ;
    SHAPE ABUTMENT ;
    PORT
      LAYER M4 ;
      RECT 0.000 1348.992 0.192 1349.016 ;
    END
  END rx[324]
  PIN rx[325]
    DIRECTION OUTPUT ;
    USE SIGNAL ;
    SHAPE ABUTMENT ;
    PORT
      LAYER M4 ;
      RECT 0.000 1350.624 0.192 1350.648 ;
    END
  END rx[325]
  PIN rx[326]
    DIRECTION OUTPUT ;
    USE SIGNAL ;
    SHAPE ABUTMENT ;
    PORT
      LAYER M4 ;
      RECT 0.000 1352.208 0.192 1352.232 ;
    END
  END rx[326]
  PIN rx[327]
    DIRECTION OUTPUT ;
    USE SIGNAL ;
    SHAPE ABUTMENT ;
    PORT
      LAYER M4 ;
      RECT 0.000 1353.840 0.192 1353.864 ;
    END
  END rx[327]
  PIN rx[328]
    DIRECTION OUTPUT ;
    USE SIGNAL ;
    SHAPE ABUTMENT ;
    PORT
      LAYER M4 ;
      RECT 0.000 1355.472 0.192 1355.496 ;
    END
  END rx[328]
  PIN rx[329]
    DIRECTION OUTPUT ;
    USE SIGNAL ;
    SHAPE ABUTMENT ;
    PORT
      LAYER M4 ;
      RECT 0.000 1357.056 0.192 1357.080 ;
    END
  END rx[329]
  PIN rx[330]
    DIRECTION OUTPUT ;
    USE SIGNAL ;
    SHAPE ABUTMENT ;
    PORT
      LAYER M4 ;
      RECT 0.000 1358.688 0.192 1358.712 ;
    END
  END rx[330]
  PIN rx[331]
    DIRECTION OUTPUT ;
    USE SIGNAL ;
    SHAPE ABUTMENT ;
    PORT
      LAYER M4 ;
      RECT 0.000 1360.272 0.192 1360.296 ;
    END
  END rx[331]
  PIN rx[332]
    DIRECTION OUTPUT ;
    USE SIGNAL ;
    SHAPE ABUTMENT ;
    PORT
      LAYER M4 ;
      RECT 0.000 1361.904 0.192 1361.928 ;
    END
  END rx[332]
  PIN rx[333]
    DIRECTION OUTPUT ;
    USE SIGNAL ;
    SHAPE ABUTMENT ;
    PORT
      LAYER M4 ;
      RECT 0.000 1363.488 0.192 1363.512 ;
    END
  END rx[333]
  PIN rx[334]
    DIRECTION OUTPUT ;
    USE SIGNAL ;
    SHAPE ABUTMENT ;
    PORT
      LAYER M4 ;
      RECT 0.000 1365.120 0.192 1365.144 ;
    END
  END rx[334]
  PIN rx[335]
    DIRECTION OUTPUT ;
    USE SIGNAL ;
    SHAPE ABUTMENT ;
    PORT
      LAYER M4 ;
      RECT 0.000 1366.752 0.192 1366.776 ;
    END
  END rx[335]
  PIN rx[336]
    DIRECTION OUTPUT ;
    USE SIGNAL ;
    SHAPE ABUTMENT ;
    PORT
      LAYER M4 ;
      RECT 0.000 1368.336 0.192 1368.360 ;
    END
  END rx[336]
  PIN rx[337]
    DIRECTION OUTPUT ;
    USE SIGNAL ;
    SHAPE ABUTMENT ;
    PORT
      LAYER M4 ;
      RECT 0.000 1369.968 0.192 1369.992 ;
    END
  END rx[337]
  PIN rx[338]
    DIRECTION OUTPUT ;
    USE SIGNAL ;
    SHAPE ABUTMENT ;
    PORT
      LAYER M4 ;
      RECT 0.000 1371.552 0.192 1371.576 ;
    END
  END rx[338]
  PIN rx[339]
    DIRECTION OUTPUT ;
    USE SIGNAL ;
    SHAPE ABUTMENT ;
    PORT
      LAYER M4 ;
      RECT 0.000 1373.184 0.192 1373.208 ;
    END
  END rx[339]
  PIN rx[340]
    DIRECTION OUTPUT ;
    USE SIGNAL ;
    SHAPE ABUTMENT ;
    PORT
      LAYER M4 ;
      RECT 0.000 1374.768 0.192 1374.792 ;
    END
  END rx[340]
  PIN rx[341]
    DIRECTION OUTPUT ;
    USE SIGNAL ;
    SHAPE ABUTMENT ;
    PORT
      LAYER M4 ;
      RECT 0.000 1376.400 0.192 1376.424 ;
    END
  END rx[341]
  PIN rx[342]
    DIRECTION OUTPUT ;
    USE SIGNAL ;
    SHAPE ABUTMENT ;
    PORT
      LAYER M4 ;
      RECT 0.000 1377.984 0.192 1378.008 ;
    END
  END rx[342]
  PIN rx[343]
    DIRECTION OUTPUT ;
    USE SIGNAL ;
    SHAPE ABUTMENT ;
    PORT
      LAYER M4 ;
      RECT 0.000 1379.616 0.192 1379.640 ;
    END
  END rx[343]
  PIN rx[344]
    DIRECTION OUTPUT ;
    USE SIGNAL ;
    SHAPE ABUTMENT ;
    PORT
      LAYER M4 ;
      RECT 0.000 1381.248 0.192 1381.272 ;
    END
  END rx[344]
  PIN rx[345]
    DIRECTION OUTPUT ;
    USE SIGNAL ;
    SHAPE ABUTMENT ;
    PORT
      LAYER M4 ;
      RECT 0.000 1382.832 0.192 1382.856 ;
    END
  END rx[345]
  PIN rx[346]
    DIRECTION OUTPUT ;
    USE SIGNAL ;
    SHAPE ABUTMENT ;
    PORT
      LAYER M4 ;
      RECT 0.000 1384.464 0.192 1384.488 ;
    END
  END rx[346]
  PIN rx[347]
    DIRECTION OUTPUT ;
    USE SIGNAL ;
    SHAPE ABUTMENT ;
    PORT
      LAYER M4 ;
      RECT 0.000 1386.048 0.192 1386.072 ;
    END
  END rx[347]
  PIN rx[348]
    DIRECTION OUTPUT ;
    USE SIGNAL ;
    SHAPE ABUTMENT ;
    PORT
      LAYER M4 ;
      RECT 0.000 1387.680 0.192 1387.704 ;
    END
  END rx[348]
  PIN rx[349]
    DIRECTION OUTPUT ;
    USE SIGNAL ;
    SHAPE ABUTMENT ;
    PORT
      LAYER M4 ;
      RECT 0.000 1389.264 0.192 1389.288 ;
    END
  END rx[349]
  PIN rx[350]
    DIRECTION OUTPUT ;
    USE SIGNAL ;
    SHAPE ABUTMENT ;
    PORT
      LAYER M4 ;
      RECT 0.000 1390.896 0.192 1390.920 ;
    END
  END rx[350]
  PIN rx[351]
    DIRECTION OUTPUT ;
    USE SIGNAL ;
    SHAPE ABUTMENT ;
    PORT
      LAYER M4 ;
      RECT 0.000 1392.528 0.192 1392.552 ;
    END
  END rx[351]
  PIN rx[352]
    DIRECTION OUTPUT ;
    USE SIGNAL ;
    SHAPE ABUTMENT ;
    PORT
      LAYER M4 ;
      RECT 0.000 1394.112 0.192 1394.136 ;
    END
  END rx[352]
  PIN rx[353]
    DIRECTION OUTPUT ;
    USE SIGNAL ;
    SHAPE ABUTMENT ;
    PORT
      LAYER M4 ;
      RECT 0.000 1395.744 0.192 1395.768 ;
    END
  END rx[353]
  PIN rx[354]
    DIRECTION OUTPUT ;
    USE SIGNAL ;
    SHAPE ABUTMENT ;
    PORT
      LAYER M4 ;
      RECT 0.000 1397.328 0.192 1397.352 ;
    END
  END rx[354]
  PIN rx[355]
    DIRECTION OUTPUT ;
    USE SIGNAL ;
    SHAPE ABUTMENT ;
    PORT
      LAYER M4 ;
      RECT 0.000 1398.960 0.192 1398.984 ;
    END
  END rx[355]
  PIN rx[356]
    DIRECTION OUTPUT ;
    USE SIGNAL ;
    SHAPE ABUTMENT ;
    PORT
      LAYER M4 ;
      RECT 0.000 1400.544 0.192 1400.568 ;
    END
  END rx[356]
  PIN rx[357]
    DIRECTION OUTPUT ;
    USE SIGNAL ;
    SHAPE ABUTMENT ;
    PORT
      LAYER M4 ;
      RECT 0.000 1402.176 0.192 1402.200 ;
    END
  END rx[357]
  PIN rx[358]
    DIRECTION OUTPUT ;
    USE SIGNAL ;
    SHAPE ABUTMENT ;
    PORT
      LAYER M4 ;
      RECT 0.000 1403.808 0.192 1403.832 ;
    END
  END rx[358]
  PIN rx[359]
    DIRECTION OUTPUT ;
    USE SIGNAL ;
    SHAPE ABUTMENT ;
    PORT
      LAYER M4 ;
      RECT 0.000 1405.392 0.192 1405.416 ;
    END
  END rx[359]
  PIN rx[360]
    DIRECTION OUTPUT ;
    USE SIGNAL ;
    SHAPE ABUTMENT ;
    PORT
      LAYER M4 ;
      RECT 0.000 1407.024 0.192 1407.048 ;
    END
  END rx[360]
  PIN rx[361]
    DIRECTION OUTPUT ;
    USE SIGNAL ;
    SHAPE ABUTMENT ;
    PORT
      LAYER M4 ;
      RECT 0.000 1408.608 0.192 1408.632 ;
    END
  END rx[361]
  PIN rx[362]
    DIRECTION OUTPUT ;
    USE SIGNAL ;
    SHAPE ABUTMENT ;
    PORT
      LAYER M4 ;
      RECT 0.000 1410.240 0.192 1410.264 ;
    END
  END rx[362]
  PIN rx[363]
    DIRECTION OUTPUT ;
    USE SIGNAL ;
    SHAPE ABUTMENT ;
    PORT
      LAYER M4 ;
      RECT 0.000 1411.824 0.192 1411.848 ;
    END
  END rx[363]
  PIN rx[364]
    DIRECTION OUTPUT ;
    USE SIGNAL ;
    SHAPE ABUTMENT ;
    PORT
      LAYER M4 ;
      RECT 0.000 1413.456 0.192 1413.480 ;
    END
  END rx[364]
  PIN rx[365]
    DIRECTION OUTPUT ;
    USE SIGNAL ;
    SHAPE ABUTMENT ;
    PORT
      LAYER M4 ;
      RECT 0.000 1415.040 0.192 1415.064 ;
    END
  END rx[365]
  PIN rx[366]
    DIRECTION OUTPUT ;
    USE SIGNAL ;
    SHAPE ABUTMENT ;
    PORT
      LAYER M4 ;
      RECT 0.000 1416.672 0.192 1416.696 ;
    END
  END rx[366]
  PIN rx[367]
    DIRECTION OUTPUT ;
    USE SIGNAL ;
    SHAPE ABUTMENT ;
    PORT
      LAYER M4 ;
      RECT 0.000 1418.304 0.192 1418.328 ;
    END
  END rx[367]
  PIN rx[368]
    DIRECTION OUTPUT ;
    USE SIGNAL ;
    SHAPE ABUTMENT ;
    PORT
      LAYER M4 ;
      RECT 0.000 1419.888 0.192 1419.912 ;
    END
  END rx[368]
  PIN rx[369]
    DIRECTION OUTPUT ;
    USE SIGNAL ;
    SHAPE ABUTMENT ;
    PORT
      LAYER M4 ;
      RECT 0.000 1421.520 0.192 1421.544 ;
    END
  END rx[369]
  PIN rx[370]
    DIRECTION OUTPUT ;
    USE SIGNAL ;
    SHAPE ABUTMENT ;
    PORT
      LAYER M4 ;
      RECT 0.000 1423.104 0.192 1423.128 ;
    END
  END rx[370]
  PIN rx[371]
    DIRECTION OUTPUT ;
    USE SIGNAL ;
    SHAPE ABUTMENT ;
    PORT
      LAYER M4 ;
      RECT 0.000 1424.736 0.192 1424.760 ;
    END
  END rx[371]
  PIN rx[372]
    DIRECTION OUTPUT ;
    USE SIGNAL ;
    SHAPE ABUTMENT ;
    PORT
      LAYER M4 ;
      RECT 0.000 1426.320 0.192 1426.344 ;
    END
  END rx[372]
  PIN rx[373]
    DIRECTION OUTPUT ;
    USE SIGNAL ;
    SHAPE ABUTMENT ;
    PORT
      LAYER M4 ;
      RECT 0.000 1427.952 0.192 1427.976 ;
    END
  END rx[373]
  PIN rx[374]
    DIRECTION OUTPUT ;
    USE SIGNAL ;
    SHAPE ABUTMENT ;
    PORT
      LAYER M4 ;
      RECT 0.000 1429.584 0.192 1429.608 ;
    END
  END rx[374]
  PIN rx[375]
    DIRECTION OUTPUT ;
    USE SIGNAL ;
    SHAPE ABUTMENT ;
    PORT
      LAYER M4 ;
      RECT 0.000 1431.168 0.192 1431.192 ;
    END
  END rx[375]
  PIN rx[376]
    DIRECTION OUTPUT ;
    USE SIGNAL ;
    SHAPE ABUTMENT ;
    PORT
      LAYER M4 ;
      RECT 0.000 1432.800 0.192 1432.824 ;
    END
  END rx[376]
  PIN rx[377]
    DIRECTION OUTPUT ;
    USE SIGNAL ;
    SHAPE ABUTMENT ;
    PORT
      LAYER M4 ;
      RECT 0.000 1434.384 0.192 1434.408 ;
    END
  END rx[377]
  PIN rx[378]
    DIRECTION OUTPUT ;
    USE SIGNAL ;
    SHAPE ABUTMENT ;
    PORT
      LAYER M4 ;
      RECT 0.000 1436.016 0.192 1436.040 ;
    END
  END rx[378]
  PIN rx[379]
    DIRECTION OUTPUT ;
    USE SIGNAL ;
    SHAPE ABUTMENT ;
    PORT
      LAYER M4 ;
      RECT 0.000 1437.600 0.192 1437.624 ;
    END
  END rx[379]
  PIN rx[380]
    DIRECTION OUTPUT ;
    USE SIGNAL ;
    SHAPE ABUTMENT ;
    PORT
      LAYER M4 ;
      RECT 0.000 1439.232 0.192 1439.256 ;
    END
  END rx[380]
  PIN rx[381]
    DIRECTION OUTPUT ;
    USE SIGNAL ;
    SHAPE ABUTMENT ;
    PORT
      LAYER M4 ;
      RECT 0.000 1440.864 0.192 1440.888 ;
    END
  END rx[381]
  PIN rx[382]
    DIRECTION OUTPUT ;
    USE SIGNAL ;
    SHAPE ABUTMENT ;
    PORT
      LAYER M4 ;
      RECT 0.000 1442.448 0.192 1442.472 ;
    END
  END rx[382]
  PIN rx[383]
    DIRECTION OUTPUT ;
    USE SIGNAL ;
    SHAPE ABUTMENT ;
    PORT
      LAYER M4 ;
      RECT 0.000 1444.080 0.192 1444.104 ;
    END
  END rx[383]
  PIN rx[384]
    DIRECTION OUTPUT ;
    USE SIGNAL ;
    SHAPE ABUTMENT ;
    PORT
      LAYER M4 ;
      RECT 0.000 1445.664 0.192 1445.688 ;
    END
  END rx[384]
  PIN rx[385]
    DIRECTION OUTPUT ;
    USE SIGNAL ;
    SHAPE ABUTMENT ;
    PORT
      LAYER M4 ;
      RECT 0.000 1447.296 0.192 1447.320 ;
    END
  END rx[385]
  PIN rx[386]
    DIRECTION OUTPUT ;
    USE SIGNAL ;
    SHAPE ABUTMENT ;
    PORT
      LAYER M4 ;
      RECT 0.000 1448.880 0.192 1448.904 ;
    END
  END rx[386]
  PIN rx[387]
    DIRECTION OUTPUT ;
    USE SIGNAL ;
    SHAPE ABUTMENT ;
    PORT
      LAYER M4 ;
      RECT 0.000 1450.512 0.192 1450.536 ;
    END
  END rx[387]
  PIN rx[388]
    DIRECTION OUTPUT ;
    USE SIGNAL ;
    SHAPE ABUTMENT ;
    PORT
      LAYER M4 ;
      RECT 0.000 1452.096 0.192 1452.120 ;
    END
  END rx[388]
  PIN rx[389]
    DIRECTION OUTPUT ;
    USE SIGNAL ;
    SHAPE ABUTMENT ;
    PORT
      LAYER M4 ;
      RECT 0.000 1453.728 0.192 1453.752 ;
    END
  END rx[389]
  PIN rx[390]
    DIRECTION OUTPUT ;
    USE SIGNAL ;
    SHAPE ABUTMENT ;
    PORT
      LAYER M4 ;
      RECT 0.000 1455.360 0.192 1455.384 ;
    END
  END rx[390]
  PIN rx[391]
    DIRECTION OUTPUT ;
    USE SIGNAL ;
    SHAPE ABUTMENT ;
    PORT
      LAYER M4 ;
      RECT 0.000 1456.944 0.192 1456.968 ;
    END
  END rx[391]
  PIN rx[392]
    DIRECTION OUTPUT ;
    USE SIGNAL ;
    SHAPE ABUTMENT ;
    PORT
      LAYER M4 ;
      RECT 0.000 1458.576 0.192 1458.600 ;
    END
  END rx[392]
  PIN rx[393]
    DIRECTION OUTPUT ;
    USE SIGNAL ;
    SHAPE ABUTMENT ;
    PORT
      LAYER M4 ;
      RECT 0.000 1460.160 0.192 1460.184 ;
    END
  END rx[393]
  PIN rx[394]
    DIRECTION OUTPUT ;
    USE SIGNAL ;
    SHAPE ABUTMENT ;
    PORT
      LAYER M4 ;
      RECT 0.000 1461.792 0.192 1461.816 ;
    END
  END rx[394]
  PIN rx[395]
    DIRECTION OUTPUT ;
    USE SIGNAL ;
    SHAPE ABUTMENT ;
    PORT
      LAYER M4 ;
      RECT 0.000 1463.376 0.192 1463.400 ;
    END
  END rx[395]
  PIN rx[396]
    DIRECTION OUTPUT ;
    USE SIGNAL ;
    SHAPE ABUTMENT ;
    PORT
      LAYER M4 ;
      RECT 0.000 1465.008 0.192 1465.032 ;
    END
  END rx[396]
  PIN rx[397]
    DIRECTION OUTPUT ;
    USE SIGNAL ;
    SHAPE ABUTMENT ;
    PORT
      LAYER M4 ;
      RECT 0.000 1466.640 0.192 1466.664 ;
    END
  END rx[397]
  PIN rx[398]
    DIRECTION OUTPUT ;
    USE SIGNAL ;
    SHAPE ABUTMENT ;
    PORT
      LAYER M4 ;
      RECT 0.000 1468.224 0.192 1468.248 ;
    END
  END rx[398]
  PIN rx[399]
    DIRECTION OUTPUT ;
    USE SIGNAL ;
    SHAPE ABUTMENT ;
    PORT
      LAYER M4 ;
      RECT 0.000 1469.856 0.192 1469.880 ;
    END
  END rx[399]
  PIN rx[400]
    DIRECTION OUTPUT ;
    USE SIGNAL ;
    SHAPE ABUTMENT ;
    PORT
      LAYER M4 ;
      RECT 0.000 1471.440 0.192 1471.464 ;
    END
  END rx[400]
  PIN rx[401]
    DIRECTION OUTPUT ;
    USE SIGNAL ;
    SHAPE ABUTMENT ;
    PORT
      LAYER M4 ;
      RECT 0.000 1473.072 0.192 1473.096 ;
    END
  END rx[401]
  PIN rx[402]
    DIRECTION OUTPUT ;
    USE SIGNAL ;
    SHAPE ABUTMENT ;
    PORT
      LAYER M4 ;
      RECT 0.000 1474.656 0.192 1474.680 ;
    END
  END rx[402]
  PIN rx[403]
    DIRECTION OUTPUT ;
    USE SIGNAL ;
    SHAPE ABUTMENT ;
    PORT
      LAYER M4 ;
      RECT 0.000 1476.288 0.192 1476.312 ;
    END
  END rx[403]
  PIN rx[404]
    DIRECTION OUTPUT ;
    USE SIGNAL ;
    SHAPE ABUTMENT ;
    PORT
      LAYER M4 ;
      RECT 0.000 1477.872 0.192 1477.896 ;
    END
  END rx[404]
  PIN rx[405]
    DIRECTION OUTPUT ;
    USE SIGNAL ;
    SHAPE ABUTMENT ;
    PORT
      LAYER M4 ;
      RECT 0.000 1479.504 0.192 1479.528 ;
    END
  END rx[405]
  PIN rx[406]
    DIRECTION OUTPUT ;
    USE SIGNAL ;
    SHAPE ABUTMENT ;
    PORT
      LAYER M4 ;
      RECT 0.000 1481.136 0.192 1481.160 ;
    END
  END rx[406]
  PIN rx[407]
    DIRECTION OUTPUT ;
    USE SIGNAL ;
    SHAPE ABUTMENT ;
    PORT
      LAYER M4 ;
      RECT 0.000 1482.720 0.192 1482.744 ;
    END
  END rx[407]
  PIN rx[408]
    DIRECTION OUTPUT ;
    USE SIGNAL ;
    SHAPE ABUTMENT ;
    PORT
      LAYER M4 ;
      RECT 0.000 1484.352 0.192 1484.376 ;
    END
  END rx[408]
  PIN rx[409]
    DIRECTION OUTPUT ;
    USE SIGNAL ;
    SHAPE ABUTMENT ;
    PORT
      LAYER M4 ;
      RECT 0.000 1485.936 0.192 1485.960 ;
    END
  END rx[409]
  PIN rx[410]
    DIRECTION OUTPUT ;
    USE SIGNAL ;
    SHAPE ABUTMENT ;
    PORT
      LAYER M4 ;
      RECT 0.000 1487.568 0.192 1487.592 ;
    END
  END rx[410]
  PIN rx[411]
    DIRECTION OUTPUT ;
    USE SIGNAL ;
    SHAPE ABUTMENT ;
    PORT
      LAYER M4 ;
      RECT 0.000 1489.152 0.192 1489.176 ;
    END
  END rx[411]
  PIN rx[412]
    DIRECTION OUTPUT ;
    USE SIGNAL ;
    SHAPE ABUTMENT ;
    PORT
      LAYER M4 ;
      RECT 0.000 1490.784 0.192 1490.808 ;
    END
  END rx[412]
  PIN rx[413]
    DIRECTION OUTPUT ;
    USE SIGNAL ;
    SHAPE ABUTMENT ;
    PORT
      LAYER M4 ;
      RECT 0.000 1492.416 0.192 1492.440 ;
    END
  END rx[413]
  PIN rx[414]
    DIRECTION OUTPUT ;
    USE SIGNAL ;
    SHAPE ABUTMENT ;
    PORT
      LAYER M4 ;
      RECT 0.000 1494.000 0.192 1494.024 ;
    END
  END rx[414]
  PIN rx[415]
    DIRECTION OUTPUT ;
    USE SIGNAL ;
    SHAPE ABUTMENT ;
    PORT
      LAYER M4 ;
      RECT 0.000 1495.632 0.192 1495.656 ;
    END
  END rx[415]
  PIN rx[416]
    DIRECTION OUTPUT ;
    USE SIGNAL ;
    SHAPE ABUTMENT ;
    PORT
      LAYER M4 ;
      RECT 0.000 1497.216 0.192 1497.240 ;
    END
  END rx[416]
  PIN rx[417]
    DIRECTION OUTPUT ;
    USE SIGNAL ;
    SHAPE ABUTMENT ;
    PORT
      LAYER M4 ;
      RECT 0.000 1498.848 0.192 1498.872 ;
    END
  END rx[417]
  PIN rx[418]
    DIRECTION OUTPUT ;
    USE SIGNAL ;
    SHAPE ABUTMENT ;
    PORT
      LAYER M4 ;
      RECT 0.000 1500.432 0.192 1500.456 ;
    END
  END rx[418]
  PIN rx[419]
    DIRECTION OUTPUT ;
    USE SIGNAL ;
    SHAPE ABUTMENT ;
    PORT
      LAYER M4 ;
      RECT 0.000 1502.064 0.192 1502.088 ;
    END
  END rx[419]
  PIN rx[420]
    DIRECTION OUTPUT ;
    USE SIGNAL ;
    SHAPE ABUTMENT ;
    PORT
      LAYER M4 ;
      RECT 0.000 1503.696 0.192 1503.720 ;
    END
  END rx[420]
  PIN rx[421]
    DIRECTION OUTPUT ;
    USE SIGNAL ;
    SHAPE ABUTMENT ;
    PORT
      LAYER M4 ;
      RECT 0.000 1505.280 0.192 1505.304 ;
    END
  END rx[421]
  PIN rx[422]
    DIRECTION OUTPUT ;
    USE SIGNAL ;
    SHAPE ABUTMENT ;
    PORT
      LAYER M4 ;
      RECT 0.000 1506.912 0.192 1506.936 ;
    END
  END rx[422]
  PIN rx[423]
    DIRECTION OUTPUT ;
    USE SIGNAL ;
    SHAPE ABUTMENT ;
    PORT
      LAYER M4 ;
      RECT 0.000 1508.496 0.192 1508.520 ;
    END
  END rx[423]
  PIN rx[424]
    DIRECTION OUTPUT ;
    USE SIGNAL ;
    SHAPE ABUTMENT ;
    PORT
      LAYER M4 ;
      RECT 0.000 1510.128 0.192 1510.152 ;
    END
  END rx[424]
  PIN rx[425]
    DIRECTION OUTPUT ;
    USE SIGNAL ;
    SHAPE ABUTMENT ;
    PORT
      LAYER M4 ;
      RECT 0.000 1511.712 0.192 1511.736 ;
    END
  END rx[425]
  PIN rx[426]
    DIRECTION OUTPUT ;
    USE SIGNAL ;
    SHAPE ABUTMENT ;
    PORT
      LAYER M4 ;
      RECT 0.000 1513.344 0.192 1513.368 ;
    END
  END rx[426]
  PIN rx[427]
    DIRECTION OUTPUT ;
    USE SIGNAL ;
    SHAPE ABUTMENT ;
    PORT
      LAYER M4 ;
      RECT 0.000 1514.928 0.192 1514.952 ;
    END
  END rx[427]
  PIN rx[428]
    DIRECTION OUTPUT ;
    USE SIGNAL ;
    SHAPE ABUTMENT ;
    PORT
      LAYER M4 ;
      RECT 0.000 1516.560 0.192 1516.584 ;
    END
  END rx[428]
  PIN rx[429]
    DIRECTION OUTPUT ;
    USE SIGNAL ;
    SHAPE ABUTMENT ;
    PORT
      LAYER M4 ;
      RECT 0.000 1518.192 0.192 1518.216 ;
    END
  END rx[429]
  PIN rx[430]
    DIRECTION OUTPUT ;
    USE SIGNAL ;
    SHAPE ABUTMENT ;
    PORT
      LAYER M4 ;
      RECT 0.000 1519.776 0.192 1519.800 ;
    END
  END rx[430]
  PIN rx[431]
    DIRECTION OUTPUT ;
    USE SIGNAL ;
    SHAPE ABUTMENT ;
    PORT
      LAYER M4 ;
      RECT 0.000 1521.408 0.192 1521.432 ;
    END
  END rx[431]
  PIN rx[432]
    DIRECTION OUTPUT ;
    USE SIGNAL ;
    SHAPE ABUTMENT ;
    PORT
      LAYER M4 ;
      RECT 0.000 1522.992 0.192 1523.016 ;
    END
  END rx[432]
  PIN rx[433]
    DIRECTION OUTPUT ;
    USE SIGNAL ;
    SHAPE ABUTMENT ;
    PORT
      LAYER M4 ;
      RECT 0.000 1524.624 0.192 1524.648 ;
    END
  END rx[433]
  PIN rx[434]
    DIRECTION OUTPUT ;
    USE SIGNAL ;
    SHAPE ABUTMENT ;
    PORT
      LAYER M4 ;
      RECT 0.000 1526.208 0.192 1526.232 ;
    END
  END rx[434]
  PIN rx[435]
    DIRECTION OUTPUT ;
    USE SIGNAL ;
    SHAPE ABUTMENT ;
    PORT
      LAYER M4 ;
      RECT 0.000 1527.840 0.192 1527.864 ;
    END
  END rx[435]
  PIN rx[436]
    DIRECTION OUTPUT ;
    USE SIGNAL ;
    SHAPE ABUTMENT ;
    PORT
      LAYER M4 ;
      RECT 0.000 1529.472 0.192 1529.496 ;
    END
  END rx[436]
  PIN rx[437]
    DIRECTION OUTPUT ;
    USE SIGNAL ;
    SHAPE ABUTMENT ;
    PORT
      LAYER M4 ;
      RECT 0.000 1531.056 0.192 1531.080 ;
    END
  END rx[437]
  PIN rx[438]
    DIRECTION OUTPUT ;
    USE SIGNAL ;
    SHAPE ABUTMENT ;
    PORT
      LAYER M4 ;
      RECT 0.000 1532.688 0.192 1532.712 ;
    END
  END rx[438]
  PIN rx[439]
    DIRECTION OUTPUT ;
    USE SIGNAL ;
    SHAPE ABUTMENT ;
    PORT
      LAYER M4 ;
      RECT 0.000 1534.272 0.192 1534.296 ;
    END
  END rx[439]
  PIN rx[440]
    DIRECTION OUTPUT ;
    USE SIGNAL ;
    SHAPE ABUTMENT ;
    PORT
      LAYER M4 ;
      RECT 0.000 1535.904 0.192 1535.928 ;
    END
  END rx[440]
  PIN rx[441]
    DIRECTION OUTPUT ;
    USE SIGNAL ;
    SHAPE ABUTMENT ;
    PORT
      LAYER M4 ;
      RECT 0.000 1537.488 0.192 1537.512 ;
    END
  END rx[441]
  PIN rx[442]
    DIRECTION OUTPUT ;
    USE SIGNAL ;
    SHAPE ABUTMENT ;
    PORT
      LAYER M4 ;
      RECT 0.000 1539.120 0.192 1539.144 ;
    END
  END rx[442]
  PIN rx[443]
    DIRECTION OUTPUT ;
    USE SIGNAL ;
    SHAPE ABUTMENT ;
    PORT
      LAYER M4 ;
      RECT 0.000 1540.752 0.192 1540.776 ;
    END
  END rx[443]
  PIN rx[444]
    DIRECTION OUTPUT ;
    USE SIGNAL ;
    SHAPE ABUTMENT ;
    PORT
      LAYER M4 ;
      RECT 0.000 1542.336 0.192 1542.360 ;
    END
  END rx[444]
  PIN rx[445]
    DIRECTION OUTPUT ;
    USE SIGNAL ;
    SHAPE ABUTMENT ;
    PORT
      LAYER M4 ;
      RECT 0.000 1543.968 0.192 1543.992 ;
    END
  END rx[445]
  PIN rx[446]
    DIRECTION OUTPUT ;
    USE SIGNAL ;
    SHAPE ABUTMENT ;
    PORT
      LAYER M4 ;
      RECT 0.000 1545.552 0.192 1545.576 ;
    END
  END rx[446]
  PIN rx[447]
    DIRECTION OUTPUT ;
    USE SIGNAL ;
    SHAPE ABUTMENT ;
    PORT
      LAYER M4 ;
      RECT 0.000 1547.184 0.192 1547.208 ;
    END
  END rx[447]
  PIN rx[448]
    DIRECTION OUTPUT ;
    USE SIGNAL ;
    SHAPE ABUTMENT ;
    PORT
      LAYER M4 ;
      RECT 0.000 1548.768 0.192 1548.792 ;
    END
  END rx[448]
  PIN rx[449]
    DIRECTION OUTPUT ;
    USE SIGNAL ;
    SHAPE ABUTMENT ;
    PORT
      LAYER M4 ;
      RECT 0.000 1550.400 0.192 1550.424 ;
    END
  END rx[449]
  PIN rx[450]
    DIRECTION OUTPUT ;
    USE SIGNAL ;
    SHAPE ABUTMENT ;
    PORT
      LAYER M4 ;
      RECT 0.000 1551.984 0.192 1552.008 ;
    END
  END rx[450]
  PIN rx[451]
    DIRECTION OUTPUT ;
    USE SIGNAL ;
    SHAPE ABUTMENT ;
    PORT
      LAYER M4 ;
      RECT 0.000 1553.616 0.192 1553.640 ;
    END
  END rx[451]
  PIN rx[452]
    DIRECTION OUTPUT ;
    USE SIGNAL ;
    SHAPE ABUTMENT ;
    PORT
      LAYER M4 ;
      RECT 0.000 1555.248 0.192 1555.272 ;
    END
  END rx[452]
  PIN rx[453]
    DIRECTION OUTPUT ;
    USE SIGNAL ;
    SHAPE ABUTMENT ;
    PORT
      LAYER M4 ;
      RECT 0.000 1556.832 0.192 1556.856 ;
    END
  END rx[453]
  PIN rx[454]
    DIRECTION OUTPUT ;
    USE SIGNAL ;
    SHAPE ABUTMENT ;
    PORT
      LAYER M4 ;
      RECT 0.000 1558.464 0.192 1558.488 ;
    END
  END rx[454]
  PIN rx[455]
    DIRECTION OUTPUT ;
    USE SIGNAL ;
    SHAPE ABUTMENT ;
    PORT
      LAYER M4 ;
      RECT 0.000 1560.048 0.192 1560.072 ;
    END
  END rx[455]
  PIN rx[456]
    DIRECTION OUTPUT ;
    USE SIGNAL ;
    SHAPE ABUTMENT ;
    PORT
      LAYER M4 ;
      RECT 0.000 1561.680 0.192 1561.704 ;
    END
  END rx[456]
  PIN rx[457]
    DIRECTION OUTPUT ;
    USE SIGNAL ;
    SHAPE ABUTMENT ;
    PORT
      LAYER M4 ;
      RECT 0.000 1563.264 0.192 1563.288 ;
    END
  END rx[457]
  PIN rx[458]
    DIRECTION OUTPUT ;
    USE SIGNAL ;
    SHAPE ABUTMENT ;
    PORT
      LAYER M4 ;
      RECT 0.000 1564.896 0.192 1564.920 ;
    END
  END rx[458]
  PIN rx[459]
    DIRECTION OUTPUT ;
    USE SIGNAL ;
    SHAPE ABUTMENT ;
    PORT
      LAYER M4 ;
      RECT 0.000 1566.528 0.192 1566.552 ;
    END
  END rx[459]
  PIN rx[460]
    DIRECTION OUTPUT ;
    USE SIGNAL ;
    SHAPE ABUTMENT ;
    PORT
      LAYER M4 ;
      RECT 0.000 1568.112 0.192 1568.136 ;
    END
  END rx[460]
  PIN rx[461]
    DIRECTION OUTPUT ;
    USE SIGNAL ;
    SHAPE ABUTMENT ;
    PORT
      LAYER M4 ;
      RECT 0.000 1569.744 0.192 1569.768 ;
    END
  END rx[461]
  PIN rx[462]
    DIRECTION OUTPUT ;
    USE SIGNAL ;
    SHAPE ABUTMENT ;
    PORT
      LAYER M4 ;
      RECT 0.000 1571.328 0.192 1571.352 ;
    END
  END rx[462]
  PIN rx[463]
    DIRECTION OUTPUT ;
    USE SIGNAL ;
    SHAPE ABUTMENT ;
    PORT
      LAYER M4 ;
      RECT 0.000 1572.960 0.192 1572.984 ;
    END
  END rx[463]
  PIN rx[464]
    DIRECTION OUTPUT ;
    USE SIGNAL ;
    SHAPE ABUTMENT ;
    PORT
      LAYER M4 ;
      RECT 0.000 1574.544 0.192 1574.568 ;
    END
  END rx[464]
  PIN rx[465]
    DIRECTION OUTPUT ;
    USE SIGNAL ;
    SHAPE ABUTMENT ;
    PORT
      LAYER M4 ;
      RECT 0.000 1576.176 0.192 1576.200 ;
    END
  END rx[465]
  PIN rx[466]
    DIRECTION OUTPUT ;
    USE SIGNAL ;
    SHAPE ABUTMENT ;
    PORT
      LAYER M4 ;
      RECT 0.000 1577.808 0.192 1577.832 ;
    END
  END rx[466]
  PIN rx[467]
    DIRECTION OUTPUT ;
    USE SIGNAL ;
    SHAPE ABUTMENT ;
    PORT
      LAYER M4 ;
      RECT 0.000 1579.392 0.192 1579.416 ;
    END
  END rx[467]
  PIN rx[468]
    DIRECTION OUTPUT ;
    USE SIGNAL ;
    SHAPE ABUTMENT ;
    PORT
      LAYER M4 ;
      RECT 0.000 1581.024 0.192 1581.048 ;
    END
  END rx[468]
  PIN rx[469]
    DIRECTION OUTPUT ;
    USE SIGNAL ;
    SHAPE ABUTMENT ;
    PORT
      LAYER M4 ;
      RECT 0.000 1582.608 0.192 1582.632 ;
    END
  END rx[469]
  PIN rx[470]
    DIRECTION OUTPUT ;
    USE SIGNAL ;
    SHAPE ABUTMENT ;
    PORT
      LAYER M4 ;
      RECT 0.000 1584.240 0.192 1584.264 ;
    END
  END rx[470]
  PIN rx[471]
    DIRECTION OUTPUT ;
    USE SIGNAL ;
    SHAPE ABUTMENT ;
    PORT
      LAYER M4 ;
      RECT 0.000 1585.824 0.192 1585.848 ;
    END
  END rx[471]
  PIN rx[472]
    DIRECTION OUTPUT ;
    USE SIGNAL ;
    SHAPE ABUTMENT ;
    PORT
      LAYER M4 ;
      RECT 0.000 1587.456 0.192 1587.480 ;
    END
  END rx[472]
  PIN rx[473]
    DIRECTION OUTPUT ;
    USE SIGNAL ;
    SHAPE ABUTMENT ;
    PORT
      LAYER M4 ;
      RECT 0.000 1589.040 0.192 1589.064 ;
    END
  END rx[473]
  PIN rx[474]
    DIRECTION OUTPUT ;
    USE SIGNAL ;
    SHAPE ABUTMENT ;
    PORT
      LAYER M4 ;
      RECT 0.000 1590.672 0.192 1590.696 ;
    END
  END rx[474]
  PIN rx[475]
    DIRECTION OUTPUT ;
    USE SIGNAL ;
    SHAPE ABUTMENT ;
    PORT
      LAYER M4 ;
      RECT 0.000 1592.304 0.192 1592.328 ;
    END
  END rx[475]
  PIN rx[476]
    DIRECTION OUTPUT ;
    USE SIGNAL ;
    SHAPE ABUTMENT ;
    PORT
      LAYER M4 ;
      RECT 0.000 1593.888 0.192 1593.912 ;
    END
  END rx[476]
  PIN rx[477]
    DIRECTION OUTPUT ;
    USE SIGNAL ;
    SHAPE ABUTMENT ;
    PORT
      LAYER M4 ;
      RECT 0.000 1595.520 0.192 1595.544 ;
    END
  END rx[477]
  PIN rx[478]
    DIRECTION OUTPUT ;
    USE SIGNAL ;
    SHAPE ABUTMENT ;
    PORT
      LAYER M4 ;
      RECT 0.000 1597.104 0.192 1597.128 ;
    END
  END rx[478]
  PIN rx[479]
    DIRECTION OUTPUT ;
    USE SIGNAL ;
    SHAPE ABUTMENT ;
    PORT
      LAYER M4 ;
      RECT 0.000 1598.736 0.192 1598.760 ;
    END
  END rx[479]
  PIN rx[480]
    DIRECTION OUTPUT ;
    USE SIGNAL ;
    SHAPE ABUTMENT ;
    PORT
      LAYER M4 ;
      RECT 0.000 1600.320 0.192 1600.344 ;
    END
  END rx[480]
  PIN rx[481]
    DIRECTION OUTPUT ;
    USE SIGNAL ;
    SHAPE ABUTMENT ;
    PORT
      LAYER M4 ;
      RECT 0.000 1601.952 0.192 1601.976 ;
    END
  END rx[481]
  PIN rx[482]
    DIRECTION OUTPUT ;
    USE SIGNAL ;
    SHAPE ABUTMENT ;
    PORT
      LAYER M4 ;
      RECT 0.000 1603.584 0.192 1603.608 ;
    END
  END rx[482]
  PIN rx[483]
    DIRECTION OUTPUT ;
    USE SIGNAL ;
    SHAPE ABUTMENT ;
    PORT
      LAYER M4 ;
      RECT 0.000 1605.168 0.192 1605.192 ;
    END
  END rx[483]
  PIN rx[484]
    DIRECTION OUTPUT ;
    USE SIGNAL ;
    SHAPE ABUTMENT ;
    PORT
      LAYER M4 ;
      RECT 0.000 1606.800 0.192 1606.824 ;
    END
  END rx[484]
  PIN rx[485]
    DIRECTION OUTPUT ;
    USE SIGNAL ;
    SHAPE ABUTMENT ;
    PORT
      LAYER M4 ;
      RECT 0.000 1608.384 0.192 1608.408 ;
    END
  END rx[485]
  PIN rx[486]
    DIRECTION OUTPUT ;
    USE SIGNAL ;
    SHAPE ABUTMENT ;
    PORT
      LAYER M4 ;
      RECT 0.000 1610.016 0.192 1610.040 ;
    END
  END rx[486]
  PIN rx[487]
    DIRECTION OUTPUT ;
    USE SIGNAL ;
    SHAPE ABUTMENT ;
    PORT
      LAYER M4 ;
      RECT 0.000 1611.600 0.192 1611.624 ;
    END
  END rx[487]
  PIN rx[488]
    DIRECTION OUTPUT ;
    USE SIGNAL ;
    SHAPE ABUTMENT ;
    PORT
      LAYER M4 ;
      RECT 0.000 1613.232 0.192 1613.256 ;
    END
  END rx[488]
  PIN rx[489]
    DIRECTION OUTPUT ;
    USE SIGNAL ;
    SHAPE ABUTMENT ;
    PORT
      LAYER M4 ;
      RECT 0.000 1614.864 0.192 1614.888 ;
    END
  END rx[489]
  PIN rx[490]
    DIRECTION OUTPUT ;
    USE SIGNAL ;
    SHAPE ABUTMENT ;
    PORT
      LAYER M4 ;
      RECT 0.000 1616.448 0.192 1616.472 ;
    END
  END rx[490]
  PIN rx[491]
    DIRECTION OUTPUT ;
    USE SIGNAL ;
    SHAPE ABUTMENT ;
    PORT
      LAYER M4 ;
      RECT 0.000 1618.080 0.192 1618.104 ;
    END
  END rx[491]
  PIN rx[492]
    DIRECTION OUTPUT ;
    USE SIGNAL ;
    SHAPE ABUTMENT ;
    PORT
      LAYER M4 ;
      RECT 0.000 1619.664 0.192 1619.688 ;
    END
  END rx[492]
  PIN rx[493]
    DIRECTION OUTPUT ;
    USE SIGNAL ;
    SHAPE ABUTMENT ;
    PORT
      LAYER M4 ;
      RECT 0.000 1621.296 0.192 1621.320 ;
    END
  END rx[493]
  PIN rx[494]
    DIRECTION OUTPUT ;
    USE SIGNAL ;
    SHAPE ABUTMENT ;
    PORT
      LAYER M4 ;
      RECT 0.000 1622.880 0.192 1622.904 ;
    END
  END rx[494]
  PIN rx[495]
    DIRECTION OUTPUT ;
    USE SIGNAL ;
    SHAPE ABUTMENT ;
    PORT
      LAYER M4 ;
      RECT 0.000 1624.512 0.192 1624.536 ;
    END
  END rx[495]
  PIN rx[496]
    DIRECTION OUTPUT ;
    USE SIGNAL ;
    SHAPE ABUTMENT ;
    PORT
      LAYER M4 ;
      RECT 0.000 1626.096 0.192 1626.120 ;
    END
  END rx[496]
  PIN rx[497]
    DIRECTION OUTPUT ;
    USE SIGNAL ;
    SHAPE ABUTMENT ;
    PORT
      LAYER M4 ;
      RECT 0.000 1627.728 0.192 1627.752 ;
    END
  END rx[497]
  PIN rx[498]
    DIRECTION OUTPUT ;
    USE SIGNAL ;
    SHAPE ABUTMENT ;
    PORT
      LAYER M4 ;
      RECT 0.000 1629.360 0.192 1629.384 ;
    END
  END rx[498]
  PIN rx[499]
    DIRECTION OUTPUT ;
    USE SIGNAL ;
    SHAPE ABUTMENT ;
    PORT
      LAYER M4 ;
      RECT 0.000 1630.944 0.192 1630.968 ;
    END
  END rx[499]
  PIN rx[500]
    DIRECTION OUTPUT ;
    USE SIGNAL ;
    SHAPE ABUTMENT ;
    PORT
      LAYER M4 ;
      RECT 0.000 1632.576 0.192 1632.600 ;
    END
  END rx[500]
  PIN rx[501]
    DIRECTION OUTPUT ;
    USE SIGNAL ;
    SHAPE ABUTMENT ;
    PORT
      LAYER M4 ;
      RECT 0.000 1634.160 0.192 1634.184 ;
    END
  END rx[501]
  PIN rx[502]
    DIRECTION OUTPUT ;
    USE SIGNAL ;
    SHAPE ABUTMENT ;
    PORT
      LAYER M4 ;
      RECT 0.000 1635.792 0.192 1635.816 ;
    END
  END rx[502]
  PIN rx[503]
    DIRECTION OUTPUT ;
    USE SIGNAL ;
    SHAPE ABUTMENT ;
    PORT
      LAYER M4 ;
      RECT 0.000 1637.376 0.192 1637.400 ;
    END
  END rx[503]
  PIN rx[504]
    DIRECTION OUTPUT ;
    USE SIGNAL ;
    SHAPE ABUTMENT ;
    PORT
      LAYER M4 ;
      RECT 0.000 1639.008 0.192 1639.032 ;
    END
  END rx[504]
  PIN rx[505]
    DIRECTION OUTPUT ;
    USE SIGNAL ;
    SHAPE ABUTMENT ;
    PORT
      LAYER M4 ;
      RECT 0.000 1640.640 0.192 1640.664 ;
    END
  END rx[505]
  PIN rx[506]
    DIRECTION OUTPUT ;
    USE SIGNAL ;
    SHAPE ABUTMENT ;
    PORT
      LAYER M4 ;
      RECT 0.000 1642.224 0.192 1642.248 ;
    END
  END rx[506]
  PIN rx[507]
    DIRECTION OUTPUT ;
    USE SIGNAL ;
    SHAPE ABUTMENT ;
    PORT
      LAYER M4 ;
      RECT 0.000 1643.856 0.192 1643.880 ;
    END
  END rx[507]
  PIN rx[508]
    DIRECTION OUTPUT ;
    USE SIGNAL ;
    SHAPE ABUTMENT ;
    PORT
      LAYER M4 ;
      RECT 0.000 1645.440 0.192 1645.464 ;
    END
  END rx[508]
  PIN rx[509]
    DIRECTION OUTPUT ;
    USE SIGNAL ;
    SHAPE ABUTMENT ;
    PORT
      LAYER M4 ;
      RECT 0.000 1647.072 0.192 1647.096 ;
    END
  END rx[509]
  PIN rx[510]
    DIRECTION OUTPUT ;
    USE SIGNAL ;
    SHAPE ABUTMENT ;
    PORT
      LAYER M4 ;
      RECT 0.000 1648.656 0.192 1648.680 ;
    END
  END rx[510]
  PIN rx[511]
    DIRECTION OUTPUT ;
    USE SIGNAL ;
    SHAPE ABUTMENT ;
    PORT
      LAYER M4 ;
      RECT 0.000 1650.288 0.192 1650.312 ;
    END
  END rx[511]
  PIN VSS
    DIRECTION INOUT ;
    USE GROUND ;
    PORT
      LAYER M4 ;
      RECT 0.492 1.200 260.316 1.296 ;
      RECT 0.492 3.600 260.316 3.696 ;
      RECT 0.492 6.000 260.316 6.096 ;
      RECT 0.492 8.400 260.316 8.496 ;
      RECT 0.492 10.800 260.316 10.896 ;
      RECT 0.492 13.200 260.316 13.296 ;
      RECT 0.492 15.600 260.316 15.696 ;
      RECT 0.492 18.000 260.316 18.096 ;
      RECT 0.492 20.400 260.316 20.496 ;
      RECT 0.492 22.800 260.316 22.896 ;
      RECT 0.492 25.200 260.316 25.296 ;
      RECT 0.492 27.600 260.316 27.696 ;
      RECT 0.492 30.000 260.316 30.096 ;
      RECT 0.492 32.400 260.316 32.496 ;
      RECT 0.492 34.800 260.316 34.896 ;
      RECT 0.492 37.200 260.316 37.296 ;
      RECT 0.492 39.600 260.316 39.696 ;
      RECT 0.492 42.000 260.316 42.096 ;
      RECT 0.492 44.400 260.316 44.496 ;
      RECT 0.492 46.800 260.316 46.896 ;
      RECT 0.492 49.200 260.316 49.296 ;
      RECT 0.492 51.600 260.316 51.696 ;
      RECT 0.492 54.000 260.316 54.096 ;
      RECT 0.492 56.400 260.316 56.496 ;
      RECT 0.492 58.800 260.316 58.896 ;
      RECT 0.492 61.200 260.316 61.296 ;
      RECT 0.492 63.600 260.316 63.696 ;
      RECT 0.492 66.000 260.316 66.096 ;
      RECT 0.492 68.400 260.316 68.496 ;
      RECT 0.492 70.800 260.316 70.896 ;
      RECT 0.492 73.200 260.316 73.296 ;
      RECT 0.492 75.600 260.316 75.696 ;
      RECT 0.492 78.000 260.316 78.096 ;
      RECT 0.492 80.400 260.316 80.496 ;
      RECT 0.492 82.800 260.316 82.896 ;
      RECT 0.492 85.200 260.316 85.296 ;
      RECT 0.492 87.600 260.316 87.696 ;
      RECT 0.492 90.000 260.316 90.096 ;
      RECT 0.492 92.400 260.316 92.496 ;
      RECT 0.492 94.800 260.316 94.896 ;
      RECT 0.492 97.200 260.316 97.296 ;
      RECT 0.492 99.600 260.316 99.696 ;
      RECT 0.492 102.000 260.316 102.096 ;
      RECT 0.492 104.400 260.316 104.496 ;
      RECT 0.492 106.800 260.316 106.896 ;
      RECT 0.492 109.200 260.316 109.296 ;
      RECT 0.492 111.600 260.316 111.696 ;
      RECT 0.492 114.000 260.316 114.096 ;
      RECT 0.492 116.400 260.316 116.496 ;
      RECT 0.492 118.800 260.316 118.896 ;
      RECT 0.492 121.200 260.316 121.296 ;
      RECT 0.492 123.600 260.316 123.696 ;
      RECT 0.492 126.000 260.316 126.096 ;
      RECT 0.492 128.400 260.316 128.496 ;
      RECT 0.492 130.800 260.316 130.896 ;
      RECT 0.492 133.200 260.316 133.296 ;
      RECT 0.492 135.600 260.316 135.696 ;
      RECT 0.492 138.000 260.316 138.096 ;
      RECT 0.492 140.400 260.316 140.496 ;
      RECT 0.492 142.800 260.316 142.896 ;
      RECT 0.492 145.200 260.316 145.296 ;
      RECT 0.492 147.600 260.316 147.696 ;
      RECT 0.492 150.000 260.316 150.096 ;
      RECT 0.492 152.400 260.316 152.496 ;
      RECT 0.492 154.800 260.316 154.896 ;
      RECT 0.492 157.200 260.316 157.296 ;
      RECT 0.492 159.600 260.316 159.696 ;
      RECT 0.492 162.000 260.316 162.096 ;
      RECT 0.492 164.400 260.316 164.496 ;
      RECT 0.492 166.800 260.316 166.896 ;
      RECT 0.492 169.200 260.316 169.296 ;
      RECT 0.492 171.600 260.316 171.696 ;
      RECT 0.492 174.000 260.316 174.096 ;
      RECT 0.492 176.400 260.316 176.496 ;
      RECT 0.492 178.800 260.316 178.896 ;
      RECT 0.492 181.200 260.316 181.296 ;
      RECT 0.492 183.600 260.316 183.696 ;
      RECT 0.492 186.000 260.316 186.096 ;
      RECT 0.492 188.400 260.316 188.496 ;
      RECT 0.492 190.800 260.316 190.896 ;
      RECT 0.492 193.200 260.316 193.296 ;
      RECT 0.492 195.600 260.316 195.696 ;
      RECT 0.492 198.000 260.316 198.096 ;
      RECT 0.492 200.400 260.316 200.496 ;
      RECT 0.492 202.800 260.316 202.896 ;
      RECT 0.492 205.200 260.316 205.296 ;
      RECT 0.492 207.600 260.316 207.696 ;
      RECT 0.492 210.000 260.316 210.096 ;
      RECT 0.492 212.400 260.316 212.496 ;
      RECT 0.492 214.800 260.316 214.896 ;
      RECT 0.492 217.200 260.316 217.296 ;
      RECT 0.492 219.600 260.316 219.696 ;
      RECT 0.492 222.000 260.316 222.096 ;
      RECT 0.492 224.400 260.316 224.496 ;
      RECT 0.492 226.800 260.316 226.896 ;
      RECT 0.492 229.200 260.316 229.296 ;
      RECT 0.492 231.600 260.316 231.696 ;
      RECT 0.492 234.000 260.316 234.096 ;
      RECT 0.492 236.400 260.316 236.496 ;
      RECT 0.492 238.800 260.316 238.896 ;
      RECT 0.492 241.200 260.316 241.296 ;
      RECT 0.492 243.600 260.316 243.696 ;
      RECT 0.492 246.000 260.316 246.096 ;
      RECT 0.492 248.400 260.316 248.496 ;
      RECT 0.492 250.800 260.316 250.896 ;
      RECT 0.492 253.200 260.316 253.296 ;
      RECT 0.492 255.600 260.316 255.696 ;
      RECT 0.492 258.000 260.316 258.096 ;
      RECT 0.492 260.400 260.316 260.496 ;
      RECT 0.492 262.800 260.316 262.896 ;
      RECT 0.492 265.200 260.316 265.296 ;
      RECT 0.492 267.600 260.316 267.696 ;
      RECT 0.492 270.000 260.316 270.096 ;
      RECT 0.492 272.400 260.316 272.496 ;
      RECT 0.492 274.800 260.316 274.896 ;
      RECT 0.492 277.200 260.316 277.296 ;
      RECT 0.492 279.600 260.316 279.696 ;
      RECT 0.492 282.000 260.316 282.096 ;
      RECT 0.492 284.400 260.316 284.496 ;
      RECT 0.492 286.800 260.316 286.896 ;
      RECT 0.492 289.200 260.316 289.296 ;
      RECT 0.492 291.600 260.316 291.696 ;
      RECT 0.492 294.000 260.316 294.096 ;
      RECT 0.492 296.400 260.316 296.496 ;
      RECT 0.492 298.800 260.316 298.896 ;
      RECT 0.492 301.200 260.316 301.296 ;
      RECT 0.492 303.600 260.316 303.696 ;
      RECT 0.492 306.000 260.316 306.096 ;
      RECT 0.492 308.400 260.316 308.496 ;
      RECT 0.492 310.800 260.316 310.896 ;
      RECT 0.492 313.200 260.316 313.296 ;
      RECT 0.492 315.600 260.316 315.696 ;
      RECT 0.492 318.000 260.316 318.096 ;
      RECT 0.492 320.400 260.316 320.496 ;
      RECT 0.492 322.800 260.316 322.896 ;
      RECT 0.492 325.200 260.316 325.296 ;
      RECT 0.492 327.600 260.316 327.696 ;
      RECT 0.492 330.000 260.316 330.096 ;
      RECT 0.492 332.400 260.316 332.496 ;
      RECT 0.492 334.800 260.316 334.896 ;
      RECT 0.492 337.200 260.316 337.296 ;
      RECT 0.492 339.600 260.316 339.696 ;
      RECT 0.492 342.000 260.316 342.096 ;
      RECT 0.492 344.400 260.316 344.496 ;
      RECT 0.492 346.800 260.316 346.896 ;
      RECT 0.492 349.200 260.316 349.296 ;
      RECT 0.492 351.600 260.316 351.696 ;
      RECT 0.492 354.000 260.316 354.096 ;
      RECT 0.492 356.400 260.316 356.496 ;
      RECT 0.492 358.800 260.316 358.896 ;
      RECT 0.492 361.200 260.316 361.296 ;
      RECT 0.492 363.600 260.316 363.696 ;
      RECT 0.492 366.000 260.316 366.096 ;
      RECT 0.492 368.400 260.316 368.496 ;
      RECT 0.492 370.800 260.316 370.896 ;
      RECT 0.492 373.200 260.316 373.296 ;
      RECT 0.492 375.600 260.316 375.696 ;
      RECT 0.492 378.000 260.316 378.096 ;
      RECT 0.492 380.400 260.316 380.496 ;
      RECT 0.492 382.800 260.316 382.896 ;
      RECT 0.492 385.200 260.316 385.296 ;
      RECT 0.492 387.600 260.316 387.696 ;
      RECT 0.492 390.000 260.316 390.096 ;
      RECT 0.492 392.400 260.316 392.496 ;
      RECT 0.492 394.800 260.316 394.896 ;
      RECT 0.492 397.200 260.316 397.296 ;
      RECT 0.492 399.600 260.316 399.696 ;
      RECT 0.492 402.000 260.316 402.096 ;
      RECT 0.492 404.400 260.316 404.496 ;
      RECT 0.492 406.800 260.316 406.896 ;
      RECT 0.492 409.200 260.316 409.296 ;
      RECT 0.492 411.600 260.316 411.696 ;
      RECT 0.492 414.000 260.316 414.096 ;
      RECT 0.492 416.400 260.316 416.496 ;
      RECT 0.492 418.800 260.316 418.896 ;
      RECT 0.492 421.200 260.316 421.296 ;
      RECT 0.492 423.600 260.316 423.696 ;
      RECT 0.492 426.000 260.316 426.096 ;
      RECT 0.492 428.400 260.316 428.496 ;
      RECT 0.492 430.800 260.316 430.896 ;
      RECT 0.492 433.200 260.316 433.296 ;
      RECT 0.492 435.600 260.316 435.696 ;
      RECT 0.492 438.000 260.316 438.096 ;
      RECT 0.492 440.400 260.316 440.496 ;
      RECT 0.492 442.800 260.316 442.896 ;
      RECT 0.492 445.200 260.316 445.296 ;
      RECT 0.492 447.600 260.316 447.696 ;
      RECT 0.492 450.000 260.316 450.096 ;
      RECT 0.492 452.400 260.316 452.496 ;
      RECT 0.492 454.800 260.316 454.896 ;
      RECT 0.492 457.200 260.316 457.296 ;
      RECT 0.492 459.600 260.316 459.696 ;
      RECT 0.492 462.000 260.316 462.096 ;
      RECT 0.492 464.400 260.316 464.496 ;
      RECT 0.492 466.800 260.316 466.896 ;
      RECT 0.492 469.200 260.316 469.296 ;
      RECT 0.492 471.600 260.316 471.696 ;
      RECT 0.492 474.000 260.316 474.096 ;
      RECT 0.492 476.400 260.316 476.496 ;
      RECT 0.492 478.800 260.316 478.896 ;
      RECT 0.492 481.200 260.316 481.296 ;
      RECT 0.492 483.600 260.316 483.696 ;
      RECT 0.492 486.000 260.316 486.096 ;
      RECT 0.492 488.400 260.316 488.496 ;
      RECT 0.492 490.800 260.316 490.896 ;
      RECT 0.492 493.200 260.316 493.296 ;
      RECT 0.492 495.600 260.316 495.696 ;
      RECT 0.492 498.000 260.316 498.096 ;
      RECT 0.492 500.400 260.316 500.496 ;
      RECT 0.492 502.800 260.316 502.896 ;
      RECT 0.492 505.200 260.316 505.296 ;
      RECT 0.492 507.600 260.316 507.696 ;
      RECT 0.492 510.000 260.316 510.096 ;
      RECT 0.492 512.400 260.316 512.496 ;
      RECT 0.492 514.800 260.316 514.896 ;
      RECT 0.492 517.200 260.316 517.296 ;
      RECT 0.492 519.600 260.316 519.696 ;
      RECT 0.492 522.000 260.316 522.096 ;
      RECT 0.492 524.400 260.316 524.496 ;
      RECT 0.492 526.800 260.316 526.896 ;
      RECT 0.492 529.200 260.316 529.296 ;
      RECT 0.492 531.600 260.316 531.696 ;
      RECT 0.492 534.000 260.316 534.096 ;
      RECT 0.492 536.400 260.316 536.496 ;
      RECT 0.492 538.800 260.316 538.896 ;
      RECT 0.492 541.200 260.316 541.296 ;
      RECT 0.492 543.600 260.316 543.696 ;
      RECT 0.492 546.000 260.316 546.096 ;
      RECT 0.492 548.400 260.316 548.496 ;
      RECT 0.492 550.800 260.316 550.896 ;
      RECT 0.492 553.200 260.316 553.296 ;
      RECT 0.492 555.600 260.316 555.696 ;
      RECT 0.492 558.000 260.316 558.096 ;
      RECT 0.492 560.400 260.316 560.496 ;
      RECT 0.492 562.800 260.316 562.896 ;
      RECT 0.492 565.200 260.316 565.296 ;
      RECT 0.492 567.600 260.316 567.696 ;
      RECT 0.492 570.000 260.316 570.096 ;
      RECT 0.492 572.400 260.316 572.496 ;
      RECT 0.492 574.800 260.316 574.896 ;
      RECT 0.492 577.200 260.316 577.296 ;
      RECT 0.492 579.600 260.316 579.696 ;
      RECT 0.492 582.000 260.316 582.096 ;
      RECT 0.492 584.400 260.316 584.496 ;
      RECT 0.492 586.800 260.316 586.896 ;
      RECT 0.492 589.200 260.316 589.296 ;
      RECT 0.492 591.600 260.316 591.696 ;
      RECT 0.492 594.000 260.316 594.096 ;
      RECT 0.492 596.400 260.316 596.496 ;
      RECT 0.492 598.800 260.316 598.896 ;
      RECT 0.492 601.200 260.316 601.296 ;
      RECT 0.492 603.600 260.316 603.696 ;
      RECT 0.492 606.000 260.316 606.096 ;
      RECT 0.492 608.400 260.316 608.496 ;
      RECT 0.492 610.800 260.316 610.896 ;
      RECT 0.492 613.200 260.316 613.296 ;
      RECT 0.492 615.600 260.316 615.696 ;
      RECT 0.492 618.000 260.316 618.096 ;
      RECT 0.492 620.400 260.316 620.496 ;
      RECT 0.492 622.800 260.316 622.896 ;
      RECT 0.492 625.200 260.316 625.296 ;
      RECT 0.492 627.600 260.316 627.696 ;
      RECT 0.492 630.000 260.316 630.096 ;
      RECT 0.492 632.400 260.316 632.496 ;
      RECT 0.492 634.800 260.316 634.896 ;
      RECT 0.492 637.200 260.316 637.296 ;
      RECT 0.492 639.600 260.316 639.696 ;
      RECT 0.492 642.000 260.316 642.096 ;
      RECT 0.492 644.400 260.316 644.496 ;
      RECT 0.492 646.800 260.316 646.896 ;
      RECT 0.492 649.200 260.316 649.296 ;
      RECT 0.492 651.600 260.316 651.696 ;
      RECT 0.492 654.000 260.316 654.096 ;
      RECT 0.492 656.400 260.316 656.496 ;
      RECT 0.492 658.800 260.316 658.896 ;
      RECT 0.492 661.200 260.316 661.296 ;
      RECT 0.492 663.600 260.316 663.696 ;
      RECT 0.492 666.000 260.316 666.096 ;
      RECT 0.492 668.400 260.316 668.496 ;
      RECT 0.492 670.800 260.316 670.896 ;
      RECT 0.492 673.200 260.316 673.296 ;
      RECT 0.492 675.600 260.316 675.696 ;
      RECT 0.492 678.000 260.316 678.096 ;
      RECT 0.492 680.400 260.316 680.496 ;
      RECT 0.492 682.800 260.316 682.896 ;
      RECT 0.492 685.200 260.316 685.296 ;
      RECT 0.492 687.600 260.316 687.696 ;
      RECT 0.492 690.000 260.316 690.096 ;
      RECT 0.492 692.400 260.316 692.496 ;
      RECT 0.492 694.800 260.316 694.896 ;
      RECT 0.492 697.200 260.316 697.296 ;
      RECT 0.492 699.600 260.316 699.696 ;
      RECT 0.492 702.000 260.316 702.096 ;
      RECT 0.492 704.400 260.316 704.496 ;
      RECT 0.492 706.800 260.316 706.896 ;
      RECT 0.492 709.200 260.316 709.296 ;
      RECT 0.492 711.600 260.316 711.696 ;
      RECT 0.492 714.000 260.316 714.096 ;
      RECT 0.492 716.400 260.316 716.496 ;
      RECT 0.492 718.800 260.316 718.896 ;
      RECT 0.492 721.200 260.316 721.296 ;
      RECT 0.492 723.600 260.316 723.696 ;
      RECT 0.492 726.000 260.316 726.096 ;
      RECT 0.492 728.400 260.316 728.496 ;
      RECT 0.492 730.800 260.316 730.896 ;
      RECT 0.492 733.200 260.316 733.296 ;
      RECT 0.492 735.600 260.316 735.696 ;
      RECT 0.492 738.000 260.316 738.096 ;
      RECT 0.492 740.400 260.316 740.496 ;
      RECT 0.492 742.800 260.316 742.896 ;
      RECT 0.492 745.200 260.316 745.296 ;
      RECT 0.492 747.600 260.316 747.696 ;
      RECT 0.492 750.000 260.316 750.096 ;
      RECT 0.492 752.400 260.316 752.496 ;
      RECT 0.492 754.800 260.316 754.896 ;
      RECT 0.492 757.200 260.316 757.296 ;
      RECT 0.492 759.600 260.316 759.696 ;
      RECT 0.492 762.000 260.316 762.096 ;
      RECT 0.492 764.400 260.316 764.496 ;
      RECT 0.492 766.800 260.316 766.896 ;
      RECT 0.492 769.200 260.316 769.296 ;
      RECT 0.492 771.600 260.316 771.696 ;
      RECT 0.492 774.000 260.316 774.096 ;
      RECT 0.492 776.400 260.316 776.496 ;
      RECT 0.492 778.800 260.316 778.896 ;
      RECT 0.492 781.200 260.316 781.296 ;
      RECT 0.492 783.600 260.316 783.696 ;
      RECT 0.492 786.000 260.316 786.096 ;
      RECT 0.492 788.400 260.316 788.496 ;
      RECT 0.492 790.800 260.316 790.896 ;
      RECT 0.492 793.200 260.316 793.296 ;
      RECT 0.492 795.600 260.316 795.696 ;
      RECT 0.492 798.000 260.316 798.096 ;
      RECT 0.492 800.400 260.316 800.496 ;
      RECT 0.492 802.800 260.316 802.896 ;
      RECT 0.492 805.200 260.316 805.296 ;
      RECT 0.492 807.600 260.316 807.696 ;
      RECT 0.492 810.000 260.316 810.096 ;
      RECT 0.492 812.400 260.316 812.496 ;
      RECT 0.492 814.800 260.316 814.896 ;
      RECT 0.492 817.200 260.316 817.296 ;
      RECT 0.492 819.600 260.316 819.696 ;
      RECT 0.492 822.000 260.316 822.096 ;
      RECT 0.492 824.400 260.316 824.496 ;
      RECT 0.492 826.800 260.316 826.896 ;
      RECT 0.492 829.200 260.316 829.296 ;
      RECT 0.492 831.600 260.316 831.696 ;
      RECT 0.492 834.000 260.316 834.096 ;
      RECT 0.492 836.400 260.316 836.496 ;
      RECT 0.492 838.800 260.316 838.896 ;
      RECT 0.492 841.200 260.316 841.296 ;
      RECT 0.492 843.600 260.316 843.696 ;
      RECT 0.492 846.000 260.316 846.096 ;
      RECT 0.492 848.400 260.316 848.496 ;
      RECT 0.492 850.800 260.316 850.896 ;
      RECT 0.492 853.200 260.316 853.296 ;
      RECT 0.492 855.600 260.316 855.696 ;
      RECT 0.492 858.000 260.316 858.096 ;
      RECT 0.492 860.400 260.316 860.496 ;
      RECT 0.492 862.800 260.316 862.896 ;
      RECT 0.492 865.200 260.316 865.296 ;
      RECT 0.492 867.600 260.316 867.696 ;
      RECT 0.492 870.000 260.316 870.096 ;
      RECT 0.492 872.400 260.316 872.496 ;
      RECT 0.492 874.800 260.316 874.896 ;
      RECT 0.492 877.200 260.316 877.296 ;
      RECT 0.492 879.600 260.316 879.696 ;
      RECT 0.492 882.000 260.316 882.096 ;
      RECT 0.492 884.400 260.316 884.496 ;
      RECT 0.492 886.800 260.316 886.896 ;
      RECT 0.492 889.200 260.316 889.296 ;
      RECT 0.492 891.600 260.316 891.696 ;
      RECT 0.492 894.000 260.316 894.096 ;
      RECT 0.492 896.400 260.316 896.496 ;
      RECT 0.492 898.800 260.316 898.896 ;
      RECT 0.492 901.200 260.316 901.296 ;
      RECT 0.492 903.600 260.316 903.696 ;
      RECT 0.492 906.000 260.316 906.096 ;
      RECT 0.492 908.400 260.316 908.496 ;
      RECT 0.492 910.800 260.316 910.896 ;
      RECT 0.492 913.200 260.316 913.296 ;
      RECT 0.492 915.600 260.316 915.696 ;
      RECT 0.492 918.000 260.316 918.096 ;
      RECT 0.492 920.400 260.316 920.496 ;
      RECT 0.492 922.800 260.316 922.896 ;
      RECT 0.492 925.200 260.316 925.296 ;
      RECT 0.492 927.600 260.316 927.696 ;
      RECT 0.492 930.000 260.316 930.096 ;
      RECT 0.492 932.400 260.316 932.496 ;
      RECT 0.492 934.800 260.316 934.896 ;
      RECT 0.492 937.200 260.316 937.296 ;
      RECT 0.492 939.600 260.316 939.696 ;
      RECT 0.492 942.000 260.316 942.096 ;
      RECT 0.492 944.400 260.316 944.496 ;
      RECT 0.492 946.800 260.316 946.896 ;
      RECT 0.492 949.200 260.316 949.296 ;
      RECT 0.492 951.600 260.316 951.696 ;
      RECT 0.492 954.000 260.316 954.096 ;
      RECT 0.492 956.400 260.316 956.496 ;
      RECT 0.492 958.800 260.316 958.896 ;
      RECT 0.492 961.200 260.316 961.296 ;
      RECT 0.492 963.600 260.316 963.696 ;
      RECT 0.492 966.000 260.316 966.096 ;
      RECT 0.492 968.400 260.316 968.496 ;
      RECT 0.492 970.800 260.316 970.896 ;
      RECT 0.492 973.200 260.316 973.296 ;
      RECT 0.492 975.600 260.316 975.696 ;
      RECT 0.492 978.000 260.316 978.096 ;
      RECT 0.492 980.400 260.316 980.496 ;
      RECT 0.492 982.800 260.316 982.896 ;
      RECT 0.492 985.200 260.316 985.296 ;
      RECT 0.492 987.600 260.316 987.696 ;
      RECT 0.492 990.000 260.316 990.096 ;
      RECT 0.492 992.400 260.316 992.496 ;
      RECT 0.492 994.800 260.316 994.896 ;
      RECT 0.492 997.200 260.316 997.296 ;
      RECT 0.492 999.600 260.316 999.696 ;
      RECT 0.492 1002.000 260.316 1002.096 ;
      RECT 0.492 1004.400 260.316 1004.496 ;
      RECT 0.492 1006.800 260.316 1006.896 ;
      RECT 0.492 1009.200 260.316 1009.296 ;
      RECT 0.492 1011.600 260.316 1011.696 ;
      RECT 0.492 1014.000 260.316 1014.096 ;
      RECT 0.492 1016.400 260.316 1016.496 ;
      RECT 0.492 1018.800 260.316 1018.896 ;
      RECT 0.492 1021.200 260.316 1021.296 ;
      RECT 0.492 1023.600 260.316 1023.696 ;
      RECT 0.492 1026.000 260.316 1026.096 ;
      RECT 0.492 1028.400 260.316 1028.496 ;
      RECT 0.492 1030.800 260.316 1030.896 ;
      RECT 0.492 1033.200 260.316 1033.296 ;
      RECT 0.492 1035.600 260.316 1035.696 ;
      RECT 0.492 1038.000 260.316 1038.096 ;
      RECT 0.492 1040.400 260.316 1040.496 ;
      RECT 0.492 1042.800 260.316 1042.896 ;
      RECT 0.492 1045.200 260.316 1045.296 ;
      RECT 0.492 1047.600 260.316 1047.696 ;
      RECT 0.492 1050.000 260.316 1050.096 ;
      RECT 0.492 1052.400 260.316 1052.496 ;
      RECT 0.492 1054.800 260.316 1054.896 ;
      RECT 0.492 1057.200 260.316 1057.296 ;
      RECT 0.492 1059.600 260.316 1059.696 ;
      RECT 0.492 1062.000 260.316 1062.096 ;
      RECT 0.492 1064.400 260.316 1064.496 ;
      RECT 0.492 1066.800 260.316 1066.896 ;
      RECT 0.492 1069.200 260.316 1069.296 ;
      RECT 0.492 1071.600 260.316 1071.696 ;
      RECT 0.492 1074.000 260.316 1074.096 ;
      RECT 0.492 1076.400 260.316 1076.496 ;
      RECT 0.492 1078.800 260.316 1078.896 ;
      RECT 0.492 1081.200 260.316 1081.296 ;
      RECT 0.492 1083.600 260.316 1083.696 ;
      RECT 0.492 1086.000 260.316 1086.096 ;
      RECT 0.492 1088.400 260.316 1088.496 ;
      RECT 0.492 1090.800 260.316 1090.896 ;
      RECT 0.492 1093.200 260.316 1093.296 ;
      RECT 0.492 1095.600 260.316 1095.696 ;
      RECT 0.492 1098.000 260.316 1098.096 ;
      RECT 0.492 1100.400 260.316 1100.496 ;
      RECT 0.492 1102.800 260.316 1102.896 ;
      RECT 0.492 1105.200 260.316 1105.296 ;
      RECT 0.492 1107.600 260.316 1107.696 ;
      RECT 0.492 1110.000 260.316 1110.096 ;
      RECT 0.492 1112.400 260.316 1112.496 ;
      RECT 0.492 1114.800 260.316 1114.896 ;
      RECT 0.492 1117.200 260.316 1117.296 ;
      RECT 0.492 1119.600 260.316 1119.696 ;
      RECT 0.492 1122.000 260.316 1122.096 ;
      RECT 0.492 1124.400 260.316 1124.496 ;
      RECT 0.492 1126.800 260.316 1126.896 ;
      RECT 0.492 1129.200 260.316 1129.296 ;
      RECT 0.492 1131.600 260.316 1131.696 ;
      RECT 0.492 1134.000 260.316 1134.096 ;
      RECT 0.492 1136.400 260.316 1136.496 ;
      RECT 0.492 1138.800 260.316 1138.896 ;
      RECT 0.492 1141.200 260.316 1141.296 ;
      RECT 0.492 1143.600 260.316 1143.696 ;
      RECT 0.492 1146.000 260.316 1146.096 ;
      RECT 0.492 1148.400 260.316 1148.496 ;
      RECT 0.492 1150.800 260.316 1150.896 ;
      RECT 0.492 1153.200 260.316 1153.296 ;
      RECT 0.492 1155.600 260.316 1155.696 ;
      RECT 0.492 1158.000 260.316 1158.096 ;
      RECT 0.492 1160.400 260.316 1160.496 ;
      RECT 0.492 1162.800 260.316 1162.896 ;
      RECT 0.492 1165.200 260.316 1165.296 ;
      RECT 0.492 1167.600 260.316 1167.696 ;
      RECT 0.492 1170.000 260.316 1170.096 ;
      RECT 0.492 1172.400 260.316 1172.496 ;
      RECT 0.492 1174.800 260.316 1174.896 ;
      RECT 0.492 1177.200 260.316 1177.296 ;
      RECT 0.492 1179.600 260.316 1179.696 ;
      RECT 0.492 1182.000 260.316 1182.096 ;
      RECT 0.492 1184.400 260.316 1184.496 ;
      RECT 0.492 1186.800 260.316 1186.896 ;
      RECT 0.492 1189.200 260.316 1189.296 ;
      RECT 0.492 1191.600 260.316 1191.696 ;
      RECT 0.492 1194.000 260.316 1194.096 ;
      RECT 0.492 1196.400 260.316 1196.496 ;
      RECT 0.492 1198.800 260.316 1198.896 ;
      RECT 0.492 1201.200 260.316 1201.296 ;
      RECT 0.492 1203.600 260.316 1203.696 ;
      RECT 0.492 1206.000 260.316 1206.096 ;
      RECT 0.492 1208.400 260.316 1208.496 ;
      RECT 0.492 1210.800 260.316 1210.896 ;
      RECT 0.492 1213.200 260.316 1213.296 ;
      RECT 0.492 1215.600 260.316 1215.696 ;
      RECT 0.492 1218.000 260.316 1218.096 ;
      RECT 0.492 1220.400 260.316 1220.496 ;
      RECT 0.492 1222.800 260.316 1222.896 ;
      RECT 0.492 1225.200 260.316 1225.296 ;
      RECT 0.492 1227.600 260.316 1227.696 ;
      RECT 0.492 1230.000 260.316 1230.096 ;
      RECT 0.492 1232.400 260.316 1232.496 ;
      RECT 0.492 1234.800 260.316 1234.896 ;
      RECT 0.492 1237.200 260.316 1237.296 ;
      RECT 0.492 1239.600 260.316 1239.696 ;
      RECT 0.492 1242.000 260.316 1242.096 ;
      RECT 0.492 1244.400 260.316 1244.496 ;
      RECT 0.492 1246.800 260.316 1246.896 ;
      RECT 0.492 1249.200 260.316 1249.296 ;
      RECT 0.492 1251.600 260.316 1251.696 ;
      RECT 0.492 1254.000 260.316 1254.096 ;
      RECT 0.492 1256.400 260.316 1256.496 ;
      RECT 0.492 1258.800 260.316 1258.896 ;
      RECT 0.492 1261.200 260.316 1261.296 ;
      RECT 0.492 1263.600 260.316 1263.696 ;
      RECT 0.492 1266.000 260.316 1266.096 ;
      RECT 0.492 1268.400 260.316 1268.496 ;
      RECT 0.492 1270.800 260.316 1270.896 ;
      RECT 0.492 1273.200 260.316 1273.296 ;
      RECT 0.492 1275.600 260.316 1275.696 ;
      RECT 0.492 1278.000 260.316 1278.096 ;
      RECT 0.492 1280.400 260.316 1280.496 ;
      RECT 0.492 1282.800 260.316 1282.896 ;
      RECT 0.492 1285.200 260.316 1285.296 ;
      RECT 0.492 1287.600 260.316 1287.696 ;
      RECT 0.492 1290.000 260.316 1290.096 ;
      RECT 0.492 1292.400 260.316 1292.496 ;
      RECT 0.492 1294.800 260.316 1294.896 ;
      RECT 0.492 1297.200 260.316 1297.296 ;
      RECT 0.492 1299.600 260.316 1299.696 ;
      RECT 0.492 1302.000 260.316 1302.096 ;
      RECT 0.492 1304.400 260.316 1304.496 ;
      RECT 0.492 1306.800 260.316 1306.896 ;
      RECT 0.492 1309.200 260.316 1309.296 ;
      RECT 0.492 1311.600 260.316 1311.696 ;
      RECT 0.492 1314.000 260.316 1314.096 ;
      RECT 0.492 1316.400 260.316 1316.496 ;
      RECT 0.492 1318.800 260.316 1318.896 ;
      RECT 0.492 1321.200 260.316 1321.296 ;
      RECT 0.492 1323.600 260.316 1323.696 ;
      RECT 0.492 1326.000 260.316 1326.096 ;
      RECT 0.492 1328.400 260.316 1328.496 ;
      RECT 0.492 1330.800 260.316 1330.896 ;
      RECT 0.492 1333.200 260.316 1333.296 ;
      RECT 0.492 1335.600 260.316 1335.696 ;
      RECT 0.492 1338.000 260.316 1338.096 ;
      RECT 0.492 1340.400 260.316 1340.496 ;
      RECT 0.492 1342.800 260.316 1342.896 ;
      RECT 0.492 1345.200 260.316 1345.296 ;
      RECT 0.492 1347.600 260.316 1347.696 ;
      RECT 0.492 1350.000 260.316 1350.096 ;
      RECT 0.492 1352.400 260.316 1352.496 ;
      RECT 0.492 1354.800 260.316 1354.896 ;
      RECT 0.492 1357.200 260.316 1357.296 ;
      RECT 0.492 1359.600 260.316 1359.696 ;
      RECT 0.492 1362.000 260.316 1362.096 ;
      RECT 0.492 1364.400 260.316 1364.496 ;
      RECT 0.492 1366.800 260.316 1366.896 ;
      RECT 0.492 1369.200 260.316 1369.296 ;
      RECT 0.492 1371.600 260.316 1371.696 ;
      RECT 0.492 1374.000 260.316 1374.096 ;
      RECT 0.492 1376.400 260.316 1376.496 ;
      RECT 0.492 1378.800 260.316 1378.896 ;
      RECT 0.492 1381.200 260.316 1381.296 ;
      RECT 0.492 1383.600 260.316 1383.696 ;
      RECT 0.492 1386.000 260.316 1386.096 ;
      RECT 0.492 1388.400 260.316 1388.496 ;
      RECT 0.492 1390.800 260.316 1390.896 ;
      RECT 0.492 1393.200 260.316 1393.296 ;
      RECT 0.492 1395.600 260.316 1395.696 ;
      RECT 0.492 1398.000 260.316 1398.096 ;
      RECT 0.492 1400.400 260.316 1400.496 ;
      RECT 0.492 1402.800 260.316 1402.896 ;
      RECT 0.492 1405.200 260.316 1405.296 ;
      RECT 0.492 1407.600 260.316 1407.696 ;
      RECT 0.492 1410.000 260.316 1410.096 ;
      RECT 0.492 1412.400 260.316 1412.496 ;
      RECT 0.492 1414.800 260.316 1414.896 ;
      RECT 0.492 1417.200 260.316 1417.296 ;
      RECT 0.492 1419.600 260.316 1419.696 ;
      RECT 0.492 1422.000 260.316 1422.096 ;
      RECT 0.492 1424.400 260.316 1424.496 ;
      RECT 0.492 1426.800 260.316 1426.896 ;
      RECT 0.492 1429.200 260.316 1429.296 ;
      RECT 0.492 1431.600 260.316 1431.696 ;
      RECT 0.492 1434.000 260.316 1434.096 ;
      RECT 0.492 1436.400 260.316 1436.496 ;
      RECT 0.492 1438.800 260.316 1438.896 ;
      RECT 0.492 1441.200 260.316 1441.296 ;
      RECT 0.492 1443.600 260.316 1443.696 ;
      RECT 0.492 1446.000 260.316 1446.096 ;
      RECT 0.492 1448.400 260.316 1448.496 ;
      RECT 0.492 1450.800 260.316 1450.896 ;
      RECT 0.492 1453.200 260.316 1453.296 ;
      RECT 0.492 1455.600 260.316 1455.696 ;
      RECT 0.492 1458.000 260.316 1458.096 ;
      RECT 0.492 1460.400 260.316 1460.496 ;
      RECT 0.492 1462.800 260.316 1462.896 ;
      RECT 0.492 1465.200 260.316 1465.296 ;
      RECT 0.492 1467.600 260.316 1467.696 ;
      RECT 0.492 1470.000 260.316 1470.096 ;
      RECT 0.492 1472.400 260.316 1472.496 ;
      RECT 0.492 1474.800 260.316 1474.896 ;
      RECT 0.492 1477.200 260.316 1477.296 ;
      RECT 0.492 1479.600 260.316 1479.696 ;
      RECT 0.492 1482.000 260.316 1482.096 ;
      RECT 0.492 1484.400 260.316 1484.496 ;
      RECT 0.492 1486.800 260.316 1486.896 ;
      RECT 0.492 1489.200 260.316 1489.296 ;
      RECT 0.492 1491.600 260.316 1491.696 ;
      RECT 0.492 1494.000 260.316 1494.096 ;
      RECT 0.492 1496.400 260.316 1496.496 ;
      RECT 0.492 1498.800 260.316 1498.896 ;
      RECT 0.492 1501.200 260.316 1501.296 ;
      RECT 0.492 1503.600 260.316 1503.696 ;
      RECT 0.492 1506.000 260.316 1506.096 ;
      RECT 0.492 1508.400 260.316 1508.496 ;
      RECT 0.492 1510.800 260.316 1510.896 ;
      RECT 0.492 1513.200 260.316 1513.296 ;
      RECT 0.492 1515.600 260.316 1515.696 ;
      RECT 0.492 1518.000 260.316 1518.096 ;
      RECT 0.492 1520.400 260.316 1520.496 ;
      RECT 0.492 1522.800 260.316 1522.896 ;
      RECT 0.492 1525.200 260.316 1525.296 ;
      RECT 0.492 1527.600 260.316 1527.696 ;
      RECT 0.492 1530.000 260.316 1530.096 ;
      RECT 0.492 1532.400 260.316 1532.496 ;
      RECT 0.492 1534.800 260.316 1534.896 ;
      RECT 0.492 1537.200 260.316 1537.296 ;
      RECT 0.492 1539.600 260.316 1539.696 ;
      RECT 0.492 1542.000 260.316 1542.096 ;
      RECT 0.492 1544.400 260.316 1544.496 ;
      RECT 0.492 1546.800 260.316 1546.896 ;
      RECT 0.492 1549.200 260.316 1549.296 ;
      RECT 0.492 1551.600 260.316 1551.696 ;
      RECT 0.492 1554.000 260.316 1554.096 ;
      RECT 0.492 1556.400 260.316 1556.496 ;
      RECT 0.492 1558.800 260.316 1558.896 ;
      RECT 0.492 1561.200 260.316 1561.296 ;
      RECT 0.492 1563.600 260.316 1563.696 ;
      RECT 0.492 1566.000 260.316 1566.096 ;
      RECT 0.492 1568.400 260.316 1568.496 ;
      RECT 0.492 1570.800 260.316 1570.896 ;
      RECT 0.492 1573.200 260.316 1573.296 ;
      RECT 0.492 1575.600 260.316 1575.696 ;
      RECT 0.492 1578.000 260.316 1578.096 ;
      RECT 0.492 1580.400 260.316 1580.496 ;
      RECT 0.492 1582.800 260.316 1582.896 ;
      RECT 0.492 1585.200 260.316 1585.296 ;
      RECT 0.492 1587.600 260.316 1587.696 ;
      RECT 0.492 1590.000 260.316 1590.096 ;
      RECT 0.492 1592.400 260.316 1592.496 ;
      RECT 0.492 1594.800 260.316 1594.896 ;
      RECT 0.492 1597.200 260.316 1597.296 ;
      RECT 0.492 1599.600 260.316 1599.696 ;
      RECT 0.492 1602.000 260.316 1602.096 ;
      RECT 0.492 1604.400 260.316 1604.496 ;
      RECT 0.492 1606.800 260.316 1606.896 ;
      RECT 0.492 1609.200 260.316 1609.296 ;
      RECT 0.492 1611.600 260.316 1611.696 ;
      RECT 0.492 1614.000 260.316 1614.096 ;
      RECT 0.492 1616.400 260.316 1616.496 ;
      RECT 0.492 1618.800 260.316 1618.896 ;
      RECT 0.492 1621.200 260.316 1621.296 ;
      RECT 0.492 1623.600 260.316 1623.696 ;
      RECT 0.492 1626.000 260.316 1626.096 ;
      RECT 0.492 1628.400 260.316 1628.496 ;
      RECT 0.492 1630.800 260.316 1630.896 ;
      RECT 0.492 1633.200 260.316 1633.296 ;
      RECT 0.492 1635.600 260.316 1635.696 ;
      RECT 0.492 1638.000 260.316 1638.096 ;
      RECT 0.492 1640.400 260.316 1640.496 ;
      RECT 0.492 1642.800 260.316 1642.896 ;
      RECT 0.492 1645.200 260.316 1645.296 ;
      RECT 0.492 1647.600 260.316 1647.696 ;
      RECT 0.492 1650.000 260.316 1650.096 ;
    END
  END VSS
  PIN VDD
    DIRECTION INOUT ;
    USE POWER ;
    PORT
      LAYER M4 ;
      RECT 0.492 2.400 260.316 2.496 ;
      RECT 0.492 4.800 260.316 4.896 ;
      RECT 0.492 7.200 260.316 7.296 ;
      RECT 0.492 9.600 260.316 9.696 ;
      RECT 0.492 12.000 260.316 12.096 ;
      RECT 0.492 14.400 260.316 14.496 ;
      RECT 0.492 16.800 260.316 16.896 ;
      RECT 0.492 19.200 260.316 19.296 ;
      RECT 0.492 21.600 260.316 21.696 ;
      RECT 0.492 24.000 260.316 24.096 ;
      RECT 0.492 26.400 260.316 26.496 ;
      RECT 0.492 28.800 260.316 28.896 ;
      RECT 0.492 31.200 260.316 31.296 ;
      RECT 0.492 33.600 260.316 33.696 ;
      RECT 0.492 36.000 260.316 36.096 ;
      RECT 0.492 38.400 260.316 38.496 ;
      RECT 0.492 40.800 260.316 40.896 ;
      RECT 0.492 43.200 260.316 43.296 ;
      RECT 0.492 45.600 260.316 45.696 ;
      RECT 0.492 48.000 260.316 48.096 ;
      RECT 0.492 50.400 260.316 50.496 ;
      RECT 0.492 52.800 260.316 52.896 ;
      RECT 0.492 55.200 260.316 55.296 ;
      RECT 0.492 57.600 260.316 57.696 ;
      RECT 0.492 60.000 260.316 60.096 ;
      RECT 0.492 62.400 260.316 62.496 ;
      RECT 0.492 64.800 260.316 64.896 ;
      RECT 0.492 67.200 260.316 67.296 ;
      RECT 0.492 69.600 260.316 69.696 ;
      RECT 0.492 72.000 260.316 72.096 ;
      RECT 0.492 74.400 260.316 74.496 ;
      RECT 0.492 76.800 260.316 76.896 ;
      RECT 0.492 79.200 260.316 79.296 ;
      RECT 0.492 81.600 260.316 81.696 ;
      RECT 0.492 84.000 260.316 84.096 ;
      RECT 0.492 86.400 260.316 86.496 ;
      RECT 0.492 88.800 260.316 88.896 ;
      RECT 0.492 91.200 260.316 91.296 ;
      RECT 0.492 93.600 260.316 93.696 ;
      RECT 0.492 96.000 260.316 96.096 ;
      RECT 0.492 98.400 260.316 98.496 ;
      RECT 0.492 100.800 260.316 100.896 ;
      RECT 0.492 103.200 260.316 103.296 ;
      RECT 0.492 105.600 260.316 105.696 ;
      RECT 0.492 108.000 260.316 108.096 ;
      RECT 0.492 110.400 260.316 110.496 ;
      RECT 0.492 112.800 260.316 112.896 ;
      RECT 0.492 115.200 260.316 115.296 ;
      RECT 0.492 117.600 260.316 117.696 ;
      RECT 0.492 120.000 260.316 120.096 ;
      RECT 0.492 122.400 260.316 122.496 ;
      RECT 0.492 124.800 260.316 124.896 ;
      RECT 0.492 127.200 260.316 127.296 ;
      RECT 0.492 129.600 260.316 129.696 ;
      RECT 0.492 132.000 260.316 132.096 ;
      RECT 0.492 134.400 260.316 134.496 ;
      RECT 0.492 136.800 260.316 136.896 ;
      RECT 0.492 139.200 260.316 139.296 ;
      RECT 0.492 141.600 260.316 141.696 ;
      RECT 0.492 144.000 260.316 144.096 ;
      RECT 0.492 146.400 260.316 146.496 ;
      RECT 0.492 148.800 260.316 148.896 ;
      RECT 0.492 151.200 260.316 151.296 ;
      RECT 0.492 153.600 260.316 153.696 ;
      RECT 0.492 156.000 260.316 156.096 ;
      RECT 0.492 158.400 260.316 158.496 ;
      RECT 0.492 160.800 260.316 160.896 ;
      RECT 0.492 163.200 260.316 163.296 ;
      RECT 0.492 165.600 260.316 165.696 ;
      RECT 0.492 168.000 260.316 168.096 ;
      RECT 0.492 170.400 260.316 170.496 ;
      RECT 0.492 172.800 260.316 172.896 ;
      RECT 0.492 175.200 260.316 175.296 ;
      RECT 0.492 177.600 260.316 177.696 ;
      RECT 0.492 180.000 260.316 180.096 ;
      RECT 0.492 182.400 260.316 182.496 ;
      RECT 0.492 184.800 260.316 184.896 ;
      RECT 0.492 187.200 260.316 187.296 ;
      RECT 0.492 189.600 260.316 189.696 ;
      RECT 0.492 192.000 260.316 192.096 ;
      RECT 0.492 194.400 260.316 194.496 ;
      RECT 0.492 196.800 260.316 196.896 ;
      RECT 0.492 199.200 260.316 199.296 ;
      RECT 0.492 201.600 260.316 201.696 ;
      RECT 0.492 204.000 260.316 204.096 ;
      RECT 0.492 206.400 260.316 206.496 ;
      RECT 0.492 208.800 260.316 208.896 ;
      RECT 0.492 211.200 260.316 211.296 ;
      RECT 0.492 213.600 260.316 213.696 ;
      RECT 0.492 216.000 260.316 216.096 ;
      RECT 0.492 218.400 260.316 218.496 ;
      RECT 0.492 220.800 260.316 220.896 ;
      RECT 0.492 223.200 260.316 223.296 ;
      RECT 0.492 225.600 260.316 225.696 ;
      RECT 0.492 228.000 260.316 228.096 ;
      RECT 0.492 230.400 260.316 230.496 ;
      RECT 0.492 232.800 260.316 232.896 ;
      RECT 0.492 235.200 260.316 235.296 ;
      RECT 0.492 237.600 260.316 237.696 ;
      RECT 0.492 240.000 260.316 240.096 ;
      RECT 0.492 242.400 260.316 242.496 ;
      RECT 0.492 244.800 260.316 244.896 ;
      RECT 0.492 247.200 260.316 247.296 ;
      RECT 0.492 249.600 260.316 249.696 ;
      RECT 0.492 252.000 260.316 252.096 ;
      RECT 0.492 254.400 260.316 254.496 ;
      RECT 0.492 256.800 260.316 256.896 ;
      RECT 0.492 259.200 260.316 259.296 ;
      RECT 0.492 261.600 260.316 261.696 ;
      RECT 0.492 264.000 260.316 264.096 ;
      RECT 0.492 266.400 260.316 266.496 ;
      RECT 0.492 268.800 260.316 268.896 ;
      RECT 0.492 271.200 260.316 271.296 ;
      RECT 0.492 273.600 260.316 273.696 ;
      RECT 0.492 276.000 260.316 276.096 ;
      RECT 0.492 278.400 260.316 278.496 ;
      RECT 0.492 280.800 260.316 280.896 ;
      RECT 0.492 283.200 260.316 283.296 ;
      RECT 0.492 285.600 260.316 285.696 ;
      RECT 0.492 288.000 260.316 288.096 ;
      RECT 0.492 290.400 260.316 290.496 ;
      RECT 0.492 292.800 260.316 292.896 ;
      RECT 0.492 295.200 260.316 295.296 ;
      RECT 0.492 297.600 260.316 297.696 ;
      RECT 0.492 300.000 260.316 300.096 ;
      RECT 0.492 302.400 260.316 302.496 ;
      RECT 0.492 304.800 260.316 304.896 ;
      RECT 0.492 307.200 260.316 307.296 ;
      RECT 0.492 309.600 260.316 309.696 ;
      RECT 0.492 312.000 260.316 312.096 ;
      RECT 0.492 314.400 260.316 314.496 ;
      RECT 0.492 316.800 260.316 316.896 ;
      RECT 0.492 319.200 260.316 319.296 ;
      RECT 0.492 321.600 260.316 321.696 ;
      RECT 0.492 324.000 260.316 324.096 ;
      RECT 0.492 326.400 260.316 326.496 ;
      RECT 0.492 328.800 260.316 328.896 ;
      RECT 0.492 331.200 260.316 331.296 ;
      RECT 0.492 333.600 260.316 333.696 ;
      RECT 0.492 336.000 260.316 336.096 ;
      RECT 0.492 338.400 260.316 338.496 ;
      RECT 0.492 340.800 260.316 340.896 ;
      RECT 0.492 343.200 260.316 343.296 ;
      RECT 0.492 345.600 260.316 345.696 ;
      RECT 0.492 348.000 260.316 348.096 ;
      RECT 0.492 350.400 260.316 350.496 ;
      RECT 0.492 352.800 260.316 352.896 ;
      RECT 0.492 355.200 260.316 355.296 ;
      RECT 0.492 357.600 260.316 357.696 ;
      RECT 0.492 360.000 260.316 360.096 ;
      RECT 0.492 362.400 260.316 362.496 ;
      RECT 0.492 364.800 260.316 364.896 ;
      RECT 0.492 367.200 260.316 367.296 ;
      RECT 0.492 369.600 260.316 369.696 ;
      RECT 0.492 372.000 260.316 372.096 ;
      RECT 0.492 374.400 260.316 374.496 ;
      RECT 0.492 376.800 260.316 376.896 ;
      RECT 0.492 379.200 260.316 379.296 ;
      RECT 0.492 381.600 260.316 381.696 ;
      RECT 0.492 384.000 260.316 384.096 ;
      RECT 0.492 386.400 260.316 386.496 ;
      RECT 0.492 388.800 260.316 388.896 ;
      RECT 0.492 391.200 260.316 391.296 ;
      RECT 0.492 393.600 260.316 393.696 ;
      RECT 0.492 396.000 260.316 396.096 ;
      RECT 0.492 398.400 260.316 398.496 ;
      RECT 0.492 400.800 260.316 400.896 ;
      RECT 0.492 403.200 260.316 403.296 ;
      RECT 0.492 405.600 260.316 405.696 ;
      RECT 0.492 408.000 260.316 408.096 ;
      RECT 0.492 410.400 260.316 410.496 ;
      RECT 0.492 412.800 260.316 412.896 ;
      RECT 0.492 415.200 260.316 415.296 ;
      RECT 0.492 417.600 260.316 417.696 ;
      RECT 0.492 420.000 260.316 420.096 ;
      RECT 0.492 422.400 260.316 422.496 ;
      RECT 0.492 424.800 260.316 424.896 ;
      RECT 0.492 427.200 260.316 427.296 ;
      RECT 0.492 429.600 260.316 429.696 ;
      RECT 0.492 432.000 260.316 432.096 ;
      RECT 0.492 434.400 260.316 434.496 ;
      RECT 0.492 436.800 260.316 436.896 ;
      RECT 0.492 439.200 260.316 439.296 ;
      RECT 0.492 441.600 260.316 441.696 ;
      RECT 0.492 444.000 260.316 444.096 ;
      RECT 0.492 446.400 260.316 446.496 ;
      RECT 0.492 448.800 260.316 448.896 ;
      RECT 0.492 451.200 260.316 451.296 ;
      RECT 0.492 453.600 260.316 453.696 ;
      RECT 0.492 456.000 260.316 456.096 ;
      RECT 0.492 458.400 260.316 458.496 ;
      RECT 0.492 460.800 260.316 460.896 ;
      RECT 0.492 463.200 260.316 463.296 ;
      RECT 0.492 465.600 260.316 465.696 ;
      RECT 0.492 468.000 260.316 468.096 ;
      RECT 0.492 470.400 260.316 470.496 ;
      RECT 0.492 472.800 260.316 472.896 ;
      RECT 0.492 475.200 260.316 475.296 ;
      RECT 0.492 477.600 260.316 477.696 ;
      RECT 0.492 480.000 260.316 480.096 ;
      RECT 0.492 482.400 260.316 482.496 ;
      RECT 0.492 484.800 260.316 484.896 ;
      RECT 0.492 487.200 260.316 487.296 ;
      RECT 0.492 489.600 260.316 489.696 ;
      RECT 0.492 492.000 260.316 492.096 ;
      RECT 0.492 494.400 260.316 494.496 ;
      RECT 0.492 496.800 260.316 496.896 ;
      RECT 0.492 499.200 260.316 499.296 ;
      RECT 0.492 501.600 260.316 501.696 ;
      RECT 0.492 504.000 260.316 504.096 ;
      RECT 0.492 506.400 260.316 506.496 ;
      RECT 0.492 508.800 260.316 508.896 ;
      RECT 0.492 511.200 260.316 511.296 ;
      RECT 0.492 513.600 260.316 513.696 ;
      RECT 0.492 516.000 260.316 516.096 ;
      RECT 0.492 518.400 260.316 518.496 ;
      RECT 0.492 520.800 260.316 520.896 ;
      RECT 0.492 523.200 260.316 523.296 ;
      RECT 0.492 525.600 260.316 525.696 ;
      RECT 0.492 528.000 260.316 528.096 ;
      RECT 0.492 530.400 260.316 530.496 ;
      RECT 0.492 532.800 260.316 532.896 ;
      RECT 0.492 535.200 260.316 535.296 ;
      RECT 0.492 537.600 260.316 537.696 ;
      RECT 0.492 540.000 260.316 540.096 ;
      RECT 0.492 542.400 260.316 542.496 ;
      RECT 0.492 544.800 260.316 544.896 ;
      RECT 0.492 547.200 260.316 547.296 ;
      RECT 0.492 549.600 260.316 549.696 ;
      RECT 0.492 552.000 260.316 552.096 ;
      RECT 0.492 554.400 260.316 554.496 ;
      RECT 0.492 556.800 260.316 556.896 ;
      RECT 0.492 559.200 260.316 559.296 ;
      RECT 0.492 561.600 260.316 561.696 ;
      RECT 0.492 564.000 260.316 564.096 ;
      RECT 0.492 566.400 260.316 566.496 ;
      RECT 0.492 568.800 260.316 568.896 ;
      RECT 0.492 571.200 260.316 571.296 ;
      RECT 0.492 573.600 260.316 573.696 ;
      RECT 0.492 576.000 260.316 576.096 ;
      RECT 0.492 578.400 260.316 578.496 ;
      RECT 0.492 580.800 260.316 580.896 ;
      RECT 0.492 583.200 260.316 583.296 ;
      RECT 0.492 585.600 260.316 585.696 ;
      RECT 0.492 588.000 260.316 588.096 ;
      RECT 0.492 590.400 260.316 590.496 ;
      RECT 0.492 592.800 260.316 592.896 ;
      RECT 0.492 595.200 260.316 595.296 ;
      RECT 0.492 597.600 260.316 597.696 ;
      RECT 0.492 600.000 260.316 600.096 ;
      RECT 0.492 602.400 260.316 602.496 ;
      RECT 0.492 604.800 260.316 604.896 ;
      RECT 0.492 607.200 260.316 607.296 ;
      RECT 0.492 609.600 260.316 609.696 ;
      RECT 0.492 612.000 260.316 612.096 ;
      RECT 0.492 614.400 260.316 614.496 ;
      RECT 0.492 616.800 260.316 616.896 ;
      RECT 0.492 619.200 260.316 619.296 ;
      RECT 0.492 621.600 260.316 621.696 ;
      RECT 0.492 624.000 260.316 624.096 ;
      RECT 0.492 626.400 260.316 626.496 ;
      RECT 0.492 628.800 260.316 628.896 ;
      RECT 0.492 631.200 260.316 631.296 ;
      RECT 0.492 633.600 260.316 633.696 ;
      RECT 0.492 636.000 260.316 636.096 ;
      RECT 0.492 638.400 260.316 638.496 ;
      RECT 0.492 640.800 260.316 640.896 ;
      RECT 0.492 643.200 260.316 643.296 ;
      RECT 0.492 645.600 260.316 645.696 ;
      RECT 0.492 648.000 260.316 648.096 ;
      RECT 0.492 650.400 260.316 650.496 ;
      RECT 0.492 652.800 260.316 652.896 ;
      RECT 0.492 655.200 260.316 655.296 ;
      RECT 0.492 657.600 260.316 657.696 ;
      RECT 0.492 660.000 260.316 660.096 ;
      RECT 0.492 662.400 260.316 662.496 ;
      RECT 0.492 664.800 260.316 664.896 ;
      RECT 0.492 667.200 260.316 667.296 ;
      RECT 0.492 669.600 260.316 669.696 ;
      RECT 0.492 672.000 260.316 672.096 ;
      RECT 0.492 674.400 260.316 674.496 ;
      RECT 0.492 676.800 260.316 676.896 ;
      RECT 0.492 679.200 260.316 679.296 ;
      RECT 0.492 681.600 260.316 681.696 ;
      RECT 0.492 684.000 260.316 684.096 ;
      RECT 0.492 686.400 260.316 686.496 ;
      RECT 0.492 688.800 260.316 688.896 ;
      RECT 0.492 691.200 260.316 691.296 ;
      RECT 0.492 693.600 260.316 693.696 ;
      RECT 0.492 696.000 260.316 696.096 ;
      RECT 0.492 698.400 260.316 698.496 ;
      RECT 0.492 700.800 260.316 700.896 ;
      RECT 0.492 703.200 260.316 703.296 ;
      RECT 0.492 705.600 260.316 705.696 ;
      RECT 0.492 708.000 260.316 708.096 ;
      RECT 0.492 710.400 260.316 710.496 ;
      RECT 0.492 712.800 260.316 712.896 ;
      RECT 0.492 715.200 260.316 715.296 ;
      RECT 0.492 717.600 260.316 717.696 ;
      RECT 0.492 720.000 260.316 720.096 ;
      RECT 0.492 722.400 260.316 722.496 ;
      RECT 0.492 724.800 260.316 724.896 ;
      RECT 0.492 727.200 260.316 727.296 ;
      RECT 0.492 729.600 260.316 729.696 ;
      RECT 0.492 732.000 260.316 732.096 ;
      RECT 0.492 734.400 260.316 734.496 ;
      RECT 0.492 736.800 260.316 736.896 ;
      RECT 0.492 739.200 260.316 739.296 ;
      RECT 0.492 741.600 260.316 741.696 ;
      RECT 0.492 744.000 260.316 744.096 ;
      RECT 0.492 746.400 260.316 746.496 ;
      RECT 0.492 748.800 260.316 748.896 ;
      RECT 0.492 751.200 260.316 751.296 ;
      RECT 0.492 753.600 260.316 753.696 ;
      RECT 0.492 756.000 260.316 756.096 ;
      RECT 0.492 758.400 260.316 758.496 ;
      RECT 0.492 760.800 260.316 760.896 ;
      RECT 0.492 763.200 260.316 763.296 ;
      RECT 0.492 765.600 260.316 765.696 ;
      RECT 0.492 768.000 260.316 768.096 ;
      RECT 0.492 770.400 260.316 770.496 ;
      RECT 0.492 772.800 260.316 772.896 ;
      RECT 0.492 775.200 260.316 775.296 ;
      RECT 0.492 777.600 260.316 777.696 ;
      RECT 0.492 780.000 260.316 780.096 ;
      RECT 0.492 782.400 260.316 782.496 ;
      RECT 0.492 784.800 260.316 784.896 ;
      RECT 0.492 787.200 260.316 787.296 ;
      RECT 0.492 789.600 260.316 789.696 ;
      RECT 0.492 792.000 260.316 792.096 ;
      RECT 0.492 794.400 260.316 794.496 ;
      RECT 0.492 796.800 260.316 796.896 ;
      RECT 0.492 799.200 260.316 799.296 ;
      RECT 0.492 801.600 260.316 801.696 ;
      RECT 0.492 804.000 260.316 804.096 ;
      RECT 0.492 806.400 260.316 806.496 ;
      RECT 0.492 808.800 260.316 808.896 ;
      RECT 0.492 811.200 260.316 811.296 ;
      RECT 0.492 813.600 260.316 813.696 ;
      RECT 0.492 816.000 260.316 816.096 ;
      RECT 0.492 818.400 260.316 818.496 ;
      RECT 0.492 820.800 260.316 820.896 ;
      RECT 0.492 823.200 260.316 823.296 ;
      RECT 0.492 825.600 260.316 825.696 ;
      RECT 0.492 828.000 260.316 828.096 ;
      RECT 0.492 830.400 260.316 830.496 ;
      RECT 0.492 832.800 260.316 832.896 ;
      RECT 0.492 835.200 260.316 835.296 ;
      RECT 0.492 837.600 260.316 837.696 ;
      RECT 0.492 840.000 260.316 840.096 ;
      RECT 0.492 842.400 260.316 842.496 ;
      RECT 0.492 844.800 260.316 844.896 ;
      RECT 0.492 847.200 260.316 847.296 ;
      RECT 0.492 849.600 260.316 849.696 ;
      RECT 0.492 852.000 260.316 852.096 ;
      RECT 0.492 854.400 260.316 854.496 ;
      RECT 0.492 856.800 260.316 856.896 ;
      RECT 0.492 859.200 260.316 859.296 ;
      RECT 0.492 861.600 260.316 861.696 ;
      RECT 0.492 864.000 260.316 864.096 ;
      RECT 0.492 866.400 260.316 866.496 ;
      RECT 0.492 868.800 260.316 868.896 ;
      RECT 0.492 871.200 260.316 871.296 ;
      RECT 0.492 873.600 260.316 873.696 ;
      RECT 0.492 876.000 260.316 876.096 ;
      RECT 0.492 878.400 260.316 878.496 ;
      RECT 0.492 880.800 260.316 880.896 ;
      RECT 0.492 883.200 260.316 883.296 ;
      RECT 0.492 885.600 260.316 885.696 ;
      RECT 0.492 888.000 260.316 888.096 ;
      RECT 0.492 890.400 260.316 890.496 ;
      RECT 0.492 892.800 260.316 892.896 ;
      RECT 0.492 895.200 260.316 895.296 ;
      RECT 0.492 897.600 260.316 897.696 ;
      RECT 0.492 900.000 260.316 900.096 ;
      RECT 0.492 902.400 260.316 902.496 ;
      RECT 0.492 904.800 260.316 904.896 ;
      RECT 0.492 907.200 260.316 907.296 ;
      RECT 0.492 909.600 260.316 909.696 ;
      RECT 0.492 912.000 260.316 912.096 ;
      RECT 0.492 914.400 260.316 914.496 ;
      RECT 0.492 916.800 260.316 916.896 ;
      RECT 0.492 919.200 260.316 919.296 ;
      RECT 0.492 921.600 260.316 921.696 ;
      RECT 0.492 924.000 260.316 924.096 ;
      RECT 0.492 926.400 260.316 926.496 ;
      RECT 0.492 928.800 260.316 928.896 ;
      RECT 0.492 931.200 260.316 931.296 ;
      RECT 0.492 933.600 260.316 933.696 ;
      RECT 0.492 936.000 260.316 936.096 ;
      RECT 0.492 938.400 260.316 938.496 ;
      RECT 0.492 940.800 260.316 940.896 ;
      RECT 0.492 943.200 260.316 943.296 ;
      RECT 0.492 945.600 260.316 945.696 ;
      RECT 0.492 948.000 260.316 948.096 ;
      RECT 0.492 950.400 260.316 950.496 ;
      RECT 0.492 952.800 260.316 952.896 ;
      RECT 0.492 955.200 260.316 955.296 ;
      RECT 0.492 957.600 260.316 957.696 ;
      RECT 0.492 960.000 260.316 960.096 ;
      RECT 0.492 962.400 260.316 962.496 ;
      RECT 0.492 964.800 260.316 964.896 ;
      RECT 0.492 967.200 260.316 967.296 ;
      RECT 0.492 969.600 260.316 969.696 ;
      RECT 0.492 972.000 260.316 972.096 ;
      RECT 0.492 974.400 260.316 974.496 ;
      RECT 0.492 976.800 260.316 976.896 ;
      RECT 0.492 979.200 260.316 979.296 ;
      RECT 0.492 981.600 260.316 981.696 ;
      RECT 0.492 984.000 260.316 984.096 ;
      RECT 0.492 986.400 260.316 986.496 ;
      RECT 0.492 988.800 260.316 988.896 ;
      RECT 0.492 991.200 260.316 991.296 ;
      RECT 0.492 993.600 260.316 993.696 ;
      RECT 0.492 996.000 260.316 996.096 ;
      RECT 0.492 998.400 260.316 998.496 ;
      RECT 0.492 1000.800 260.316 1000.896 ;
      RECT 0.492 1003.200 260.316 1003.296 ;
      RECT 0.492 1005.600 260.316 1005.696 ;
      RECT 0.492 1008.000 260.316 1008.096 ;
      RECT 0.492 1010.400 260.316 1010.496 ;
      RECT 0.492 1012.800 260.316 1012.896 ;
      RECT 0.492 1015.200 260.316 1015.296 ;
      RECT 0.492 1017.600 260.316 1017.696 ;
      RECT 0.492 1020.000 260.316 1020.096 ;
      RECT 0.492 1022.400 260.316 1022.496 ;
      RECT 0.492 1024.800 260.316 1024.896 ;
      RECT 0.492 1027.200 260.316 1027.296 ;
      RECT 0.492 1029.600 260.316 1029.696 ;
      RECT 0.492 1032.000 260.316 1032.096 ;
      RECT 0.492 1034.400 260.316 1034.496 ;
      RECT 0.492 1036.800 260.316 1036.896 ;
      RECT 0.492 1039.200 260.316 1039.296 ;
      RECT 0.492 1041.600 260.316 1041.696 ;
      RECT 0.492 1044.000 260.316 1044.096 ;
      RECT 0.492 1046.400 260.316 1046.496 ;
      RECT 0.492 1048.800 260.316 1048.896 ;
      RECT 0.492 1051.200 260.316 1051.296 ;
      RECT 0.492 1053.600 260.316 1053.696 ;
      RECT 0.492 1056.000 260.316 1056.096 ;
      RECT 0.492 1058.400 260.316 1058.496 ;
      RECT 0.492 1060.800 260.316 1060.896 ;
      RECT 0.492 1063.200 260.316 1063.296 ;
      RECT 0.492 1065.600 260.316 1065.696 ;
      RECT 0.492 1068.000 260.316 1068.096 ;
      RECT 0.492 1070.400 260.316 1070.496 ;
      RECT 0.492 1072.800 260.316 1072.896 ;
      RECT 0.492 1075.200 260.316 1075.296 ;
      RECT 0.492 1077.600 260.316 1077.696 ;
      RECT 0.492 1080.000 260.316 1080.096 ;
      RECT 0.492 1082.400 260.316 1082.496 ;
      RECT 0.492 1084.800 260.316 1084.896 ;
      RECT 0.492 1087.200 260.316 1087.296 ;
      RECT 0.492 1089.600 260.316 1089.696 ;
      RECT 0.492 1092.000 260.316 1092.096 ;
      RECT 0.492 1094.400 260.316 1094.496 ;
      RECT 0.492 1096.800 260.316 1096.896 ;
      RECT 0.492 1099.200 260.316 1099.296 ;
      RECT 0.492 1101.600 260.316 1101.696 ;
      RECT 0.492 1104.000 260.316 1104.096 ;
      RECT 0.492 1106.400 260.316 1106.496 ;
      RECT 0.492 1108.800 260.316 1108.896 ;
      RECT 0.492 1111.200 260.316 1111.296 ;
      RECT 0.492 1113.600 260.316 1113.696 ;
      RECT 0.492 1116.000 260.316 1116.096 ;
      RECT 0.492 1118.400 260.316 1118.496 ;
      RECT 0.492 1120.800 260.316 1120.896 ;
      RECT 0.492 1123.200 260.316 1123.296 ;
      RECT 0.492 1125.600 260.316 1125.696 ;
      RECT 0.492 1128.000 260.316 1128.096 ;
      RECT 0.492 1130.400 260.316 1130.496 ;
      RECT 0.492 1132.800 260.316 1132.896 ;
      RECT 0.492 1135.200 260.316 1135.296 ;
      RECT 0.492 1137.600 260.316 1137.696 ;
      RECT 0.492 1140.000 260.316 1140.096 ;
      RECT 0.492 1142.400 260.316 1142.496 ;
      RECT 0.492 1144.800 260.316 1144.896 ;
      RECT 0.492 1147.200 260.316 1147.296 ;
      RECT 0.492 1149.600 260.316 1149.696 ;
      RECT 0.492 1152.000 260.316 1152.096 ;
      RECT 0.492 1154.400 260.316 1154.496 ;
      RECT 0.492 1156.800 260.316 1156.896 ;
      RECT 0.492 1159.200 260.316 1159.296 ;
      RECT 0.492 1161.600 260.316 1161.696 ;
      RECT 0.492 1164.000 260.316 1164.096 ;
      RECT 0.492 1166.400 260.316 1166.496 ;
      RECT 0.492 1168.800 260.316 1168.896 ;
      RECT 0.492 1171.200 260.316 1171.296 ;
      RECT 0.492 1173.600 260.316 1173.696 ;
      RECT 0.492 1176.000 260.316 1176.096 ;
      RECT 0.492 1178.400 260.316 1178.496 ;
      RECT 0.492 1180.800 260.316 1180.896 ;
      RECT 0.492 1183.200 260.316 1183.296 ;
      RECT 0.492 1185.600 260.316 1185.696 ;
      RECT 0.492 1188.000 260.316 1188.096 ;
      RECT 0.492 1190.400 260.316 1190.496 ;
      RECT 0.492 1192.800 260.316 1192.896 ;
      RECT 0.492 1195.200 260.316 1195.296 ;
      RECT 0.492 1197.600 260.316 1197.696 ;
      RECT 0.492 1200.000 260.316 1200.096 ;
      RECT 0.492 1202.400 260.316 1202.496 ;
      RECT 0.492 1204.800 260.316 1204.896 ;
      RECT 0.492 1207.200 260.316 1207.296 ;
      RECT 0.492 1209.600 260.316 1209.696 ;
      RECT 0.492 1212.000 260.316 1212.096 ;
      RECT 0.492 1214.400 260.316 1214.496 ;
      RECT 0.492 1216.800 260.316 1216.896 ;
      RECT 0.492 1219.200 260.316 1219.296 ;
      RECT 0.492 1221.600 260.316 1221.696 ;
      RECT 0.492 1224.000 260.316 1224.096 ;
      RECT 0.492 1226.400 260.316 1226.496 ;
      RECT 0.492 1228.800 260.316 1228.896 ;
      RECT 0.492 1231.200 260.316 1231.296 ;
      RECT 0.492 1233.600 260.316 1233.696 ;
      RECT 0.492 1236.000 260.316 1236.096 ;
      RECT 0.492 1238.400 260.316 1238.496 ;
      RECT 0.492 1240.800 260.316 1240.896 ;
      RECT 0.492 1243.200 260.316 1243.296 ;
      RECT 0.492 1245.600 260.316 1245.696 ;
      RECT 0.492 1248.000 260.316 1248.096 ;
      RECT 0.492 1250.400 260.316 1250.496 ;
      RECT 0.492 1252.800 260.316 1252.896 ;
      RECT 0.492 1255.200 260.316 1255.296 ;
      RECT 0.492 1257.600 260.316 1257.696 ;
      RECT 0.492 1260.000 260.316 1260.096 ;
      RECT 0.492 1262.400 260.316 1262.496 ;
      RECT 0.492 1264.800 260.316 1264.896 ;
      RECT 0.492 1267.200 260.316 1267.296 ;
      RECT 0.492 1269.600 260.316 1269.696 ;
      RECT 0.492 1272.000 260.316 1272.096 ;
      RECT 0.492 1274.400 260.316 1274.496 ;
      RECT 0.492 1276.800 260.316 1276.896 ;
      RECT 0.492 1279.200 260.316 1279.296 ;
      RECT 0.492 1281.600 260.316 1281.696 ;
      RECT 0.492 1284.000 260.316 1284.096 ;
      RECT 0.492 1286.400 260.316 1286.496 ;
      RECT 0.492 1288.800 260.316 1288.896 ;
      RECT 0.492 1291.200 260.316 1291.296 ;
      RECT 0.492 1293.600 260.316 1293.696 ;
      RECT 0.492 1296.000 260.316 1296.096 ;
      RECT 0.492 1298.400 260.316 1298.496 ;
      RECT 0.492 1300.800 260.316 1300.896 ;
      RECT 0.492 1303.200 260.316 1303.296 ;
      RECT 0.492 1305.600 260.316 1305.696 ;
      RECT 0.492 1308.000 260.316 1308.096 ;
      RECT 0.492 1310.400 260.316 1310.496 ;
      RECT 0.492 1312.800 260.316 1312.896 ;
      RECT 0.492 1315.200 260.316 1315.296 ;
      RECT 0.492 1317.600 260.316 1317.696 ;
      RECT 0.492 1320.000 260.316 1320.096 ;
      RECT 0.492 1322.400 260.316 1322.496 ;
      RECT 0.492 1324.800 260.316 1324.896 ;
      RECT 0.492 1327.200 260.316 1327.296 ;
      RECT 0.492 1329.600 260.316 1329.696 ;
      RECT 0.492 1332.000 260.316 1332.096 ;
      RECT 0.492 1334.400 260.316 1334.496 ;
      RECT 0.492 1336.800 260.316 1336.896 ;
      RECT 0.492 1339.200 260.316 1339.296 ;
      RECT 0.492 1341.600 260.316 1341.696 ;
      RECT 0.492 1344.000 260.316 1344.096 ;
      RECT 0.492 1346.400 260.316 1346.496 ;
      RECT 0.492 1348.800 260.316 1348.896 ;
      RECT 0.492 1351.200 260.316 1351.296 ;
      RECT 0.492 1353.600 260.316 1353.696 ;
      RECT 0.492 1356.000 260.316 1356.096 ;
      RECT 0.492 1358.400 260.316 1358.496 ;
      RECT 0.492 1360.800 260.316 1360.896 ;
      RECT 0.492 1363.200 260.316 1363.296 ;
      RECT 0.492 1365.600 260.316 1365.696 ;
      RECT 0.492 1368.000 260.316 1368.096 ;
      RECT 0.492 1370.400 260.316 1370.496 ;
      RECT 0.492 1372.800 260.316 1372.896 ;
      RECT 0.492 1375.200 260.316 1375.296 ;
      RECT 0.492 1377.600 260.316 1377.696 ;
      RECT 0.492 1380.000 260.316 1380.096 ;
      RECT 0.492 1382.400 260.316 1382.496 ;
      RECT 0.492 1384.800 260.316 1384.896 ;
      RECT 0.492 1387.200 260.316 1387.296 ;
      RECT 0.492 1389.600 260.316 1389.696 ;
      RECT 0.492 1392.000 260.316 1392.096 ;
      RECT 0.492 1394.400 260.316 1394.496 ;
      RECT 0.492 1396.800 260.316 1396.896 ;
      RECT 0.492 1399.200 260.316 1399.296 ;
      RECT 0.492 1401.600 260.316 1401.696 ;
      RECT 0.492 1404.000 260.316 1404.096 ;
      RECT 0.492 1406.400 260.316 1406.496 ;
      RECT 0.492 1408.800 260.316 1408.896 ;
      RECT 0.492 1411.200 260.316 1411.296 ;
      RECT 0.492 1413.600 260.316 1413.696 ;
      RECT 0.492 1416.000 260.316 1416.096 ;
      RECT 0.492 1418.400 260.316 1418.496 ;
      RECT 0.492 1420.800 260.316 1420.896 ;
      RECT 0.492 1423.200 260.316 1423.296 ;
      RECT 0.492 1425.600 260.316 1425.696 ;
      RECT 0.492 1428.000 260.316 1428.096 ;
      RECT 0.492 1430.400 260.316 1430.496 ;
      RECT 0.492 1432.800 260.316 1432.896 ;
      RECT 0.492 1435.200 260.316 1435.296 ;
      RECT 0.492 1437.600 260.316 1437.696 ;
      RECT 0.492 1440.000 260.316 1440.096 ;
      RECT 0.492 1442.400 260.316 1442.496 ;
      RECT 0.492 1444.800 260.316 1444.896 ;
      RECT 0.492 1447.200 260.316 1447.296 ;
      RECT 0.492 1449.600 260.316 1449.696 ;
      RECT 0.492 1452.000 260.316 1452.096 ;
      RECT 0.492 1454.400 260.316 1454.496 ;
      RECT 0.492 1456.800 260.316 1456.896 ;
      RECT 0.492 1459.200 260.316 1459.296 ;
      RECT 0.492 1461.600 260.316 1461.696 ;
      RECT 0.492 1464.000 260.316 1464.096 ;
      RECT 0.492 1466.400 260.316 1466.496 ;
      RECT 0.492 1468.800 260.316 1468.896 ;
      RECT 0.492 1471.200 260.316 1471.296 ;
      RECT 0.492 1473.600 260.316 1473.696 ;
      RECT 0.492 1476.000 260.316 1476.096 ;
      RECT 0.492 1478.400 260.316 1478.496 ;
      RECT 0.492 1480.800 260.316 1480.896 ;
      RECT 0.492 1483.200 260.316 1483.296 ;
      RECT 0.492 1485.600 260.316 1485.696 ;
      RECT 0.492 1488.000 260.316 1488.096 ;
      RECT 0.492 1490.400 260.316 1490.496 ;
      RECT 0.492 1492.800 260.316 1492.896 ;
      RECT 0.492 1495.200 260.316 1495.296 ;
      RECT 0.492 1497.600 260.316 1497.696 ;
      RECT 0.492 1500.000 260.316 1500.096 ;
      RECT 0.492 1502.400 260.316 1502.496 ;
      RECT 0.492 1504.800 260.316 1504.896 ;
      RECT 0.492 1507.200 260.316 1507.296 ;
      RECT 0.492 1509.600 260.316 1509.696 ;
      RECT 0.492 1512.000 260.316 1512.096 ;
      RECT 0.492 1514.400 260.316 1514.496 ;
      RECT 0.492 1516.800 260.316 1516.896 ;
      RECT 0.492 1519.200 260.316 1519.296 ;
      RECT 0.492 1521.600 260.316 1521.696 ;
      RECT 0.492 1524.000 260.316 1524.096 ;
      RECT 0.492 1526.400 260.316 1526.496 ;
      RECT 0.492 1528.800 260.316 1528.896 ;
      RECT 0.492 1531.200 260.316 1531.296 ;
      RECT 0.492 1533.600 260.316 1533.696 ;
      RECT 0.492 1536.000 260.316 1536.096 ;
      RECT 0.492 1538.400 260.316 1538.496 ;
      RECT 0.492 1540.800 260.316 1540.896 ;
      RECT 0.492 1543.200 260.316 1543.296 ;
      RECT 0.492 1545.600 260.316 1545.696 ;
      RECT 0.492 1548.000 260.316 1548.096 ;
      RECT 0.492 1550.400 260.316 1550.496 ;
      RECT 0.492 1552.800 260.316 1552.896 ;
      RECT 0.492 1555.200 260.316 1555.296 ;
      RECT 0.492 1557.600 260.316 1557.696 ;
      RECT 0.492 1560.000 260.316 1560.096 ;
      RECT 0.492 1562.400 260.316 1562.496 ;
      RECT 0.492 1564.800 260.316 1564.896 ;
      RECT 0.492 1567.200 260.316 1567.296 ;
      RECT 0.492 1569.600 260.316 1569.696 ;
      RECT 0.492 1572.000 260.316 1572.096 ;
      RECT 0.492 1574.400 260.316 1574.496 ;
      RECT 0.492 1576.800 260.316 1576.896 ;
      RECT 0.492 1579.200 260.316 1579.296 ;
      RECT 0.492 1581.600 260.316 1581.696 ;
      RECT 0.492 1584.000 260.316 1584.096 ;
      RECT 0.492 1586.400 260.316 1586.496 ;
      RECT 0.492 1588.800 260.316 1588.896 ;
      RECT 0.492 1591.200 260.316 1591.296 ;
      RECT 0.492 1593.600 260.316 1593.696 ;
      RECT 0.492 1596.000 260.316 1596.096 ;
      RECT 0.492 1598.400 260.316 1598.496 ;
      RECT 0.492 1600.800 260.316 1600.896 ;
      RECT 0.492 1603.200 260.316 1603.296 ;
      RECT 0.492 1605.600 260.316 1605.696 ;
      RECT 0.492 1608.000 260.316 1608.096 ;
      RECT 0.492 1610.400 260.316 1610.496 ;
      RECT 0.492 1612.800 260.316 1612.896 ;
      RECT 0.492 1615.200 260.316 1615.296 ;
      RECT 0.492 1617.600 260.316 1617.696 ;
      RECT 0.492 1620.000 260.316 1620.096 ;
      RECT 0.492 1622.400 260.316 1622.496 ;
      RECT 0.492 1624.800 260.316 1624.896 ;
      RECT 0.492 1627.200 260.316 1627.296 ;
      RECT 0.492 1629.600 260.316 1629.696 ;
      RECT 0.492 1632.000 260.316 1632.096 ;
      RECT 0.492 1634.400 260.316 1634.496 ;
      RECT 0.492 1636.800 260.316 1636.896 ;
      RECT 0.492 1639.200 260.316 1639.296 ;
      RECT 0.492 1641.600 260.316 1641.696 ;
      RECT 0.492 1644.000 260.316 1644.096 ;
      RECT 0.492 1646.400 260.316 1646.496 ;
      RECT 0.492 1648.800 260.316 1648.896 ;
      RECT 0.492 1651.200 260.316 1651.296 ;
    END
  END VDD
  OBS
    LAYER M1 ;
    RECT 0 0 260.808 1652.424 ;
    LAYER M2 ;
    RECT 0 0 260.808 1652.424 ;
    LAYER M3 ;
    RECT 0 0 260.808 1652.424 ;
    LAYER M4 ;
    RECT 0 0 260.808 1652.424 ;
  END
END ot_pdie_ucie

END LIBRARY
